VERSION 5.8 ;
BUSBITCHARS "[]" ;
DIVIDERCHAR "/" ;
UNITS
    DATABASE MICRONS 1000 ;
END UNITS

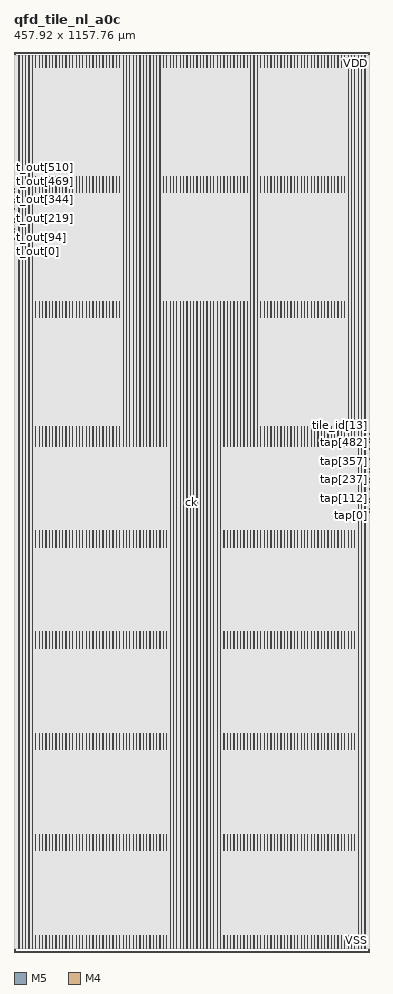
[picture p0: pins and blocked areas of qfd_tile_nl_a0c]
MACRO qfd_tile_nl_a0c
  FOREIGN qfd_tile_nl_a0c 0 0 ;
  CLASS BLOCK ;
  SIZE 457.92 BY 1157.76 ;
  PIN ck
    DIRECTION INPUT ;
    USE SIGNAL ;
    PORT
      LAYER M5 ;
        RECT  228.948 578.64 228.996 579.12 ;
    END
  END ck
  PIN rst_n
    DIRECTION INPUT ;
    USE SIGNAL ;
    PORT
      LAYER M4 ;
        RECT  457.836 669.984 457.92 670.008 ;
    END
  END rst_n
  PIN t_out[0]
    DIRECTION OUTPUT ;
    USE SIGNAL ;
    PORT
      LAYER M4 ;
        RECT  0 900.672 0.084 900.696 ;
    END
  END t_out[0]
  PIN t_out[100]
    DIRECTION OUTPUT ;
    USE SIGNAL ;
    PORT
      LAYER M4 ;
        RECT  0 920.64 0.084 920.664 ;
    END
  END t_out[100]
  PIN t_out[101]
    DIRECTION OUTPUT ;
    USE SIGNAL ;
    PORT
      LAYER M4 ;
        RECT  0 920.832 0.084 920.856 ;
    END
  END t_out[101]
  PIN t_out[102]
    DIRECTION OUTPUT ;
    USE SIGNAL ;
    PORT
      LAYER M4 ;
        RECT  0 921.024 0.084 921.048 ;
    END
  END t_out[102]
  PIN t_out[103]
    DIRECTION OUTPUT ;
    USE SIGNAL ;
    PORT
      LAYER M4 ;
        RECT  0 921.216 0.084 921.24 ;
    END
  END t_out[103]
  PIN t_out[104]
    DIRECTION OUTPUT ;
    USE SIGNAL ;
    PORT
      LAYER M4 ;
        RECT  0 921.408 0.084 921.432 ;
    END
  END t_out[104]
  PIN t_out[105]
    DIRECTION OUTPUT ;
    USE SIGNAL ;
    PORT
      LAYER M4 ;
        RECT  0 921.6 0.084 921.624 ;
    END
  END t_out[105]
  PIN t_out[106]
    DIRECTION OUTPUT ;
    USE SIGNAL ;
    PORT
      LAYER M4 ;
        RECT  0 921.792 0.084 921.816 ;
    END
  END t_out[106]
  PIN t_out[107]
    DIRECTION OUTPUT ;
    USE SIGNAL ;
    PORT
      LAYER M4 ;
        RECT  0 921.984 0.084 922.008 ;
    END
  END t_out[107]
  PIN t_out[108]
    DIRECTION OUTPUT ;
    USE SIGNAL ;
    PORT
      LAYER M4 ;
        RECT  0 922.176 0.084 922.2 ;
    END
  END t_out[108]
  PIN t_out[109]
    DIRECTION OUTPUT ;
    USE SIGNAL ;
    PORT
      LAYER M4 ;
        RECT  0 922.368 0.084 922.392 ;
    END
  END t_out[109]
  PIN t_out[10]
    DIRECTION OUTPUT ;
    USE SIGNAL ;
    PORT
      LAYER M4 ;
        RECT  0 902.592 0.084 902.616 ;
    END
  END t_out[10]
  PIN t_out[110]
    DIRECTION OUTPUT ;
    USE SIGNAL ;
    PORT
      LAYER M4 ;
        RECT  0 922.56 0.084 922.584 ;
    END
  END t_out[110]
  PIN t_out[111]
    DIRECTION OUTPUT ;
    USE SIGNAL ;
    PORT
      LAYER M4 ;
        RECT  0 922.752 0.084 922.776 ;
    END
  END t_out[111]
  PIN t_out[112]
    DIRECTION OUTPUT ;
    USE SIGNAL ;
    PORT
      LAYER M4 ;
        RECT  0 922.944 0.084 922.968 ;
    END
  END t_out[112]
  PIN t_out[113]
    DIRECTION OUTPUT ;
    USE SIGNAL ;
    PORT
      LAYER M4 ;
        RECT  0 923.136 0.084 923.16 ;
    END
  END t_out[113]
  PIN t_out[114]
    DIRECTION OUTPUT ;
    USE SIGNAL ;
    PORT
      LAYER M4 ;
        RECT  0 923.328 0.084 923.352 ;
    END
  END t_out[114]
  PIN t_out[115]
    DIRECTION OUTPUT ;
    USE SIGNAL ;
    PORT
      LAYER M4 ;
        RECT  0 923.52 0.084 923.544 ;
    END
  END t_out[115]
  PIN t_out[116]
    DIRECTION OUTPUT ;
    USE SIGNAL ;
    PORT
      LAYER M4 ;
        RECT  0 923.712 0.084 923.736 ;
    END
  END t_out[116]
  PIN t_out[117]
    DIRECTION OUTPUT ;
    USE SIGNAL ;
    PORT
      LAYER M4 ;
        RECT  0 923.904 0.084 923.928 ;
    END
  END t_out[117]
  PIN t_out[118]
    DIRECTION OUTPUT ;
    USE SIGNAL ;
    PORT
      LAYER M4 ;
        RECT  0 924.096 0.084 924.12 ;
    END
  END t_out[118]
  PIN t_out[119]
    DIRECTION OUTPUT ;
    USE SIGNAL ;
    PORT
      LAYER M4 ;
        RECT  0 924.288 0.084 924.312 ;
    END
  END t_out[119]
  PIN t_out[11]
    DIRECTION OUTPUT ;
    USE SIGNAL ;
    PORT
      LAYER M4 ;
        RECT  0 902.784 0.084 902.808 ;
    END
  END t_out[11]
  PIN t_out[120]
    DIRECTION OUTPUT ;
    USE SIGNAL ;
    PORT
      LAYER M4 ;
        RECT  0 924.48 0.084 924.504 ;
    END
  END t_out[120]
  PIN t_out[121]
    DIRECTION OUTPUT ;
    USE SIGNAL ;
    PORT
      LAYER M4 ;
        RECT  0 924.672 0.084 924.696 ;
    END
  END t_out[121]
  PIN t_out[122]
    DIRECTION OUTPUT ;
    USE SIGNAL ;
    PORT
      LAYER M4 ;
        RECT  0 924.864 0.084 924.888 ;
    END
  END t_out[122]
  PIN t_out[123]
    DIRECTION OUTPUT ;
    USE SIGNAL ;
    PORT
      LAYER M4 ;
        RECT  0 925.056 0.084 925.08 ;
    END
  END t_out[123]
  PIN t_out[124]
    DIRECTION OUTPUT ;
    USE SIGNAL ;
    PORT
      LAYER M4 ;
        RECT  0 925.248 0.084 925.272 ;
    END
  END t_out[124]
  PIN t_out[125]
    DIRECTION OUTPUT ;
    USE SIGNAL ;
    PORT
      LAYER M4 ;
        RECT  0 925.44 0.084 925.464 ;
    END
  END t_out[125]
  PIN t_out[126]
    DIRECTION OUTPUT ;
    USE SIGNAL ;
    PORT
      LAYER M4 ;
        RECT  0 925.632 0.084 925.656 ;
    END
  END t_out[126]
  PIN t_out[127]
    DIRECTION OUTPUT ;
    USE SIGNAL ;
    PORT
      LAYER M4 ;
        RECT  0 925.824 0.084 925.848 ;
    END
  END t_out[127]
  PIN t_out[128]
    DIRECTION OUTPUT ;
    USE SIGNAL ;
    PORT
      LAYER M4 ;
        RECT  0 926.016 0.084 926.04 ;
    END
  END t_out[128]
  PIN t_out[129]
    DIRECTION OUTPUT ;
    USE SIGNAL ;
    PORT
      LAYER M4 ;
        RECT  0 926.208 0.084 926.232 ;
    END
  END t_out[129]
  PIN t_out[12]
    DIRECTION OUTPUT ;
    USE SIGNAL ;
    PORT
      LAYER M4 ;
        RECT  0 902.976 0.084 903 ;
    END
  END t_out[12]
  PIN t_out[130]
    DIRECTION OUTPUT ;
    USE SIGNAL ;
    PORT
      LAYER M4 ;
        RECT  0 926.4 0.084 926.424 ;
    END
  END t_out[130]
  PIN t_out[131]
    DIRECTION OUTPUT ;
    USE SIGNAL ;
    PORT
      LAYER M4 ;
        RECT  0 926.592 0.084 926.616 ;
    END
  END t_out[131]
  PIN t_out[132]
    DIRECTION OUTPUT ;
    USE SIGNAL ;
    PORT
      LAYER M4 ;
        RECT  0 926.784 0.084 926.808 ;
    END
  END t_out[132]
  PIN t_out[133]
    DIRECTION OUTPUT ;
    USE SIGNAL ;
    PORT
      LAYER M4 ;
        RECT  0 926.976 0.084 927 ;
    END
  END t_out[133]
  PIN t_out[134]
    DIRECTION OUTPUT ;
    USE SIGNAL ;
    PORT
      LAYER M4 ;
        RECT  0 927.168 0.084 927.192 ;
    END
  END t_out[134]
  PIN t_out[135]
    DIRECTION OUTPUT ;
    USE SIGNAL ;
    PORT
      LAYER M4 ;
        RECT  0 927.36 0.084 927.384 ;
    END
  END t_out[135]
  PIN t_out[136]
    DIRECTION OUTPUT ;
    USE SIGNAL ;
    PORT
      LAYER M4 ;
        RECT  0 927.552 0.084 927.576 ;
    END
  END t_out[136]
  PIN t_out[137]
    DIRECTION OUTPUT ;
    USE SIGNAL ;
    PORT
      LAYER M4 ;
        RECT  0 927.744 0.084 927.768 ;
    END
  END t_out[137]
  PIN t_out[138]
    DIRECTION OUTPUT ;
    USE SIGNAL ;
    PORT
      LAYER M4 ;
        RECT  0 927.936 0.084 927.96 ;
    END
  END t_out[138]
  PIN t_out[139]
    DIRECTION OUTPUT ;
    USE SIGNAL ;
    PORT
      LAYER M4 ;
        RECT  0 928.128 0.084 928.152 ;
    END
  END t_out[139]
  PIN t_out[13]
    DIRECTION OUTPUT ;
    USE SIGNAL ;
    PORT
      LAYER M4 ;
        RECT  0 903.168 0.084 903.192 ;
    END
  END t_out[13]
  PIN t_out[140]
    DIRECTION OUTPUT ;
    USE SIGNAL ;
    PORT
      LAYER M4 ;
        RECT  0 928.32 0.084 928.344 ;
    END
  END t_out[140]
  PIN t_out[141]
    DIRECTION OUTPUT ;
    USE SIGNAL ;
    PORT
      LAYER M4 ;
        RECT  0 928.512 0.084 928.536 ;
    END
  END t_out[141]
  PIN t_out[142]
    DIRECTION OUTPUT ;
    USE SIGNAL ;
    PORT
      LAYER M4 ;
        RECT  0 928.704 0.084 928.728 ;
    END
  END t_out[142]
  PIN t_out[143]
    DIRECTION OUTPUT ;
    USE SIGNAL ;
    PORT
      LAYER M4 ;
        RECT  0 928.896 0.084 928.92 ;
    END
  END t_out[143]
  PIN t_out[144]
    DIRECTION OUTPUT ;
    USE SIGNAL ;
    PORT
      LAYER M4 ;
        RECT  0 929.088 0.084 929.112 ;
    END
  END t_out[144]
  PIN t_out[145]
    DIRECTION OUTPUT ;
    USE SIGNAL ;
    PORT
      LAYER M4 ;
        RECT  0 929.28 0.084 929.304 ;
    END
  END t_out[145]
  PIN t_out[146]
    DIRECTION OUTPUT ;
    USE SIGNAL ;
    PORT
      LAYER M4 ;
        RECT  0 929.472 0.084 929.496 ;
    END
  END t_out[146]
  PIN t_out[147]
    DIRECTION OUTPUT ;
    USE SIGNAL ;
    PORT
      LAYER M4 ;
        RECT  0 929.664 0.084 929.688 ;
    END
  END t_out[147]
  PIN t_out[148]
    DIRECTION OUTPUT ;
    USE SIGNAL ;
    PORT
      LAYER M4 ;
        RECT  0 929.856 0.084 929.88 ;
    END
  END t_out[148]
  PIN t_out[149]
    DIRECTION OUTPUT ;
    USE SIGNAL ;
    PORT
      LAYER M4 ;
        RECT  0 930.048 0.084 930.072 ;
    END
  END t_out[149]
  PIN t_out[14]
    DIRECTION OUTPUT ;
    USE SIGNAL ;
    PORT
      LAYER M4 ;
        RECT  0 903.36 0.084 903.384 ;
    END
  END t_out[14]
  PIN t_out[150]
    DIRECTION OUTPUT ;
    USE SIGNAL ;
    PORT
      LAYER M4 ;
        RECT  0 930.24 0.084 930.264 ;
    END
  END t_out[150]
  PIN t_out[151]
    DIRECTION OUTPUT ;
    USE SIGNAL ;
    PORT
      LAYER M4 ;
        RECT  0 930.432 0.084 930.456 ;
    END
  END t_out[151]
  PIN t_out[152]
    DIRECTION OUTPUT ;
    USE SIGNAL ;
    PORT
      LAYER M4 ;
        RECT  0 930.624 0.084 930.648 ;
    END
  END t_out[152]
  PIN t_out[153]
    DIRECTION OUTPUT ;
    USE SIGNAL ;
    PORT
      LAYER M4 ;
        RECT  0 930.816 0.084 930.84 ;
    END
  END t_out[153]
  PIN t_out[154]
    DIRECTION OUTPUT ;
    USE SIGNAL ;
    PORT
      LAYER M4 ;
        RECT  0 931.008 0.084 931.032 ;
    END
  END t_out[154]
  PIN t_out[155]
    DIRECTION OUTPUT ;
    USE SIGNAL ;
    PORT
      LAYER M4 ;
        RECT  0 931.2 0.084 931.224 ;
    END
  END t_out[155]
  PIN t_out[156]
    DIRECTION OUTPUT ;
    USE SIGNAL ;
    PORT
      LAYER M4 ;
        RECT  0 931.392 0.084 931.416 ;
    END
  END t_out[156]
  PIN t_out[157]
    DIRECTION OUTPUT ;
    USE SIGNAL ;
    PORT
      LAYER M4 ;
        RECT  0 931.584 0.084 931.608 ;
    END
  END t_out[157]
  PIN t_out[158]
    DIRECTION OUTPUT ;
    USE SIGNAL ;
    PORT
      LAYER M4 ;
        RECT  0 931.776 0.084 931.8 ;
    END
  END t_out[158]
  PIN t_out[159]
    DIRECTION OUTPUT ;
    USE SIGNAL ;
    PORT
      LAYER M4 ;
        RECT  0 931.968 0.084 931.992 ;
    END
  END t_out[159]
  PIN t_out[15]
    DIRECTION OUTPUT ;
    USE SIGNAL ;
    PORT
      LAYER M4 ;
        RECT  0 903.552 0.084 903.576 ;
    END
  END t_out[15]
  PIN t_out[160]
    DIRECTION OUTPUT ;
    USE SIGNAL ;
    PORT
      LAYER M4 ;
        RECT  0 932.16 0.084 932.184 ;
    END
  END t_out[160]
  PIN t_out[161]
    DIRECTION OUTPUT ;
    USE SIGNAL ;
    PORT
      LAYER M4 ;
        RECT  0 932.352 0.084 932.376 ;
    END
  END t_out[161]
  PIN t_out[162]
    DIRECTION OUTPUT ;
    USE SIGNAL ;
    PORT
      LAYER M4 ;
        RECT  0 932.544 0.084 932.568 ;
    END
  END t_out[162]
  PIN t_out[163]
    DIRECTION OUTPUT ;
    USE SIGNAL ;
    PORT
      LAYER M4 ;
        RECT  0 932.736 0.084 932.76 ;
    END
  END t_out[163]
  PIN t_out[164]
    DIRECTION OUTPUT ;
    USE SIGNAL ;
    PORT
      LAYER M4 ;
        RECT  0 932.928 0.084 932.952 ;
    END
  END t_out[164]
  PIN t_out[165]
    DIRECTION OUTPUT ;
    USE SIGNAL ;
    PORT
      LAYER M4 ;
        RECT  0 933.12 0.084 933.144 ;
    END
  END t_out[165]
  PIN t_out[166]
    DIRECTION OUTPUT ;
    USE SIGNAL ;
    PORT
      LAYER M4 ;
        RECT  0 933.312 0.084 933.336 ;
    END
  END t_out[166]
  PIN t_out[167]
    DIRECTION OUTPUT ;
    USE SIGNAL ;
    PORT
      LAYER M4 ;
        RECT  0 933.504 0.084 933.528 ;
    END
  END t_out[167]
  PIN t_out[168]
    DIRECTION OUTPUT ;
    USE SIGNAL ;
    PORT
      LAYER M4 ;
        RECT  0 933.696 0.084 933.72 ;
    END
  END t_out[168]
  PIN t_out[169]
    DIRECTION OUTPUT ;
    USE SIGNAL ;
    PORT
      LAYER M4 ;
        RECT  0 933.888 0.084 933.912 ;
    END
  END t_out[169]
  PIN t_out[16]
    DIRECTION OUTPUT ;
    USE SIGNAL ;
    PORT
      LAYER M4 ;
        RECT  0 903.744 0.084 903.768 ;
    END
  END t_out[16]
  PIN t_out[170]
    DIRECTION OUTPUT ;
    USE SIGNAL ;
    PORT
      LAYER M4 ;
        RECT  0 934.08 0.084 934.104 ;
    END
  END t_out[170]
  PIN t_out[171]
    DIRECTION OUTPUT ;
    USE SIGNAL ;
    PORT
      LAYER M4 ;
        RECT  0 934.272 0.084 934.296 ;
    END
  END t_out[171]
  PIN t_out[172]
    DIRECTION OUTPUT ;
    USE SIGNAL ;
    PORT
      LAYER M4 ;
        RECT  0 934.464 0.084 934.488 ;
    END
  END t_out[172]
  PIN t_out[173]
    DIRECTION OUTPUT ;
    USE SIGNAL ;
    PORT
      LAYER M4 ;
        RECT  0 934.656 0.084 934.68 ;
    END
  END t_out[173]
  PIN t_out[174]
    DIRECTION OUTPUT ;
    USE SIGNAL ;
    PORT
      LAYER M4 ;
        RECT  0 934.848 0.084 934.872 ;
    END
  END t_out[174]
  PIN t_out[175]
    DIRECTION OUTPUT ;
    USE SIGNAL ;
    PORT
      LAYER M4 ;
        RECT  0 935.04 0.084 935.064 ;
    END
  END t_out[175]
  PIN t_out[176]
    DIRECTION OUTPUT ;
    USE SIGNAL ;
    PORT
      LAYER M4 ;
        RECT  0 935.232 0.084 935.256 ;
    END
  END t_out[176]
  PIN t_out[177]
    DIRECTION OUTPUT ;
    USE SIGNAL ;
    PORT
      LAYER M4 ;
        RECT  0 935.424 0.084 935.448 ;
    END
  END t_out[177]
  PIN t_out[178]
    DIRECTION OUTPUT ;
    USE SIGNAL ;
    PORT
      LAYER M4 ;
        RECT  0 935.616 0.084 935.64 ;
    END
  END t_out[178]
  PIN t_out[179]
    DIRECTION OUTPUT ;
    USE SIGNAL ;
    PORT
      LAYER M4 ;
        RECT  0 935.808 0.084 935.832 ;
    END
  END t_out[179]
  PIN t_out[17]
    DIRECTION OUTPUT ;
    USE SIGNAL ;
    PORT
      LAYER M4 ;
        RECT  0 903.936 0.084 903.96 ;
    END
  END t_out[17]
  PIN t_out[180]
    DIRECTION OUTPUT ;
    USE SIGNAL ;
    PORT
      LAYER M4 ;
        RECT  0 936 0.084 936.024 ;
    END
  END t_out[180]
  PIN t_out[181]
    DIRECTION OUTPUT ;
    USE SIGNAL ;
    PORT
      LAYER M4 ;
        RECT  0 936.192 0.084 936.216 ;
    END
  END t_out[181]
  PIN t_out[182]
    DIRECTION OUTPUT ;
    USE SIGNAL ;
    PORT
      LAYER M4 ;
        RECT  0 936.384 0.084 936.408 ;
    END
  END t_out[182]
  PIN t_out[183]
    DIRECTION OUTPUT ;
    USE SIGNAL ;
    PORT
      LAYER M4 ;
        RECT  0 936.576 0.084 936.6 ;
    END
  END t_out[183]
  PIN t_out[184]
    DIRECTION OUTPUT ;
    USE SIGNAL ;
    PORT
      LAYER M4 ;
        RECT  0 936.768 0.084 936.792 ;
    END
  END t_out[184]
  PIN t_out[185]
    DIRECTION OUTPUT ;
    USE SIGNAL ;
    PORT
      LAYER M4 ;
        RECT  0 936.96 0.084 936.984 ;
    END
  END t_out[185]
  PIN t_out[186]
    DIRECTION OUTPUT ;
    USE SIGNAL ;
    PORT
      LAYER M4 ;
        RECT  0 937.152 0.084 937.176 ;
    END
  END t_out[186]
  PIN t_out[187]
    DIRECTION OUTPUT ;
    USE SIGNAL ;
    PORT
      LAYER M4 ;
        RECT  0 937.344 0.084 937.368 ;
    END
  END t_out[187]
  PIN t_out[188]
    DIRECTION OUTPUT ;
    USE SIGNAL ;
    PORT
      LAYER M4 ;
        RECT  0 937.536 0.084 937.56 ;
    END
  END t_out[188]
  PIN t_out[189]
    DIRECTION OUTPUT ;
    USE SIGNAL ;
    PORT
      LAYER M4 ;
        RECT  0 937.728 0.084 937.752 ;
    END
  END t_out[189]
  PIN t_out[18]
    DIRECTION OUTPUT ;
    USE SIGNAL ;
    PORT
      LAYER M4 ;
        RECT  0 904.128 0.084 904.152 ;
    END
  END t_out[18]
  PIN t_out[190]
    DIRECTION OUTPUT ;
    USE SIGNAL ;
    PORT
      LAYER M4 ;
        RECT  0 937.92 0.084 937.944 ;
    END
  END t_out[190]
  PIN t_out[191]
    DIRECTION OUTPUT ;
    USE SIGNAL ;
    PORT
      LAYER M4 ;
        RECT  0 938.112 0.084 938.136 ;
    END
  END t_out[191]
  PIN t_out[192]
    DIRECTION OUTPUT ;
    USE SIGNAL ;
    PORT
      LAYER M4 ;
        RECT  0 938.304 0.084 938.328 ;
    END
  END t_out[192]
  PIN t_out[193]
    DIRECTION OUTPUT ;
    USE SIGNAL ;
    PORT
      LAYER M4 ;
        RECT  0 938.496 0.084 938.52 ;
    END
  END t_out[193]
  PIN t_out[194]
    DIRECTION OUTPUT ;
    USE SIGNAL ;
    PORT
      LAYER M4 ;
        RECT  0 938.688 0.084 938.712 ;
    END
  END t_out[194]
  PIN t_out[195]
    DIRECTION OUTPUT ;
    USE SIGNAL ;
    PORT
      LAYER M4 ;
        RECT  0 938.88 0.084 938.904 ;
    END
  END t_out[195]
  PIN t_out[196]
    DIRECTION OUTPUT ;
    USE SIGNAL ;
    PORT
      LAYER M4 ;
        RECT  0 939.072 0.084 939.096 ;
    END
  END t_out[196]
  PIN t_out[197]
    DIRECTION OUTPUT ;
    USE SIGNAL ;
    PORT
      LAYER M4 ;
        RECT  0 939.264 0.084 939.288 ;
    END
  END t_out[197]
  PIN t_out[198]
    DIRECTION OUTPUT ;
    USE SIGNAL ;
    PORT
      LAYER M4 ;
        RECT  0 939.456 0.084 939.48 ;
    END
  END t_out[198]
  PIN t_out[199]
    DIRECTION OUTPUT ;
    USE SIGNAL ;
    PORT
      LAYER M4 ;
        RECT  0 939.648 0.084 939.672 ;
    END
  END t_out[199]
  PIN t_out[19]
    DIRECTION OUTPUT ;
    USE SIGNAL ;
    PORT
      LAYER M4 ;
        RECT  0 904.32 0.084 904.344 ;
    END
  END t_out[19]
  PIN t_out[1]
    DIRECTION OUTPUT ;
    USE SIGNAL ;
    PORT
      LAYER M4 ;
        RECT  0 900.864 0.084 900.888 ;
    END
  END t_out[1]
  PIN t_out[200]
    DIRECTION OUTPUT ;
    USE SIGNAL ;
    PORT
      LAYER M4 ;
        RECT  0 939.84 0.084 939.864 ;
    END
  END t_out[200]
  PIN t_out[201]
    DIRECTION OUTPUT ;
    USE SIGNAL ;
    PORT
      LAYER M4 ;
        RECT  0 940.032 0.084 940.056 ;
    END
  END t_out[201]
  PIN t_out[202]
    DIRECTION OUTPUT ;
    USE SIGNAL ;
    PORT
      LAYER M4 ;
        RECT  0 940.224 0.084 940.248 ;
    END
  END t_out[202]
  PIN t_out[203]
    DIRECTION OUTPUT ;
    USE SIGNAL ;
    PORT
      LAYER M4 ;
        RECT  0 940.416 0.084 940.44 ;
    END
  END t_out[203]
  PIN t_out[204]
    DIRECTION OUTPUT ;
    USE SIGNAL ;
    PORT
      LAYER M4 ;
        RECT  0 940.608 0.084 940.632 ;
    END
  END t_out[204]
  PIN t_out[205]
    DIRECTION OUTPUT ;
    USE SIGNAL ;
    PORT
      LAYER M4 ;
        RECT  0 940.8 0.084 940.824 ;
    END
  END t_out[205]
  PIN t_out[206]
    DIRECTION OUTPUT ;
    USE SIGNAL ;
    PORT
      LAYER M4 ;
        RECT  0 940.992 0.084 941.016 ;
    END
  END t_out[206]
  PIN t_out[207]
    DIRECTION OUTPUT ;
    USE SIGNAL ;
    PORT
      LAYER M4 ;
        RECT  0 941.184 0.084 941.208 ;
    END
  END t_out[207]
  PIN t_out[208]
    DIRECTION OUTPUT ;
    USE SIGNAL ;
    PORT
      LAYER M4 ;
        RECT  0 941.376 0.084 941.4 ;
    END
  END t_out[208]
  PIN t_out[209]
    DIRECTION OUTPUT ;
    USE SIGNAL ;
    PORT
      LAYER M4 ;
        RECT  0 941.568 0.084 941.592 ;
    END
  END t_out[209]
  PIN t_out[20]
    DIRECTION OUTPUT ;
    USE SIGNAL ;
    PORT
      LAYER M4 ;
        RECT  0 904.512 0.084 904.536 ;
    END
  END t_out[20]
  PIN t_out[210]
    DIRECTION OUTPUT ;
    USE SIGNAL ;
    PORT
      LAYER M4 ;
        RECT  0 941.76 0.084 941.784 ;
    END
  END t_out[210]
  PIN t_out[211]
    DIRECTION OUTPUT ;
    USE SIGNAL ;
    PORT
      LAYER M4 ;
        RECT  0 941.952 0.084 941.976 ;
    END
  END t_out[211]
  PIN t_out[212]
    DIRECTION OUTPUT ;
    USE SIGNAL ;
    PORT
      LAYER M4 ;
        RECT  0 942.144 0.084 942.168 ;
    END
  END t_out[212]
  PIN t_out[213]
    DIRECTION OUTPUT ;
    USE SIGNAL ;
    PORT
      LAYER M4 ;
        RECT  0 942.336 0.084 942.36 ;
    END
  END t_out[213]
  PIN t_out[214]
    DIRECTION OUTPUT ;
    USE SIGNAL ;
    PORT
      LAYER M4 ;
        RECT  0 942.528 0.084 942.552 ;
    END
  END t_out[214]
  PIN t_out[215]
    DIRECTION OUTPUT ;
    USE SIGNAL ;
    PORT
      LAYER M4 ;
        RECT  0 942.72 0.084 942.744 ;
    END
  END t_out[215]
  PIN t_out[216]
    DIRECTION OUTPUT ;
    USE SIGNAL ;
    PORT
      LAYER M4 ;
        RECT  0 942.912 0.084 942.936 ;
    END
  END t_out[216]
  PIN t_out[217]
    DIRECTION OUTPUT ;
    USE SIGNAL ;
    PORT
      LAYER M4 ;
        RECT  0 943.104 0.084 943.128 ;
    END
  END t_out[217]
  PIN t_out[218]
    DIRECTION OUTPUT ;
    USE SIGNAL ;
    PORT
      LAYER M4 ;
        RECT  0 943.296 0.084 943.32 ;
    END
  END t_out[218]
  PIN t_out[219]
    DIRECTION OUTPUT ;
    USE SIGNAL ;
    PORT
      LAYER M4 ;
        RECT  0 943.488 0.084 943.512 ;
    END
  END t_out[219]
  PIN t_out[21]
    DIRECTION OUTPUT ;
    USE SIGNAL ;
    PORT
      LAYER M4 ;
        RECT  0 904.704 0.084 904.728 ;
    END
  END t_out[21]
  PIN t_out[220]
    DIRECTION OUTPUT ;
    USE SIGNAL ;
    PORT
      LAYER M4 ;
        RECT  0 943.68 0.084 943.704 ;
    END
  END t_out[220]
  PIN t_out[221]
    DIRECTION OUTPUT ;
    USE SIGNAL ;
    PORT
      LAYER M4 ;
        RECT  0 943.872 0.084 943.896 ;
    END
  END t_out[221]
  PIN t_out[222]
    DIRECTION OUTPUT ;
    USE SIGNAL ;
    PORT
      LAYER M4 ;
        RECT  0 944.064 0.084 944.088 ;
    END
  END t_out[222]
  PIN t_out[223]
    DIRECTION OUTPUT ;
    USE SIGNAL ;
    PORT
      LAYER M4 ;
        RECT  0 944.256 0.084 944.28 ;
    END
  END t_out[223]
  PIN t_out[224]
    DIRECTION OUTPUT ;
    USE SIGNAL ;
    PORT
      LAYER M4 ;
        RECT  0 944.448 0.084 944.472 ;
    END
  END t_out[224]
  PIN t_out[225]
    DIRECTION OUTPUT ;
    USE SIGNAL ;
    PORT
      LAYER M4 ;
        RECT  0 944.64 0.084 944.664 ;
    END
  END t_out[225]
  PIN t_out[226]
    DIRECTION OUTPUT ;
    USE SIGNAL ;
    PORT
      LAYER M4 ;
        RECT  0 944.832 0.084 944.856 ;
    END
  END t_out[226]
  PIN t_out[227]
    DIRECTION OUTPUT ;
    USE SIGNAL ;
    PORT
      LAYER M4 ;
        RECT  0 945.024 0.084 945.048 ;
    END
  END t_out[227]
  PIN t_out[228]
    DIRECTION OUTPUT ;
    USE SIGNAL ;
    PORT
      LAYER M4 ;
        RECT  0 945.216 0.084 945.24 ;
    END
  END t_out[228]
  PIN t_out[229]
    DIRECTION OUTPUT ;
    USE SIGNAL ;
    PORT
      LAYER M4 ;
        RECT  0 945.408 0.084 945.432 ;
    END
  END t_out[229]
  PIN t_out[22]
    DIRECTION OUTPUT ;
    USE SIGNAL ;
    PORT
      LAYER M4 ;
        RECT  0 904.896 0.084 904.92 ;
    END
  END t_out[22]
  PIN t_out[230]
    DIRECTION OUTPUT ;
    USE SIGNAL ;
    PORT
      LAYER M4 ;
        RECT  0 945.6 0.084 945.624 ;
    END
  END t_out[230]
  PIN t_out[231]
    DIRECTION OUTPUT ;
    USE SIGNAL ;
    PORT
      LAYER M4 ;
        RECT  0 945.792 0.084 945.816 ;
    END
  END t_out[231]
  PIN t_out[232]
    DIRECTION OUTPUT ;
    USE SIGNAL ;
    PORT
      LAYER M4 ;
        RECT  0 945.984 0.084 946.008 ;
    END
  END t_out[232]
  PIN t_out[233]
    DIRECTION OUTPUT ;
    USE SIGNAL ;
    PORT
      LAYER M4 ;
        RECT  0 946.176 0.084 946.2 ;
    END
  END t_out[233]
  PIN t_out[234]
    DIRECTION OUTPUT ;
    USE SIGNAL ;
    PORT
      LAYER M4 ;
        RECT  0 946.368 0.084 946.392 ;
    END
  END t_out[234]
  PIN t_out[235]
    DIRECTION OUTPUT ;
    USE SIGNAL ;
    PORT
      LAYER M4 ;
        RECT  0 946.56 0.084 946.584 ;
    END
  END t_out[235]
  PIN t_out[236]
    DIRECTION OUTPUT ;
    USE SIGNAL ;
    PORT
      LAYER M4 ;
        RECT  0 946.752 0.084 946.776 ;
    END
  END t_out[236]
  PIN t_out[237]
    DIRECTION OUTPUT ;
    USE SIGNAL ;
    PORT
      LAYER M4 ;
        RECT  0 946.944 0.084 946.968 ;
    END
  END t_out[237]
  PIN t_out[238]
    DIRECTION OUTPUT ;
    USE SIGNAL ;
    PORT
      LAYER M4 ;
        RECT  0 947.136 0.084 947.16 ;
    END
  END t_out[238]
  PIN t_out[239]
    DIRECTION OUTPUT ;
    USE SIGNAL ;
    PORT
      LAYER M4 ;
        RECT  0 947.328 0.084 947.352 ;
    END
  END t_out[239]
  PIN t_out[23]
    DIRECTION OUTPUT ;
    USE SIGNAL ;
    PORT
      LAYER M4 ;
        RECT  0 905.088 0.084 905.112 ;
    END
  END t_out[23]
  PIN t_out[240]
    DIRECTION OUTPUT ;
    USE SIGNAL ;
    PORT
      LAYER M4 ;
        RECT  0 947.52 0.084 947.544 ;
    END
  END t_out[240]
  PIN t_out[241]
    DIRECTION OUTPUT ;
    USE SIGNAL ;
    PORT
      LAYER M4 ;
        RECT  0 947.712 0.084 947.736 ;
    END
  END t_out[241]
  PIN t_out[242]
    DIRECTION OUTPUT ;
    USE SIGNAL ;
    PORT
      LAYER M4 ;
        RECT  0 947.904 0.084 947.928 ;
    END
  END t_out[242]
  PIN t_out[243]
    DIRECTION OUTPUT ;
    USE SIGNAL ;
    PORT
      LAYER M4 ;
        RECT  0 948.096 0.084 948.12 ;
    END
  END t_out[243]
  PIN t_out[244]
    DIRECTION OUTPUT ;
    USE SIGNAL ;
    PORT
      LAYER M4 ;
        RECT  0 948.288 0.084 948.312 ;
    END
  END t_out[244]
  PIN t_out[245]
    DIRECTION OUTPUT ;
    USE SIGNAL ;
    PORT
      LAYER M4 ;
        RECT  0 948.48 0.084 948.504 ;
    END
  END t_out[245]
  PIN t_out[246]
    DIRECTION OUTPUT ;
    USE SIGNAL ;
    PORT
      LAYER M4 ;
        RECT  0 948.672 0.084 948.696 ;
    END
  END t_out[246]
  PIN t_out[247]
    DIRECTION OUTPUT ;
    USE SIGNAL ;
    PORT
      LAYER M4 ;
        RECT  0 948.864 0.084 948.888 ;
    END
  END t_out[247]
  PIN t_out[248]
    DIRECTION OUTPUT ;
    USE SIGNAL ;
    PORT
      LAYER M4 ;
        RECT  0 949.056 0.084 949.08 ;
    END
  END t_out[248]
  PIN t_out[249]
    DIRECTION OUTPUT ;
    USE SIGNAL ;
    PORT
      LAYER M4 ;
        RECT  0 949.248 0.084 949.272 ;
    END
  END t_out[249]
  PIN t_out[24]
    DIRECTION OUTPUT ;
    USE SIGNAL ;
    PORT
      LAYER M4 ;
        RECT  0 905.28 0.084 905.304 ;
    END
  END t_out[24]
  PIN t_out[250]
    DIRECTION OUTPUT ;
    USE SIGNAL ;
    PORT
      LAYER M4 ;
        RECT  0 949.44 0.084 949.464 ;
    END
  END t_out[250]
  PIN t_out[251]
    DIRECTION OUTPUT ;
    USE SIGNAL ;
    PORT
      LAYER M4 ;
        RECT  0 949.632 0.084 949.656 ;
    END
  END t_out[251]
  PIN t_out[252]
    DIRECTION OUTPUT ;
    USE SIGNAL ;
    PORT
      LAYER M4 ;
        RECT  0 949.824 0.084 949.848 ;
    END
  END t_out[252]
  PIN t_out[253]
    DIRECTION OUTPUT ;
    USE SIGNAL ;
    PORT
      LAYER M4 ;
        RECT  0 950.016 0.084 950.04 ;
    END
  END t_out[253]
  PIN t_out[254]
    DIRECTION OUTPUT ;
    USE SIGNAL ;
    PORT
      LAYER M4 ;
        RECT  0 950.208 0.084 950.232 ;
    END
  END t_out[254]
  PIN t_out[255]
    DIRECTION OUTPUT ;
    USE SIGNAL ;
    PORT
      LAYER M4 ;
        RECT  0 950.4 0.084 950.424 ;
    END
  END t_out[255]
  PIN t_out[256]
    DIRECTION OUTPUT ;
    USE SIGNAL ;
    PORT
      LAYER M4 ;
        RECT  0 950.592 0.084 950.616 ;
    END
  END t_out[256]
  PIN t_out[257]
    DIRECTION OUTPUT ;
    USE SIGNAL ;
    PORT
      LAYER M4 ;
        RECT  0 950.784 0.084 950.808 ;
    END
  END t_out[257]
  PIN t_out[258]
    DIRECTION OUTPUT ;
    USE SIGNAL ;
    PORT
      LAYER M4 ;
        RECT  0 950.976 0.084 951 ;
    END
  END t_out[258]
  PIN t_out[259]
    DIRECTION OUTPUT ;
    USE SIGNAL ;
    PORT
      LAYER M4 ;
        RECT  0 951.168 0.084 951.192 ;
    END
  END t_out[259]
  PIN t_out[25]
    DIRECTION OUTPUT ;
    USE SIGNAL ;
    PORT
      LAYER M4 ;
        RECT  0 905.472 0.084 905.496 ;
    END
  END t_out[25]
  PIN t_out[260]
    DIRECTION OUTPUT ;
    USE SIGNAL ;
    PORT
      LAYER M4 ;
        RECT  0 951.36 0.084 951.384 ;
    END
  END t_out[260]
  PIN t_out[261]
    DIRECTION OUTPUT ;
    USE SIGNAL ;
    PORT
      LAYER M4 ;
        RECT  0 951.552 0.084 951.576 ;
    END
  END t_out[261]
  PIN t_out[262]
    DIRECTION OUTPUT ;
    USE SIGNAL ;
    PORT
      LAYER M4 ;
        RECT  0 951.744 0.084 951.768 ;
    END
  END t_out[262]
  PIN t_out[263]
    DIRECTION OUTPUT ;
    USE SIGNAL ;
    PORT
      LAYER M4 ;
        RECT  0 951.936 0.084 951.96 ;
    END
  END t_out[263]
  PIN t_out[264]
    DIRECTION OUTPUT ;
    USE SIGNAL ;
    PORT
      LAYER M4 ;
        RECT  0 952.128 0.084 952.152 ;
    END
  END t_out[264]
  PIN t_out[265]
    DIRECTION OUTPUT ;
    USE SIGNAL ;
    PORT
      LAYER M4 ;
        RECT  0 952.32 0.084 952.344 ;
    END
  END t_out[265]
  PIN t_out[266]
    DIRECTION OUTPUT ;
    USE SIGNAL ;
    PORT
      LAYER M4 ;
        RECT  0 952.512 0.084 952.536 ;
    END
  END t_out[266]
  PIN t_out[267]
    DIRECTION OUTPUT ;
    USE SIGNAL ;
    PORT
      LAYER M4 ;
        RECT  0 952.704 0.084 952.728 ;
    END
  END t_out[267]
  PIN t_out[268]
    DIRECTION OUTPUT ;
    USE SIGNAL ;
    PORT
      LAYER M4 ;
        RECT  0 952.896 0.084 952.92 ;
    END
  END t_out[268]
  PIN t_out[269]
    DIRECTION OUTPUT ;
    USE SIGNAL ;
    PORT
      LAYER M4 ;
        RECT  0 953.088 0.084 953.112 ;
    END
  END t_out[269]
  PIN t_out[26]
    DIRECTION OUTPUT ;
    USE SIGNAL ;
    PORT
      LAYER M4 ;
        RECT  0 905.664 0.084 905.688 ;
    END
  END t_out[26]
  PIN t_out[270]
    DIRECTION OUTPUT ;
    USE SIGNAL ;
    PORT
      LAYER M4 ;
        RECT  0 953.28 0.084 953.304 ;
    END
  END t_out[270]
  PIN t_out[271]
    DIRECTION OUTPUT ;
    USE SIGNAL ;
    PORT
      LAYER M4 ;
        RECT  0 953.472 0.084 953.496 ;
    END
  END t_out[271]
  PIN t_out[272]
    DIRECTION OUTPUT ;
    USE SIGNAL ;
    PORT
      LAYER M4 ;
        RECT  0 953.664 0.084 953.688 ;
    END
  END t_out[272]
  PIN t_out[273]
    DIRECTION OUTPUT ;
    USE SIGNAL ;
    PORT
      LAYER M4 ;
        RECT  0 953.856 0.084 953.88 ;
    END
  END t_out[273]
  PIN t_out[274]
    DIRECTION OUTPUT ;
    USE SIGNAL ;
    PORT
      LAYER M4 ;
        RECT  0 954.048 0.084 954.072 ;
    END
  END t_out[274]
  PIN t_out[275]
    DIRECTION OUTPUT ;
    USE SIGNAL ;
    PORT
      LAYER M4 ;
        RECT  0 954.24 0.084 954.264 ;
    END
  END t_out[275]
  PIN t_out[276]
    DIRECTION OUTPUT ;
    USE SIGNAL ;
    PORT
      LAYER M4 ;
        RECT  0 954.432 0.084 954.456 ;
    END
  END t_out[276]
  PIN t_out[277]
    DIRECTION OUTPUT ;
    USE SIGNAL ;
    PORT
      LAYER M4 ;
        RECT  0 954.624 0.084 954.648 ;
    END
  END t_out[277]
  PIN t_out[278]
    DIRECTION OUTPUT ;
    USE SIGNAL ;
    PORT
      LAYER M4 ;
        RECT  0 954.816 0.084 954.84 ;
    END
  END t_out[278]
  PIN t_out[279]
    DIRECTION OUTPUT ;
    USE SIGNAL ;
    PORT
      LAYER M4 ;
        RECT  0 955.008 0.084 955.032 ;
    END
  END t_out[279]
  PIN t_out[27]
    DIRECTION OUTPUT ;
    USE SIGNAL ;
    PORT
      LAYER M4 ;
        RECT  0 905.856 0.084 905.88 ;
    END
  END t_out[27]
  PIN t_out[280]
    DIRECTION OUTPUT ;
    USE SIGNAL ;
    PORT
      LAYER M4 ;
        RECT  0 955.2 0.084 955.224 ;
    END
  END t_out[280]
  PIN t_out[281]
    DIRECTION OUTPUT ;
    USE SIGNAL ;
    PORT
      LAYER M4 ;
        RECT  0 955.392 0.084 955.416 ;
    END
  END t_out[281]
  PIN t_out[282]
    DIRECTION OUTPUT ;
    USE SIGNAL ;
    PORT
      LAYER M4 ;
        RECT  0 955.584 0.084 955.608 ;
    END
  END t_out[282]
  PIN t_out[283]
    DIRECTION OUTPUT ;
    USE SIGNAL ;
    PORT
      LAYER M4 ;
        RECT  0 955.776 0.084 955.8 ;
    END
  END t_out[283]
  PIN t_out[284]
    DIRECTION OUTPUT ;
    USE SIGNAL ;
    PORT
      LAYER M4 ;
        RECT  0 955.968 0.084 955.992 ;
    END
  END t_out[284]
  PIN t_out[285]
    DIRECTION OUTPUT ;
    USE SIGNAL ;
    PORT
      LAYER M4 ;
        RECT  0 956.16 0.084 956.184 ;
    END
  END t_out[285]
  PIN t_out[286]
    DIRECTION OUTPUT ;
    USE SIGNAL ;
    PORT
      LAYER M4 ;
        RECT  0 956.352 0.084 956.376 ;
    END
  END t_out[286]
  PIN t_out[287]
    DIRECTION OUTPUT ;
    USE SIGNAL ;
    PORT
      LAYER M4 ;
        RECT  0 956.544 0.084 956.568 ;
    END
  END t_out[287]
  PIN t_out[288]
    DIRECTION OUTPUT ;
    USE SIGNAL ;
    PORT
      LAYER M4 ;
        RECT  0 956.736 0.084 956.76 ;
    END
  END t_out[288]
  PIN t_out[289]
    DIRECTION OUTPUT ;
    USE SIGNAL ;
    PORT
      LAYER M4 ;
        RECT  0 956.928 0.084 956.952 ;
    END
  END t_out[289]
  PIN t_out[28]
    DIRECTION OUTPUT ;
    USE SIGNAL ;
    PORT
      LAYER M4 ;
        RECT  0 906.048 0.084 906.072 ;
    END
  END t_out[28]
  PIN t_out[290]
    DIRECTION OUTPUT ;
    USE SIGNAL ;
    PORT
      LAYER M4 ;
        RECT  0 957.12 0.084 957.144 ;
    END
  END t_out[290]
  PIN t_out[291]
    DIRECTION OUTPUT ;
    USE SIGNAL ;
    PORT
      LAYER M4 ;
        RECT  0 957.312 0.084 957.336 ;
    END
  END t_out[291]
  PIN t_out[292]
    DIRECTION OUTPUT ;
    USE SIGNAL ;
    PORT
      LAYER M4 ;
        RECT  0 957.504 0.084 957.528 ;
    END
  END t_out[292]
  PIN t_out[293]
    DIRECTION OUTPUT ;
    USE SIGNAL ;
    PORT
      LAYER M4 ;
        RECT  0 957.696 0.084 957.72 ;
    END
  END t_out[293]
  PIN t_out[294]
    DIRECTION OUTPUT ;
    USE SIGNAL ;
    PORT
      LAYER M4 ;
        RECT  0 957.888 0.084 957.912 ;
    END
  END t_out[294]
  PIN t_out[295]
    DIRECTION OUTPUT ;
    USE SIGNAL ;
    PORT
      LAYER M4 ;
        RECT  0 958.08 0.084 958.104 ;
    END
  END t_out[295]
  PIN t_out[296]
    DIRECTION OUTPUT ;
    USE SIGNAL ;
    PORT
      LAYER M4 ;
        RECT  0 958.272 0.084 958.296 ;
    END
  END t_out[296]
  PIN t_out[297]
    DIRECTION OUTPUT ;
    USE SIGNAL ;
    PORT
      LAYER M4 ;
        RECT  0 958.464 0.084 958.488 ;
    END
  END t_out[297]
  PIN t_out[298]
    DIRECTION OUTPUT ;
    USE SIGNAL ;
    PORT
      LAYER M4 ;
        RECT  0 958.656 0.084 958.68 ;
    END
  END t_out[298]
  PIN t_out[299]
    DIRECTION OUTPUT ;
    USE SIGNAL ;
    PORT
      LAYER M4 ;
        RECT  0 958.848 0.084 958.872 ;
    END
  END t_out[299]
  PIN t_out[29]
    DIRECTION OUTPUT ;
    USE SIGNAL ;
    PORT
      LAYER M4 ;
        RECT  0 906.24 0.084 906.264 ;
    END
  END t_out[29]
  PIN t_out[2]
    DIRECTION OUTPUT ;
    USE SIGNAL ;
    PORT
      LAYER M4 ;
        RECT  0 901.056 0.084 901.08 ;
    END
  END t_out[2]
  PIN t_out[300]
    DIRECTION OUTPUT ;
    USE SIGNAL ;
    PORT
      LAYER M4 ;
        RECT  0 959.04 0.084 959.064 ;
    END
  END t_out[300]
  PIN t_out[301]
    DIRECTION OUTPUT ;
    USE SIGNAL ;
    PORT
      LAYER M4 ;
        RECT  0 959.232 0.084 959.256 ;
    END
  END t_out[301]
  PIN t_out[302]
    DIRECTION OUTPUT ;
    USE SIGNAL ;
    PORT
      LAYER M4 ;
        RECT  0 959.424 0.084 959.448 ;
    END
  END t_out[302]
  PIN t_out[303]
    DIRECTION OUTPUT ;
    USE SIGNAL ;
    PORT
      LAYER M4 ;
        RECT  0 959.616 0.084 959.64 ;
    END
  END t_out[303]
  PIN t_out[304]
    DIRECTION OUTPUT ;
    USE SIGNAL ;
    PORT
      LAYER M4 ;
        RECT  0 959.808 0.084 959.832 ;
    END
  END t_out[304]
  PIN t_out[305]
    DIRECTION OUTPUT ;
    USE SIGNAL ;
    PORT
      LAYER M4 ;
        RECT  0 960 0.084 960.024 ;
    END
  END t_out[305]
  PIN t_out[306]
    DIRECTION OUTPUT ;
    USE SIGNAL ;
    PORT
      LAYER M4 ;
        RECT  0 960.192 0.084 960.216 ;
    END
  END t_out[306]
  PIN t_out[307]
    DIRECTION OUTPUT ;
    USE SIGNAL ;
    PORT
      LAYER M4 ;
        RECT  0 960.384 0.084 960.408 ;
    END
  END t_out[307]
  PIN t_out[308]
    DIRECTION OUTPUT ;
    USE SIGNAL ;
    PORT
      LAYER M4 ;
        RECT  0 960.576 0.084 960.6 ;
    END
  END t_out[308]
  PIN t_out[309]
    DIRECTION OUTPUT ;
    USE SIGNAL ;
    PORT
      LAYER M4 ;
        RECT  0 960.768 0.084 960.792 ;
    END
  END t_out[309]
  PIN t_out[30]
    DIRECTION OUTPUT ;
    USE SIGNAL ;
    PORT
      LAYER M4 ;
        RECT  0 906.432 0.084 906.456 ;
    END
  END t_out[30]
  PIN t_out[310]
    DIRECTION OUTPUT ;
    USE SIGNAL ;
    PORT
      LAYER M4 ;
        RECT  0 960.96 0.084 960.984 ;
    END
  END t_out[310]
  PIN t_out[311]
    DIRECTION OUTPUT ;
    USE SIGNAL ;
    PORT
      LAYER M4 ;
        RECT  0 961.152 0.084 961.176 ;
    END
  END t_out[311]
  PIN t_out[312]
    DIRECTION OUTPUT ;
    USE SIGNAL ;
    PORT
      LAYER M4 ;
        RECT  0 961.344 0.084 961.368 ;
    END
  END t_out[312]
  PIN t_out[313]
    DIRECTION OUTPUT ;
    USE SIGNAL ;
    PORT
      LAYER M4 ;
        RECT  0 961.536 0.084 961.56 ;
    END
  END t_out[313]
  PIN t_out[314]
    DIRECTION OUTPUT ;
    USE SIGNAL ;
    PORT
      LAYER M4 ;
        RECT  0 961.728 0.084 961.752 ;
    END
  END t_out[314]
  PIN t_out[315]
    DIRECTION OUTPUT ;
    USE SIGNAL ;
    PORT
      LAYER M4 ;
        RECT  0 961.92 0.084 961.944 ;
    END
  END t_out[315]
  PIN t_out[316]
    DIRECTION OUTPUT ;
    USE SIGNAL ;
    PORT
      LAYER M4 ;
        RECT  0 962.112 0.084 962.136 ;
    END
  END t_out[316]
  PIN t_out[317]
    DIRECTION OUTPUT ;
    USE SIGNAL ;
    PORT
      LAYER M4 ;
        RECT  0 962.304 0.084 962.328 ;
    END
  END t_out[317]
  PIN t_out[318]
    DIRECTION OUTPUT ;
    USE SIGNAL ;
    PORT
      LAYER M4 ;
        RECT  0 962.496 0.084 962.52 ;
    END
  END t_out[318]
  PIN t_out[319]
    DIRECTION OUTPUT ;
    USE SIGNAL ;
    PORT
      LAYER M4 ;
        RECT  0 962.688 0.084 962.712 ;
    END
  END t_out[319]
  PIN t_out[31]
    DIRECTION OUTPUT ;
    USE SIGNAL ;
    PORT
      LAYER M4 ;
        RECT  0 906.624 0.084 906.648 ;
    END
  END t_out[31]
  PIN t_out[320]
    DIRECTION OUTPUT ;
    USE SIGNAL ;
    PORT
      LAYER M4 ;
        RECT  0 962.88 0.084 962.904 ;
    END
  END t_out[320]
  PIN t_out[321]
    DIRECTION OUTPUT ;
    USE SIGNAL ;
    PORT
      LAYER M4 ;
        RECT  0 963.072 0.084 963.096 ;
    END
  END t_out[321]
  PIN t_out[322]
    DIRECTION OUTPUT ;
    USE SIGNAL ;
    PORT
      LAYER M4 ;
        RECT  0 963.264 0.084 963.288 ;
    END
  END t_out[322]
  PIN t_out[323]
    DIRECTION OUTPUT ;
    USE SIGNAL ;
    PORT
      LAYER M4 ;
        RECT  0 963.456 0.084 963.48 ;
    END
  END t_out[323]
  PIN t_out[324]
    DIRECTION OUTPUT ;
    USE SIGNAL ;
    PORT
      LAYER M4 ;
        RECT  0 963.648 0.084 963.672 ;
    END
  END t_out[324]
  PIN t_out[325]
    DIRECTION OUTPUT ;
    USE SIGNAL ;
    PORT
      LAYER M4 ;
        RECT  0 963.84 0.084 963.864 ;
    END
  END t_out[325]
  PIN t_out[326]
    DIRECTION OUTPUT ;
    USE SIGNAL ;
    PORT
      LAYER M4 ;
        RECT  0 964.032 0.084 964.056 ;
    END
  END t_out[326]
  PIN t_out[327]
    DIRECTION OUTPUT ;
    USE SIGNAL ;
    PORT
      LAYER M4 ;
        RECT  0 964.224 0.084 964.248 ;
    END
  END t_out[327]
  PIN t_out[328]
    DIRECTION OUTPUT ;
    USE SIGNAL ;
    PORT
      LAYER M4 ;
        RECT  0 964.416 0.084 964.44 ;
    END
  END t_out[328]
  PIN t_out[329]
    DIRECTION OUTPUT ;
    USE SIGNAL ;
    PORT
      LAYER M4 ;
        RECT  0 964.608 0.084 964.632 ;
    END
  END t_out[329]
  PIN t_out[32]
    DIRECTION OUTPUT ;
    USE SIGNAL ;
    PORT
      LAYER M4 ;
        RECT  0 906.816 0.084 906.84 ;
    END
  END t_out[32]
  PIN t_out[330]
    DIRECTION OUTPUT ;
    USE SIGNAL ;
    PORT
      LAYER M4 ;
        RECT  0 964.8 0.084 964.824 ;
    END
  END t_out[330]
  PIN t_out[331]
    DIRECTION OUTPUT ;
    USE SIGNAL ;
    PORT
      LAYER M4 ;
        RECT  0 964.992 0.084 965.016 ;
    END
  END t_out[331]
  PIN t_out[332]
    DIRECTION OUTPUT ;
    USE SIGNAL ;
    PORT
      LAYER M4 ;
        RECT  0 965.184 0.084 965.208 ;
    END
  END t_out[332]
  PIN t_out[333]
    DIRECTION OUTPUT ;
    USE SIGNAL ;
    PORT
      LAYER M4 ;
        RECT  0 965.376 0.084 965.4 ;
    END
  END t_out[333]
  PIN t_out[334]
    DIRECTION OUTPUT ;
    USE SIGNAL ;
    PORT
      LAYER M4 ;
        RECT  0 965.568 0.084 965.592 ;
    END
  END t_out[334]
  PIN t_out[335]
    DIRECTION OUTPUT ;
    USE SIGNAL ;
    PORT
      LAYER M4 ;
        RECT  0 965.76 0.084 965.784 ;
    END
  END t_out[335]
  PIN t_out[336]
    DIRECTION OUTPUT ;
    USE SIGNAL ;
    PORT
      LAYER M4 ;
        RECT  0 965.952 0.084 965.976 ;
    END
  END t_out[336]
  PIN t_out[337]
    DIRECTION OUTPUT ;
    USE SIGNAL ;
    PORT
      LAYER M4 ;
        RECT  0 966.144 0.084 966.168 ;
    END
  END t_out[337]
  PIN t_out[338]
    DIRECTION OUTPUT ;
    USE SIGNAL ;
    PORT
      LAYER M4 ;
        RECT  0 966.336 0.084 966.36 ;
    END
  END t_out[338]
  PIN t_out[339]
    DIRECTION OUTPUT ;
    USE SIGNAL ;
    PORT
      LAYER M4 ;
        RECT  0 966.528 0.084 966.552 ;
    END
  END t_out[339]
  PIN t_out[33]
    DIRECTION OUTPUT ;
    USE SIGNAL ;
    PORT
      LAYER M4 ;
        RECT  0 907.008 0.084 907.032 ;
    END
  END t_out[33]
  PIN t_out[340]
    DIRECTION OUTPUT ;
    USE SIGNAL ;
    PORT
      LAYER M4 ;
        RECT  0 966.72 0.084 966.744 ;
    END
  END t_out[340]
  PIN t_out[341]
    DIRECTION OUTPUT ;
    USE SIGNAL ;
    PORT
      LAYER M4 ;
        RECT  0 966.912 0.084 966.936 ;
    END
  END t_out[341]
  PIN t_out[342]
    DIRECTION OUTPUT ;
    USE SIGNAL ;
    PORT
      LAYER M4 ;
        RECT  0 967.104 0.084 967.128 ;
    END
  END t_out[342]
  PIN t_out[343]
    DIRECTION OUTPUT ;
    USE SIGNAL ;
    PORT
      LAYER M4 ;
        RECT  0 967.296 0.084 967.32 ;
    END
  END t_out[343]
  PIN t_out[344]
    DIRECTION OUTPUT ;
    USE SIGNAL ;
    PORT
      LAYER M4 ;
        RECT  0 967.488 0.084 967.512 ;
    END
  END t_out[344]
  PIN t_out[345]
    DIRECTION OUTPUT ;
    USE SIGNAL ;
    PORT
      LAYER M4 ;
        RECT  0 967.68 0.084 967.704 ;
    END
  END t_out[345]
  PIN t_out[346]
    DIRECTION OUTPUT ;
    USE SIGNAL ;
    PORT
      LAYER M4 ;
        RECT  0 967.872 0.084 967.896 ;
    END
  END t_out[346]
  PIN t_out[347]
    DIRECTION OUTPUT ;
    USE SIGNAL ;
    PORT
      LAYER M4 ;
        RECT  0 968.064 0.084 968.088 ;
    END
  END t_out[347]
  PIN t_out[348]
    DIRECTION OUTPUT ;
    USE SIGNAL ;
    PORT
      LAYER M4 ;
        RECT  0 968.256 0.084 968.28 ;
    END
  END t_out[348]
  PIN t_out[349]
    DIRECTION OUTPUT ;
    USE SIGNAL ;
    PORT
      LAYER M4 ;
        RECT  0 968.448 0.084 968.472 ;
    END
  END t_out[349]
  PIN t_out[34]
    DIRECTION OUTPUT ;
    USE SIGNAL ;
    PORT
      LAYER M4 ;
        RECT  0 907.2 0.084 907.224 ;
    END
  END t_out[34]
  PIN t_out[350]
    DIRECTION OUTPUT ;
    USE SIGNAL ;
    PORT
      LAYER M4 ;
        RECT  0 968.64 0.084 968.664 ;
    END
  END t_out[350]
  PIN t_out[351]
    DIRECTION OUTPUT ;
    USE SIGNAL ;
    PORT
      LAYER M4 ;
        RECT  0 968.832 0.084 968.856 ;
    END
  END t_out[351]
  PIN t_out[352]
    DIRECTION OUTPUT ;
    USE SIGNAL ;
    PORT
      LAYER M4 ;
        RECT  0 969.024 0.084 969.048 ;
    END
  END t_out[352]
  PIN t_out[353]
    DIRECTION OUTPUT ;
    USE SIGNAL ;
    PORT
      LAYER M4 ;
        RECT  0 969.216 0.084 969.24 ;
    END
  END t_out[353]
  PIN t_out[354]
    DIRECTION OUTPUT ;
    USE SIGNAL ;
    PORT
      LAYER M4 ;
        RECT  0 969.408 0.084 969.432 ;
    END
  END t_out[354]
  PIN t_out[355]
    DIRECTION OUTPUT ;
    USE SIGNAL ;
    PORT
      LAYER M4 ;
        RECT  0 969.6 0.084 969.624 ;
    END
  END t_out[355]
  PIN t_out[356]
    DIRECTION OUTPUT ;
    USE SIGNAL ;
    PORT
      LAYER M4 ;
        RECT  0 969.792 0.084 969.816 ;
    END
  END t_out[356]
  PIN t_out[357]
    DIRECTION OUTPUT ;
    USE SIGNAL ;
    PORT
      LAYER M4 ;
        RECT  0 969.984 0.084 970.008 ;
    END
  END t_out[357]
  PIN t_out[358]
    DIRECTION OUTPUT ;
    USE SIGNAL ;
    PORT
      LAYER M4 ;
        RECT  0 970.176 0.084 970.2 ;
    END
  END t_out[358]
  PIN t_out[359]
    DIRECTION OUTPUT ;
    USE SIGNAL ;
    PORT
      LAYER M4 ;
        RECT  0 970.368 0.084 970.392 ;
    END
  END t_out[359]
  PIN t_out[35]
    DIRECTION OUTPUT ;
    USE SIGNAL ;
    PORT
      LAYER M4 ;
        RECT  0 907.392 0.084 907.416 ;
    END
  END t_out[35]
  PIN t_out[360]
    DIRECTION OUTPUT ;
    USE SIGNAL ;
    PORT
      LAYER M4 ;
        RECT  0 970.56 0.084 970.584 ;
    END
  END t_out[360]
  PIN t_out[361]
    DIRECTION OUTPUT ;
    USE SIGNAL ;
    PORT
      LAYER M4 ;
        RECT  0 970.752 0.084 970.776 ;
    END
  END t_out[361]
  PIN t_out[362]
    DIRECTION OUTPUT ;
    USE SIGNAL ;
    PORT
      LAYER M4 ;
        RECT  0 970.944 0.084 970.968 ;
    END
  END t_out[362]
  PIN t_out[363]
    DIRECTION OUTPUT ;
    USE SIGNAL ;
    PORT
      LAYER M4 ;
        RECT  0 971.136 0.084 971.16 ;
    END
  END t_out[363]
  PIN t_out[364]
    DIRECTION OUTPUT ;
    USE SIGNAL ;
    PORT
      LAYER M4 ;
        RECT  0 971.328 0.084 971.352 ;
    END
  END t_out[364]
  PIN t_out[365]
    DIRECTION OUTPUT ;
    USE SIGNAL ;
    PORT
      LAYER M4 ;
        RECT  0 971.52 0.084 971.544 ;
    END
  END t_out[365]
  PIN t_out[366]
    DIRECTION OUTPUT ;
    USE SIGNAL ;
    PORT
      LAYER M4 ;
        RECT  0 971.712 0.084 971.736 ;
    END
  END t_out[366]
  PIN t_out[367]
    DIRECTION OUTPUT ;
    USE SIGNAL ;
    PORT
      LAYER M4 ;
        RECT  0 971.904 0.084 971.928 ;
    END
  END t_out[367]
  PIN t_out[368]
    DIRECTION OUTPUT ;
    USE SIGNAL ;
    PORT
      LAYER M4 ;
        RECT  0 972.096 0.084 972.12 ;
    END
  END t_out[368]
  PIN t_out[369]
    DIRECTION OUTPUT ;
    USE SIGNAL ;
    PORT
      LAYER M4 ;
        RECT  0 972.288 0.084 972.312 ;
    END
  END t_out[369]
  PIN t_out[36]
    DIRECTION OUTPUT ;
    USE SIGNAL ;
    PORT
      LAYER M4 ;
        RECT  0 907.584 0.084 907.608 ;
    END
  END t_out[36]
  PIN t_out[370]
    DIRECTION OUTPUT ;
    USE SIGNAL ;
    PORT
      LAYER M4 ;
        RECT  0 972.48 0.084 972.504 ;
    END
  END t_out[370]
  PIN t_out[371]
    DIRECTION OUTPUT ;
    USE SIGNAL ;
    PORT
      LAYER M4 ;
        RECT  0 972.672 0.084 972.696 ;
    END
  END t_out[371]
  PIN t_out[372]
    DIRECTION OUTPUT ;
    USE SIGNAL ;
    PORT
      LAYER M4 ;
        RECT  0 972.864 0.084 972.888 ;
    END
  END t_out[372]
  PIN t_out[373]
    DIRECTION OUTPUT ;
    USE SIGNAL ;
    PORT
      LAYER M4 ;
        RECT  0 973.056 0.084 973.08 ;
    END
  END t_out[373]
  PIN t_out[374]
    DIRECTION OUTPUT ;
    USE SIGNAL ;
    PORT
      LAYER M4 ;
        RECT  0 973.248 0.084 973.272 ;
    END
  END t_out[374]
  PIN t_out[375]
    DIRECTION OUTPUT ;
    USE SIGNAL ;
    PORT
      LAYER M4 ;
        RECT  0 973.44 0.084 973.464 ;
    END
  END t_out[375]
  PIN t_out[376]
    DIRECTION OUTPUT ;
    USE SIGNAL ;
    PORT
      LAYER M4 ;
        RECT  0 973.632 0.084 973.656 ;
    END
  END t_out[376]
  PIN t_out[377]
    DIRECTION OUTPUT ;
    USE SIGNAL ;
    PORT
      LAYER M4 ;
        RECT  0 973.824 0.084 973.848 ;
    END
  END t_out[377]
  PIN t_out[378]
    DIRECTION OUTPUT ;
    USE SIGNAL ;
    PORT
      LAYER M4 ;
        RECT  0 974.016 0.084 974.04 ;
    END
  END t_out[378]
  PIN t_out[379]
    DIRECTION OUTPUT ;
    USE SIGNAL ;
    PORT
      LAYER M4 ;
        RECT  0 974.208 0.084 974.232 ;
    END
  END t_out[379]
  PIN t_out[37]
    DIRECTION OUTPUT ;
    USE SIGNAL ;
    PORT
      LAYER M4 ;
        RECT  0 907.776 0.084 907.8 ;
    END
  END t_out[37]
  PIN t_out[380]
    DIRECTION OUTPUT ;
    USE SIGNAL ;
    PORT
      LAYER M4 ;
        RECT  0 974.4 0.084 974.424 ;
    END
  END t_out[380]
  PIN t_out[381]
    DIRECTION OUTPUT ;
    USE SIGNAL ;
    PORT
      LAYER M4 ;
        RECT  0 974.592 0.084 974.616 ;
    END
  END t_out[381]
  PIN t_out[382]
    DIRECTION OUTPUT ;
    USE SIGNAL ;
    PORT
      LAYER M4 ;
        RECT  0 974.784 0.084 974.808 ;
    END
  END t_out[382]
  PIN t_out[383]
    DIRECTION OUTPUT ;
    USE SIGNAL ;
    PORT
      LAYER M4 ;
        RECT  0 974.976 0.084 975 ;
    END
  END t_out[383]
  PIN t_out[384]
    DIRECTION OUTPUT ;
    USE SIGNAL ;
    PORT
      LAYER M4 ;
        RECT  0 975.168 0.084 975.192 ;
    END
  END t_out[384]
  PIN t_out[385]
    DIRECTION OUTPUT ;
    USE SIGNAL ;
    PORT
      LAYER M4 ;
        RECT  0 975.36 0.084 975.384 ;
    END
  END t_out[385]
  PIN t_out[386]
    DIRECTION OUTPUT ;
    USE SIGNAL ;
    PORT
      LAYER M4 ;
        RECT  0 975.552 0.084 975.576 ;
    END
  END t_out[386]
  PIN t_out[387]
    DIRECTION OUTPUT ;
    USE SIGNAL ;
    PORT
      LAYER M4 ;
        RECT  0 975.744 0.084 975.768 ;
    END
  END t_out[387]
  PIN t_out[388]
    DIRECTION OUTPUT ;
    USE SIGNAL ;
    PORT
      LAYER M4 ;
        RECT  0 975.936 0.084 975.96 ;
    END
  END t_out[388]
  PIN t_out[389]
    DIRECTION OUTPUT ;
    USE SIGNAL ;
    PORT
      LAYER M4 ;
        RECT  0 976.128 0.084 976.152 ;
    END
  END t_out[389]
  PIN t_out[38]
    DIRECTION OUTPUT ;
    USE SIGNAL ;
    PORT
      LAYER M4 ;
        RECT  0 907.968 0.084 907.992 ;
    END
  END t_out[38]
  PIN t_out[390]
    DIRECTION OUTPUT ;
    USE SIGNAL ;
    PORT
      LAYER M4 ;
        RECT  0 976.32 0.084 976.344 ;
    END
  END t_out[390]
  PIN t_out[391]
    DIRECTION OUTPUT ;
    USE SIGNAL ;
    PORT
      LAYER M4 ;
        RECT  0 976.512 0.084 976.536 ;
    END
  END t_out[391]
  PIN t_out[392]
    DIRECTION OUTPUT ;
    USE SIGNAL ;
    PORT
      LAYER M4 ;
        RECT  0 976.704 0.084 976.728 ;
    END
  END t_out[392]
  PIN t_out[393]
    DIRECTION OUTPUT ;
    USE SIGNAL ;
    PORT
      LAYER M4 ;
        RECT  0 976.896 0.084 976.92 ;
    END
  END t_out[393]
  PIN t_out[394]
    DIRECTION OUTPUT ;
    USE SIGNAL ;
    PORT
      LAYER M4 ;
        RECT  0 977.088 0.084 977.112 ;
    END
  END t_out[394]
  PIN t_out[395]
    DIRECTION OUTPUT ;
    USE SIGNAL ;
    PORT
      LAYER M4 ;
        RECT  0 977.28 0.084 977.304 ;
    END
  END t_out[395]
  PIN t_out[396]
    DIRECTION OUTPUT ;
    USE SIGNAL ;
    PORT
      LAYER M4 ;
        RECT  0 977.472 0.084 977.496 ;
    END
  END t_out[396]
  PIN t_out[397]
    DIRECTION OUTPUT ;
    USE SIGNAL ;
    PORT
      LAYER M4 ;
        RECT  0 977.664 0.084 977.688 ;
    END
  END t_out[397]
  PIN t_out[398]
    DIRECTION OUTPUT ;
    USE SIGNAL ;
    PORT
      LAYER M4 ;
        RECT  0 977.856 0.084 977.88 ;
    END
  END t_out[398]
  PIN t_out[399]
    DIRECTION OUTPUT ;
    USE SIGNAL ;
    PORT
      LAYER M4 ;
        RECT  0 978.048 0.084 978.072 ;
    END
  END t_out[399]
  PIN t_out[39]
    DIRECTION OUTPUT ;
    USE SIGNAL ;
    PORT
      LAYER M4 ;
        RECT  0 908.16 0.084 908.184 ;
    END
  END t_out[39]
  PIN t_out[3]
    DIRECTION OUTPUT ;
    USE SIGNAL ;
    PORT
      LAYER M4 ;
        RECT  0 901.248 0.084 901.272 ;
    END
  END t_out[3]
  PIN t_out[400]
    DIRECTION OUTPUT ;
    USE SIGNAL ;
    PORT
      LAYER M4 ;
        RECT  0 978.24 0.084 978.264 ;
    END
  END t_out[400]
  PIN t_out[401]
    DIRECTION OUTPUT ;
    USE SIGNAL ;
    PORT
      LAYER M4 ;
        RECT  0 978.432 0.084 978.456 ;
    END
  END t_out[401]
  PIN t_out[402]
    DIRECTION OUTPUT ;
    USE SIGNAL ;
    PORT
      LAYER M4 ;
        RECT  0 978.624 0.084 978.648 ;
    END
  END t_out[402]
  PIN t_out[403]
    DIRECTION OUTPUT ;
    USE SIGNAL ;
    PORT
      LAYER M4 ;
        RECT  0 978.816 0.084 978.84 ;
    END
  END t_out[403]
  PIN t_out[404]
    DIRECTION OUTPUT ;
    USE SIGNAL ;
    PORT
      LAYER M4 ;
        RECT  0 979.008 0.084 979.032 ;
    END
  END t_out[404]
  PIN t_out[405]
    DIRECTION OUTPUT ;
    USE SIGNAL ;
    PORT
      LAYER M4 ;
        RECT  0 979.2 0.084 979.224 ;
    END
  END t_out[405]
  PIN t_out[406]
    DIRECTION OUTPUT ;
    USE SIGNAL ;
    PORT
      LAYER M4 ;
        RECT  0 979.392 0.084 979.416 ;
    END
  END t_out[406]
  PIN t_out[407]
    DIRECTION OUTPUT ;
    USE SIGNAL ;
    PORT
      LAYER M4 ;
        RECT  0 979.584 0.084 979.608 ;
    END
  END t_out[407]
  PIN t_out[408]
    DIRECTION OUTPUT ;
    USE SIGNAL ;
    PORT
      LAYER M4 ;
        RECT  0 979.776 0.084 979.8 ;
    END
  END t_out[408]
  PIN t_out[409]
    DIRECTION OUTPUT ;
    USE SIGNAL ;
    PORT
      LAYER M4 ;
        RECT  0 979.968 0.084 979.992 ;
    END
  END t_out[409]
  PIN t_out[40]
    DIRECTION OUTPUT ;
    USE SIGNAL ;
    PORT
      LAYER M4 ;
        RECT  0 908.352 0.084 908.376 ;
    END
  END t_out[40]
  PIN t_out[410]
    DIRECTION OUTPUT ;
    USE SIGNAL ;
    PORT
      LAYER M4 ;
        RECT  0 980.16 0.084 980.184 ;
    END
  END t_out[410]
  PIN t_out[411]
    DIRECTION OUTPUT ;
    USE SIGNAL ;
    PORT
      LAYER M4 ;
        RECT  0 980.352 0.084 980.376 ;
    END
  END t_out[411]
  PIN t_out[412]
    DIRECTION OUTPUT ;
    USE SIGNAL ;
    PORT
      LAYER M4 ;
        RECT  0 980.544 0.084 980.568 ;
    END
  END t_out[412]
  PIN t_out[413]
    DIRECTION OUTPUT ;
    USE SIGNAL ;
    PORT
      LAYER M4 ;
        RECT  0 980.736 0.084 980.76 ;
    END
  END t_out[413]
  PIN t_out[414]
    DIRECTION OUTPUT ;
    USE SIGNAL ;
    PORT
      LAYER M4 ;
        RECT  0 980.928 0.084 980.952 ;
    END
  END t_out[414]
  PIN t_out[415]
    DIRECTION OUTPUT ;
    USE SIGNAL ;
    PORT
      LAYER M4 ;
        RECT  0 981.12 0.084 981.144 ;
    END
  END t_out[415]
  PIN t_out[416]
    DIRECTION OUTPUT ;
    USE SIGNAL ;
    PORT
      LAYER M4 ;
        RECT  0 981.312 0.084 981.336 ;
    END
  END t_out[416]
  PIN t_out[417]
    DIRECTION OUTPUT ;
    USE SIGNAL ;
    PORT
      LAYER M4 ;
        RECT  0 981.504 0.084 981.528 ;
    END
  END t_out[417]
  PIN t_out[418]
    DIRECTION OUTPUT ;
    USE SIGNAL ;
    PORT
      LAYER M4 ;
        RECT  0 981.696 0.084 981.72 ;
    END
  END t_out[418]
  PIN t_out[419]
    DIRECTION OUTPUT ;
    USE SIGNAL ;
    PORT
      LAYER M4 ;
        RECT  0 981.888 0.084 981.912 ;
    END
  END t_out[419]
  PIN t_out[41]
    DIRECTION OUTPUT ;
    USE SIGNAL ;
    PORT
      LAYER M4 ;
        RECT  0 908.544 0.084 908.568 ;
    END
  END t_out[41]
  PIN t_out[420]
    DIRECTION OUTPUT ;
    USE SIGNAL ;
    PORT
      LAYER M4 ;
        RECT  0 982.08 0.084 982.104 ;
    END
  END t_out[420]
  PIN t_out[421]
    DIRECTION OUTPUT ;
    USE SIGNAL ;
    PORT
      LAYER M4 ;
        RECT  0 982.272 0.084 982.296 ;
    END
  END t_out[421]
  PIN t_out[422]
    DIRECTION OUTPUT ;
    USE SIGNAL ;
    PORT
      LAYER M4 ;
        RECT  0 982.464 0.084 982.488 ;
    END
  END t_out[422]
  PIN t_out[423]
    DIRECTION OUTPUT ;
    USE SIGNAL ;
    PORT
      LAYER M4 ;
        RECT  0 982.656 0.084 982.68 ;
    END
  END t_out[423]
  PIN t_out[424]
    DIRECTION OUTPUT ;
    USE SIGNAL ;
    PORT
      LAYER M4 ;
        RECT  0 982.848 0.084 982.872 ;
    END
  END t_out[424]
  PIN t_out[425]
    DIRECTION OUTPUT ;
    USE SIGNAL ;
    PORT
      LAYER M4 ;
        RECT  0 983.04 0.084 983.064 ;
    END
  END t_out[425]
  PIN t_out[426]
    DIRECTION OUTPUT ;
    USE SIGNAL ;
    PORT
      LAYER M4 ;
        RECT  0 983.232 0.084 983.256 ;
    END
  END t_out[426]
  PIN t_out[427]
    DIRECTION OUTPUT ;
    USE SIGNAL ;
    PORT
      LAYER M4 ;
        RECT  0 983.424 0.084 983.448 ;
    END
  END t_out[427]
  PIN t_out[428]
    DIRECTION OUTPUT ;
    USE SIGNAL ;
    PORT
      LAYER M4 ;
        RECT  0 983.616 0.084 983.64 ;
    END
  END t_out[428]
  PIN t_out[429]
    DIRECTION OUTPUT ;
    USE SIGNAL ;
    PORT
      LAYER M4 ;
        RECT  0 983.808 0.084 983.832 ;
    END
  END t_out[429]
  PIN t_out[42]
    DIRECTION OUTPUT ;
    USE SIGNAL ;
    PORT
      LAYER M4 ;
        RECT  0 908.736 0.084 908.76 ;
    END
  END t_out[42]
  PIN t_out[430]
    DIRECTION OUTPUT ;
    USE SIGNAL ;
    PORT
      LAYER M4 ;
        RECT  0 984 0.084 984.024 ;
    END
  END t_out[430]
  PIN t_out[431]
    DIRECTION OUTPUT ;
    USE SIGNAL ;
    PORT
      LAYER M4 ;
        RECT  0 984.192 0.084 984.216 ;
    END
  END t_out[431]
  PIN t_out[432]
    DIRECTION OUTPUT ;
    USE SIGNAL ;
    PORT
      LAYER M4 ;
        RECT  0 984.384 0.084 984.408 ;
    END
  END t_out[432]
  PIN t_out[433]
    DIRECTION OUTPUT ;
    USE SIGNAL ;
    PORT
      LAYER M4 ;
        RECT  0 984.576 0.084 984.6 ;
    END
  END t_out[433]
  PIN t_out[434]
    DIRECTION OUTPUT ;
    USE SIGNAL ;
    PORT
      LAYER M4 ;
        RECT  0 984.768 0.084 984.792 ;
    END
  END t_out[434]
  PIN t_out[435]
    DIRECTION OUTPUT ;
    USE SIGNAL ;
    PORT
      LAYER M4 ;
        RECT  0 984.96 0.084 984.984 ;
    END
  END t_out[435]
  PIN t_out[436]
    DIRECTION OUTPUT ;
    USE SIGNAL ;
    PORT
      LAYER M4 ;
        RECT  0 985.152 0.084 985.176 ;
    END
  END t_out[436]
  PIN t_out[437]
    DIRECTION OUTPUT ;
    USE SIGNAL ;
    PORT
      LAYER M4 ;
        RECT  0 985.344 0.084 985.368 ;
    END
  END t_out[437]
  PIN t_out[438]
    DIRECTION OUTPUT ;
    USE SIGNAL ;
    PORT
      LAYER M4 ;
        RECT  0 985.536 0.084 985.56 ;
    END
  END t_out[438]
  PIN t_out[439]
    DIRECTION OUTPUT ;
    USE SIGNAL ;
    PORT
      LAYER M4 ;
        RECT  0 985.728 0.084 985.752 ;
    END
  END t_out[439]
  PIN t_out[43]
    DIRECTION OUTPUT ;
    USE SIGNAL ;
    PORT
      LAYER M4 ;
        RECT  0 908.928 0.084 908.952 ;
    END
  END t_out[43]
  PIN t_out[440]
    DIRECTION OUTPUT ;
    USE SIGNAL ;
    PORT
      LAYER M4 ;
        RECT  0 985.92 0.084 985.944 ;
    END
  END t_out[440]
  PIN t_out[441]
    DIRECTION OUTPUT ;
    USE SIGNAL ;
    PORT
      LAYER M4 ;
        RECT  0 986.112 0.084 986.136 ;
    END
  END t_out[441]
  PIN t_out[442]
    DIRECTION OUTPUT ;
    USE SIGNAL ;
    PORT
      LAYER M4 ;
        RECT  0 986.304 0.084 986.328 ;
    END
  END t_out[442]
  PIN t_out[443]
    DIRECTION OUTPUT ;
    USE SIGNAL ;
    PORT
      LAYER M4 ;
        RECT  0 986.496 0.084 986.52 ;
    END
  END t_out[443]
  PIN t_out[444]
    DIRECTION OUTPUT ;
    USE SIGNAL ;
    PORT
      LAYER M4 ;
        RECT  0 986.688 0.084 986.712 ;
    END
  END t_out[444]
  PIN t_out[445]
    DIRECTION OUTPUT ;
    USE SIGNAL ;
    PORT
      LAYER M4 ;
        RECT  0 986.88 0.084 986.904 ;
    END
  END t_out[445]
  PIN t_out[446]
    DIRECTION OUTPUT ;
    USE SIGNAL ;
    PORT
      LAYER M4 ;
        RECT  0 987.072 0.084 987.096 ;
    END
  END t_out[446]
  PIN t_out[447]
    DIRECTION OUTPUT ;
    USE SIGNAL ;
    PORT
      LAYER M4 ;
        RECT  0 987.264 0.084 987.288 ;
    END
  END t_out[447]
  PIN t_out[448]
    DIRECTION OUTPUT ;
    USE SIGNAL ;
    PORT
      LAYER M4 ;
        RECT  0 987.456 0.084 987.48 ;
    END
  END t_out[448]
  PIN t_out[449]
    DIRECTION OUTPUT ;
    USE SIGNAL ;
    PORT
      LAYER M4 ;
        RECT  0 987.648 0.084 987.672 ;
    END
  END t_out[449]
  PIN t_out[44]
    DIRECTION OUTPUT ;
    USE SIGNAL ;
    PORT
      LAYER M4 ;
        RECT  0 909.888 0.084 909.912 ;
    END
  END t_out[44]
  PIN t_out[450]
    DIRECTION OUTPUT ;
    USE SIGNAL ;
    PORT
      LAYER M4 ;
        RECT  0 987.84 0.084 987.864 ;
    END
  END t_out[450]
  PIN t_out[451]
    DIRECTION OUTPUT ;
    USE SIGNAL ;
    PORT
      LAYER M4 ;
        RECT  0 988.032 0.084 988.056 ;
    END
  END t_out[451]
  PIN t_out[452]
    DIRECTION OUTPUT ;
    USE SIGNAL ;
    PORT
      LAYER M4 ;
        RECT  0 988.224 0.084 988.248 ;
    END
  END t_out[452]
  PIN t_out[453]
    DIRECTION OUTPUT ;
    USE SIGNAL ;
    PORT
      LAYER M4 ;
        RECT  0 988.416 0.084 988.44 ;
    END
  END t_out[453]
  PIN t_out[454]
    DIRECTION OUTPUT ;
    USE SIGNAL ;
    PORT
      LAYER M4 ;
        RECT  0 988.608 0.084 988.632 ;
    END
  END t_out[454]
  PIN t_out[455]
    DIRECTION OUTPUT ;
    USE SIGNAL ;
    PORT
      LAYER M4 ;
        RECT  0 988.8 0.084 988.824 ;
    END
  END t_out[455]
  PIN t_out[456]
    DIRECTION OUTPUT ;
    USE SIGNAL ;
    PORT
      LAYER M4 ;
        RECT  0 988.992 0.084 989.016 ;
    END
  END t_out[456]
  PIN t_out[457]
    DIRECTION OUTPUT ;
    USE SIGNAL ;
    PORT
      LAYER M4 ;
        RECT  0 989.184 0.084 989.208 ;
    END
  END t_out[457]
  PIN t_out[458]
    DIRECTION OUTPUT ;
    USE SIGNAL ;
    PORT
      LAYER M4 ;
        RECT  0 989.376 0.084 989.4 ;
    END
  END t_out[458]
  PIN t_out[459]
    DIRECTION OUTPUT ;
    USE SIGNAL ;
    PORT
      LAYER M4 ;
        RECT  0 989.568 0.084 989.592 ;
    END
  END t_out[459]
  PIN t_out[45]
    DIRECTION OUTPUT ;
    USE SIGNAL ;
    PORT
      LAYER M4 ;
        RECT  0 910.08 0.084 910.104 ;
    END
  END t_out[45]
  PIN t_out[460]
    DIRECTION OUTPUT ;
    USE SIGNAL ;
    PORT
      LAYER M4 ;
        RECT  0 989.76 0.084 989.784 ;
    END
  END t_out[460]
  PIN t_out[461]
    DIRECTION OUTPUT ;
    USE SIGNAL ;
    PORT
      LAYER M4 ;
        RECT  0 989.952 0.084 989.976 ;
    END
  END t_out[461]
  PIN t_out[462]
    DIRECTION OUTPUT ;
    USE SIGNAL ;
    PORT
      LAYER M4 ;
        RECT  0 990.144 0.084 990.168 ;
    END
  END t_out[462]
  PIN t_out[463]
    DIRECTION OUTPUT ;
    USE SIGNAL ;
    PORT
      LAYER M4 ;
        RECT  0 990.336 0.084 990.36 ;
    END
  END t_out[463]
  PIN t_out[464]
    DIRECTION OUTPUT ;
    USE SIGNAL ;
    PORT
      LAYER M4 ;
        RECT  0 990.528 0.084 990.552 ;
    END
  END t_out[464]
  PIN t_out[465]
    DIRECTION OUTPUT ;
    USE SIGNAL ;
    PORT
      LAYER M4 ;
        RECT  0 990.72 0.084 990.744 ;
    END
  END t_out[465]
  PIN t_out[466]
    DIRECTION OUTPUT ;
    USE SIGNAL ;
    PORT
      LAYER M4 ;
        RECT  0 990.912 0.084 990.936 ;
    END
  END t_out[466]
  PIN t_out[467]
    DIRECTION OUTPUT ;
    USE SIGNAL ;
    PORT
      LAYER M4 ;
        RECT  0 991.104 0.084 991.128 ;
    END
  END t_out[467]
  PIN t_out[468]
    DIRECTION OUTPUT ;
    USE SIGNAL ;
    PORT
      LAYER M4 ;
        RECT  0 991.296 0.084 991.32 ;
    END
  END t_out[468]
  PIN t_out[469]
    DIRECTION OUTPUT ;
    USE SIGNAL ;
    PORT
      LAYER M4 ;
        RECT  0 991.488 0.084 991.512 ;
    END
  END t_out[469]
  PIN t_out[46]
    DIRECTION OUTPUT ;
    USE SIGNAL ;
    PORT
      LAYER M4 ;
        RECT  0 910.272 0.084 910.296 ;
    END
  END t_out[46]
  PIN t_out[470]
    DIRECTION OUTPUT ;
    USE SIGNAL ;
    PORT
      LAYER M4 ;
        RECT  0 991.68 0.084 991.704 ;
    END
  END t_out[470]
  PIN t_out[471]
    DIRECTION OUTPUT ;
    USE SIGNAL ;
    PORT
      LAYER M4 ;
        RECT  0 991.872 0.084 991.896 ;
    END
  END t_out[471]
  PIN t_out[472]
    DIRECTION OUTPUT ;
    USE SIGNAL ;
    PORT
      LAYER M4 ;
        RECT  0 992.064 0.084 992.088 ;
    END
  END t_out[472]
  PIN t_out[473]
    DIRECTION OUTPUT ;
    USE SIGNAL ;
    PORT
      LAYER M4 ;
        RECT  0 992.256 0.084 992.28 ;
    END
  END t_out[473]
  PIN t_out[474]
    DIRECTION OUTPUT ;
    USE SIGNAL ;
    PORT
      LAYER M4 ;
        RECT  0 992.448 0.084 992.472 ;
    END
  END t_out[474]
  PIN t_out[475]
    DIRECTION OUTPUT ;
    USE SIGNAL ;
    PORT
      LAYER M4 ;
        RECT  0 992.64 0.084 992.664 ;
    END
  END t_out[475]
  PIN t_out[476]
    DIRECTION OUTPUT ;
    USE SIGNAL ;
    PORT
      LAYER M4 ;
        RECT  0 992.832 0.084 992.856 ;
    END
  END t_out[476]
  PIN t_out[477]
    DIRECTION OUTPUT ;
    USE SIGNAL ;
    PORT
      LAYER M4 ;
        RECT  0 993.024 0.084 993.048 ;
    END
  END t_out[477]
  PIN t_out[478]
    DIRECTION OUTPUT ;
    USE SIGNAL ;
    PORT
      LAYER M4 ;
        RECT  0 993.216 0.084 993.24 ;
    END
  END t_out[478]
  PIN t_out[479]
    DIRECTION OUTPUT ;
    USE SIGNAL ;
    PORT
      LAYER M4 ;
        RECT  0 993.408 0.084 993.432 ;
    END
  END t_out[479]
  PIN t_out[47]
    DIRECTION OUTPUT ;
    USE SIGNAL ;
    PORT
      LAYER M4 ;
        RECT  0 910.464 0.084 910.488 ;
    END
  END t_out[47]
  PIN t_out[480]
    DIRECTION OUTPUT ;
    USE SIGNAL ;
    PORT
      LAYER M4 ;
        RECT  0 993.6 0.084 993.624 ;
    END
  END t_out[480]
  PIN t_out[481]
    DIRECTION OUTPUT ;
    USE SIGNAL ;
    PORT
      LAYER M4 ;
        RECT  0 993.792 0.084 993.816 ;
    END
  END t_out[481]
  PIN t_out[482]
    DIRECTION OUTPUT ;
    USE SIGNAL ;
    PORT
      LAYER M4 ;
        RECT  0 993.984 0.084 994.008 ;
    END
  END t_out[482]
  PIN t_out[483]
    DIRECTION OUTPUT ;
    USE SIGNAL ;
    PORT
      LAYER M4 ;
        RECT  0 994.176 0.084 994.2 ;
    END
  END t_out[483]
  PIN t_out[484]
    DIRECTION OUTPUT ;
    USE SIGNAL ;
    PORT
      LAYER M4 ;
        RECT  0 994.368 0.084 994.392 ;
    END
  END t_out[484]
  PIN t_out[485]
    DIRECTION OUTPUT ;
    USE SIGNAL ;
    PORT
      LAYER M4 ;
        RECT  0 994.56 0.084 994.584 ;
    END
  END t_out[485]
  PIN t_out[486]
    DIRECTION OUTPUT ;
    USE SIGNAL ;
    PORT
      LAYER M4 ;
        RECT  0 994.752 0.084 994.776 ;
    END
  END t_out[486]
  PIN t_out[487]
    DIRECTION OUTPUT ;
    USE SIGNAL ;
    PORT
      LAYER M4 ;
        RECT  0 994.944 0.084 994.968 ;
    END
  END t_out[487]
  PIN t_out[488]
    DIRECTION OUTPUT ;
    USE SIGNAL ;
    PORT
      LAYER M4 ;
        RECT  0 995.136 0.084 995.16 ;
    END
  END t_out[488]
  PIN t_out[489]
    DIRECTION OUTPUT ;
    USE SIGNAL ;
    PORT
      LAYER M4 ;
        RECT  0 995.328 0.084 995.352 ;
    END
  END t_out[489]
  PIN t_out[48]
    DIRECTION OUTPUT ;
    USE SIGNAL ;
    PORT
      LAYER M4 ;
        RECT  0 910.656 0.084 910.68 ;
    END
  END t_out[48]
  PIN t_out[490]
    DIRECTION OUTPUT ;
    USE SIGNAL ;
    PORT
      LAYER M4 ;
        RECT  0 995.52 0.084 995.544 ;
    END
  END t_out[490]
  PIN t_out[491]
    DIRECTION OUTPUT ;
    USE SIGNAL ;
    PORT
      LAYER M4 ;
        RECT  0 995.712 0.084 995.736 ;
    END
  END t_out[491]
  PIN t_out[492]
    DIRECTION OUTPUT ;
    USE SIGNAL ;
    PORT
      LAYER M4 ;
        RECT  0 995.904 0.084 995.928 ;
    END
  END t_out[492]
  PIN t_out[493]
    DIRECTION OUTPUT ;
    USE SIGNAL ;
    PORT
      LAYER M4 ;
        RECT  0 996.096 0.084 996.12 ;
    END
  END t_out[493]
  PIN t_out[494]
    DIRECTION OUTPUT ;
    USE SIGNAL ;
    PORT
      LAYER M4 ;
        RECT  0 996.288 0.084 996.312 ;
    END
  END t_out[494]
  PIN t_out[495]
    DIRECTION OUTPUT ;
    USE SIGNAL ;
    PORT
      LAYER M4 ;
        RECT  0 996.48 0.084 996.504 ;
    END
  END t_out[495]
  PIN t_out[496]
    DIRECTION OUTPUT ;
    USE SIGNAL ;
    PORT
      LAYER M4 ;
        RECT  0 996.672 0.084 996.696 ;
    END
  END t_out[496]
  PIN t_out[497]
    DIRECTION OUTPUT ;
    USE SIGNAL ;
    PORT
      LAYER M4 ;
        RECT  0 996.864 0.084 996.888 ;
    END
  END t_out[497]
  PIN t_out[498]
    DIRECTION OUTPUT ;
    USE SIGNAL ;
    PORT
      LAYER M4 ;
        RECT  0 997.056 0.084 997.08 ;
    END
  END t_out[498]
  PIN t_out[499]
    DIRECTION OUTPUT ;
    USE SIGNAL ;
    PORT
      LAYER M4 ;
        RECT  0 997.248 0.084 997.272 ;
    END
  END t_out[499]
  PIN t_out[49]
    DIRECTION OUTPUT ;
    USE SIGNAL ;
    PORT
      LAYER M4 ;
        RECT  0 910.848 0.084 910.872 ;
    END
  END t_out[49]
  PIN t_out[4]
    DIRECTION OUTPUT ;
    USE SIGNAL ;
    PORT
      LAYER M4 ;
        RECT  0 901.44 0.084 901.464 ;
    END
  END t_out[4]
  PIN t_out[500]
    DIRECTION OUTPUT ;
    USE SIGNAL ;
    PORT
      LAYER M4 ;
        RECT  0 997.44 0.084 997.464 ;
    END
  END t_out[500]
  PIN t_out[501]
    DIRECTION OUTPUT ;
    USE SIGNAL ;
    PORT
      LAYER M4 ;
        RECT  0 997.632 0.084 997.656 ;
    END
  END t_out[501]
  PIN t_out[502]
    DIRECTION OUTPUT ;
    USE SIGNAL ;
    PORT
      LAYER M4 ;
        RECT  0 997.824 0.084 997.848 ;
    END
  END t_out[502]
  PIN t_out[503]
    DIRECTION OUTPUT ;
    USE SIGNAL ;
    PORT
      LAYER M4 ;
        RECT  0 998.016 0.084 998.04 ;
    END
  END t_out[503]
  PIN t_out[504]
    DIRECTION OUTPUT ;
    USE SIGNAL ;
    PORT
      LAYER M4 ;
        RECT  0 998.208 0.084 998.232 ;
    END
  END t_out[504]
  PIN t_out[505]
    DIRECTION OUTPUT ;
    USE SIGNAL ;
    PORT
      LAYER M4 ;
        RECT  0 998.4 0.084 998.424 ;
    END
  END t_out[505]
  PIN t_out[506]
    DIRECTION OUTPUT ;
    USE SIGNAL ;
    PORT
      LAYER M4 ;
        RECT  0 998.592 0.084 998.616 ;
    END
  END t_out[506]
  PIN t_out[507]
    DIRECTION OUTPUT ;
    USE SIGNAL ;
    PORT
      LAYER M4 ;
        RECT  0 998.784 0.084 998.808 ;
    END
  END t_out[507]
  PIN t_out[508]
    DIRECTION OUTPUT ;
    USE SIGNAL ;
    PORT
      LAYER M4 ;
        RECT  0 998.976 0.084 999 ;
    END
  END t_out[508]
  PIN t_out[509]
    DIRECTION OUTPUT ;
    USE SIGNAL ;
    PORT
      LAYER M4 ;
        RECT  0 999.168 0.084 999.192 ;
    END
  END t_out[509]
  PIN t_out[50]
    DIRECTION OUTPUT ;
    USE SIGNAL ;
    PORT
      LAYER M4 ;
        RECT  0 911.04 0.084 911.064 ;
    END
  END t_out[50]
  PIN t_out[510]
    DIRECTION OUTPUT ;
    USE SIGNAL ;
    PORT
      LAYER M4 ;
        RECT  0 999.36 0.084 999.384 ;
    END
  END t_out[510]
  PIN t_out[511]
    DIRECTION OUTPUT ;
    USE SIGNAL ;
    PORT
      LAYER M4 ;
        RECT  0 999.552 0.084 999.576 ;
    END
  END t_out[511]
  PIN t_out[512]
    DIRECTION OUTPUT ;
    USE SIGNAL ;
    PORT
      LAYER M4 ;
        RECT  0 999.744 0.084 999.768 ;
    END
  END t_out[512]
  PIN t_out[513]
    DIRECTION OUTPUT ;
    USE SIGNAL ;
    PORT
      LAYER M4 ;
        RECT  0 999.936 0.084 999.96 ;
    END
  END t_out[513]
  PIN t_out[51]
    DIRECTION OUTPUT ;
    USE SIGNAL ;
    PORT
      LAYER M4 ;
        RECT  0 911.232 0.084 911.256 ;
    END
  END t_out[51]
  PIN t_out[52]
    DIRECTION OUTPUT ;
    USE SIGNAL ;
    PORT
      LAYER M4 ;
        RECT  0 911.424 0.084 911.448 ;
    END
  END t_out[52]
  PIN t_out[53]
    DIRECTION OUTPUT ;
    USE SIGNAL ;
    PORT
      LAYER M4 ;
        RECT  0 911.616 0.084 911.64 ;
    END
  END t_out[53]
  PIN t_out[54]
    DIRECTION OUTPUT ;
    USE SIGNAL ;
    PORT
      LAYER M4 ;
        RECT  0 911.808 0.084 911.832 ;
    END
  END t_out[54]
  PIN t_out[55]
    DIRECTION OUTPUT ;
    USE SIGNAL ;
    PORT
      LAYER M4 ;
        RECT  0 912 0.084 912.024 ;
    END
  END t_out[55]
  PIN t_out[56]
    DIRECTION OUTPUT ;
    USE SIGNAL ;
    PORT
      LAYER M4 ;
        RECT  0 912.192 0.084 912.216 ;
    END
  END t_out[56]
  PIN t_out[57]
    DIRECTION OUTPUT ;
    USE SIGNAL ;
    PORT
      LAYER M4 ;
        RECT  0 912.384 0.084 912.408 ;
    END
  END t_out[57]
  PIN t_out[58]
    DIRECTION OUTPUT ;
    USE SIGNAL ;
    PORT
      LAYER M4 ;
        RECT  0 912.576 0.084 912.6 ;
    END
  END t_out[58]
  PIN t_out[59]
    DIRECTION OUTPUT ;
    USE SIGNAL ;
    PORT
      LAYER M4 ;
        RECT  0 912.768 0.084 912.792 ;
    END
  END t_out[59]
  PIN t_out[5]
    DIRECTION OUTPUT ;
    USE SIGNAL ;
    PORT
      LAYER M4 ;
        RECT  0 901.632 0.084 901.656 ;
    END
  END t_out[5]
  PIN t_out[60]
    DIRECTION OUTPUT ;
    USE SIGNAL ;
    PORT
      LAYER M4 ;
        RECT  0 912.96 0.084 912.984 ;
    END
  END t_out[60]
  PIN t_out[61]
    DIRECTION OUTPUT ;
    USE SIGNAL ;
    PORT
      LAYER M4 ;
        RECT  0 913.152 0.084 913.176 ;
    END
  END t_out[61]
  PIN t_out[62]
    DIRECTION OUTPUT ;
    USE SIGNAL ;
    PORT
      LAYER M4 ;
        RECT  0 913.344 0.084 913.368 ;
    END
  END t_out[62]
  PIN t_out[63]
    DIRECTION OUTPUT ;
    USE SIGNAL ;
    PORT
      LAYER M4 ;
        RECT  0 913.536 0.084 913.56 ;
    END
  END t_out[63]
  PIN t_out[64]
    DIRECTION OUTPUT ;
    USE SIGNAL ;
    PORT
      LAYER M4 ;
        RECT  0 913.728 0.084 913.752 ;
    END
  END t_out[64]
  PIN t_out[65]
    DIRECTION OUTPUT ;
    USE SIGNAL ;
    PORT
      LAYER M4 ;
        RECT  0 913.92 0.084 913.944 ;
    END
  END t_out[65]
  PIN t_out[66]
    DIRECTION OUTPUT ;
    USE SIGNAL ;
    PORT
      LAYER M4 ;
        RECT  0 914.112 0.084 914.136 ;
    END
  END t_out[66]
  PIN t_out[67]
    DIRECTION OUTPUT ;
    USE SIGNAL ;
    PORT
      LAYER M4 ;
        RECT  0 914.304 0.084 914.328 ;
    END
  END t_out[67]
  PIN t_out[68]
    DIRECTION OUTPUT ;
    USE SIGNAL ;
    PORT
      LAYER M4 ;
        RECT  0 914.496 0.084 914.52 ;
    END
  END t_out[68]
  PIN t_out[69]
    DIRECTION OUTPUT ;
    USE SIGNAL ;
    PORT
      LAYER M4 ;
        RECT  0 914.688 0.084 914.712 ;
    END
  END t_out[69]
  PIN t_out[6]
    DIRECTION OUTPUT ;
    USE SIGNAL ;
    PORT
      LAYER M4 ;
        RECT  0 901.824 0.084 901.848 ;
    END
  END t_out[6]
  PIN t_out[70]
    DIRECTION OUTPUT ;
    USE SIGNAL ;
    PORT
      LAYER M4 ;
        RECT  0 914.88 0.084 914.904 ;
    END
  END t_out[70]
  PIN t_out[71]
    DIRECTION OUTPUT ;
    USE SIGNAL ;
    PORT
      LAYER M4 ;
        RECT  0 915.072 0.084 915.096 ;
    END
  END t_out[71]
  PIN t_out[72]
    DIRECTION OUTPUT ;
    USE SIGNAL ;
    PORT
      LAYER M4 ;
        RECT  0 915.264 0.084 915.288 ;
    END
  END t_out[72]
  PIN t_out[73]
    DIRECTION OUTPUT ;
    USE SIGNAL ;
    PORT
      LAYER M4 ;
        RECT  0 915.456 0.084 915.48 ;
    END
  END t_out[73]
  PIN t_out[74]
    DIRECTION OUTPUT ;
    USE SIGNAL ;
    PORT
      LAYER M4 ;
        RECT  0 915.648 0.084 915.672 ;
    END
  END t_out[74]
  PIN t_out[75]
    DIRECTION OUTPUT ;
    USE SIGNAL ;
    PORT
      LAYER M4 ;
        RECT  0 915.84 0.084 915.864 ;
    END
  END t_out[75]
  PIN t_out[76]
    DIRECTION OUTPUT ;
    USE SIGNAL ;
    PORT
      LAYER M4 ;
        RECT  0 916.032 0.084 916.056 ;
    END
  END t_out[76]
  PIN t_out[77]
    DIRECTION OUTPUT ;
    USE SIGNAL ;
    PORT
      LAYER M4 ;
        RECT  0 916.224 0.084 916.248 ;
    END
  END t_out[77]
  PIN t_out[78]
    DIRECTION OUTPUT ;
    USE SIGNAL ;
    PORT
      LAYER M4 ;
        RECT  0 916.416 0.084 916.44 ;
    END
  END t_out[78]
  PIN t_out[79]
    DIRECTION OUTPUT ;
    USE SIGNAL ;
    PORT
      LAYER M4 ;
        RECT  0 916.608 0.084 916.632 ;
    END
  END t_out[79]
  PIN t_out[7]
    DIRECTION OUTPUT ;
    USE SIGNAL ;
    PORT
      LAYER M4 ;
        RECT  0 902.016 0.084 902.04 ;
    END
  END t_out[7]
  PIN t_out[80]
    DIRECTION OUTPUT ;
    USE SIGNAL ;
    PORT
      LAYER M4 ;
        RECT  0 916.8 0.084 916.824 ;
    END
  END t_out[80]
  PIN t_out[81]
    DIRECTION OUTPUT ;
    USE SIGNAL ;
    PORT
      LAYER M4 ;
        RECT  0 916.992 0.084 917.016 ;
    END
  END t_out[81]
  PIN t_out[82]
    DIRECTION OUTPUT ;
    USE SIGNAL ;
    PORT
      LAYER M4 ;
        RECT  0 917.184 0.084 917.208 ;
    END
  END t_out[82]
  PIN t_out[83]
    DIRECTION OUTPUT ;
    USE SIGNAL ;
    PORT
      LAYER M4 ;
        RECT  0 917.376 0.084 917.4 ;
    END
  END t_out[83]
  PIN t_out[84]
    DIRECTION OUTPUT ;
    USE SIGNAL ;
    PORT
      LAYER M4 ;
        RECT  0 917.568 0.084 917.592 ;
    END
  END t_out[84]
  PIN t_out[85]
    DIRECTION OUTPUT ;
    USE SIGNAL ;
    PORT
      LAYER M4 ;
        RECT  0 917.76 0.084 917.784 ;
    END
  END t_out[85]
  PIN t_out[86]
    DIRECTION OUTPUT ;
    USE SIGNAL ;
    PORT
      LAYER M4 ;
        RECT  0 917.952 0.084 917.976 ;
    END
  END t_out[86]
  PIN t_out[87]
    DIRECTION OUTPUT ;
    USE SIGNAL ;
    PORT
      LAYER M4 ;
        RECT  0 918.144 0.084 918.168 ;
    END
  END t_out[87]
  PIN t_out[88]
    DIRECTION OUTPUT ;
    USE SIGNAL ;
    PORT
      LAYER M4 ;
        RECT  0 918.336 0.084 918.36 ;
    END
  END t_out[88]
  PIN t_out[89]
    DIRECTION OUTPUT ;
    USE SIGNAL ;
    PORT
      LAYER M4 ;
        RECT  0 918.528 0.084 918.552 ;
    END
  END t_out[89]
  PIN t_out[8]
    DIRECTION OUTPUT ;
    USE SIGNAL ;
    PORT
      LAYER M4 ;
        RECT  0 902.208 0.084 902.232 ;
    END
  END t_out[8]
  PIN t_out[90]
    DIRECTION OUTPUT ;
    USE SIGNAL ;
    PORT
      LAYER M4 ;
        RECT  0 918.72 0.084 918.744 ;
    END
  END t_out[90]
  PIN t_out[91]
    DIRECTION OUTPUT ;
    USE SIGNAL ;
    PORT
      LAYER M4 ;
        RECT  0 918.912 0.084 918.936 ;
    END
  END t_out[91]
  PIN t_out[92]
    DIRECTION OUTPUT ;
    USE SIGNAL ;
    PORT
      LAYER M4 ;
        RECT  0 919.104 0.084 919.128 ;
    END
  END t_out[92]
  PIN t_out[93]
    DIRECTION OUTPUT ;
    USE SIGNAL ;
    PORT
      LAYER M4 ;
        RECT  0 919.296 0.084 919.32 ;
    END
  END t_out[93]
  PIN t_out[94]
    DIRECTION OUTPUT ;
    USE SIGNAL ;
    PORT
      LAYER M4 ;
        RECT  0 919.488 0.084 919.512 ;
    END
  END t_out[94]
  PIN t_out[95]
    DIRECTION OUTPUT ;
    USE SIGNAL ;
    PORT
      LAYER M4 ;
        RECT  0 919.68 0.084 919.704 ;
    END
  END t_out[95]
  PIN t_out[96]
    DIRECTION OUTPUT ;
    USE SIGNAL ;
    PORT
      LAYER M4 ;
        RECT  0 919.872 0.084 919.896 ;
    END
  END t_out[96]
  PIN t_out[97]
    DIRECTION OUTPUT ;
    USE SIGNAL ;
    PORT
      LAYER M4 ;
        RECT  0 920.064 0.084 920.088 ;
    END
  END t_out[97]
  PIN t_out[98]
    DIRECTION OUTPUT ;
    USE SIGNAL ;
    PORT
      LAYER M4 ;
        RECT  0 920.256 0.084 920.28 ;
    END
  END t_out[98]
  PIN t_out[99]
    DIRECTION OUTPUT ;
    USE SIGNAL ;
    PORT
      LAYER M4 ;
        RECT  0 920.448 0.084 920.472 ;
    END
  END t_out[99]
  PIN t_out[9]
    DIRECTION OUTPUT ;
    USE SIGNAL ;
    PORT
      LAYER M4 ;
        RECT  0 902.4 0.084 902.424 ;
    END
  END t_out[9]
  PIN tap[0]
    DIRECTION INPUT ;
    USE SIGNAL ;
    PORT
      LAYER M4 ;
        RECT  457.836 561.024 457.92 561.048 ;
    END
  END tap[0]
  PIN tap[100]
    DIRECTION INPUT ;
    USE SIGNAL ;
    PORT
      LAYER M4 ;
        RECT  457.836 581.184 457.92 581.208 ;
    END
  END tap[100]
  PIN tap[101]
    DIRECTION INPUT ;
    USE SIGNAL ;
    PORT
      LAYER M4 ;
        RECT  457.836 581.376 457.92 581.4 ;
    END
  END tap[101]
  PIN tap[102]
    DIRECTION INPUT ;
    USE SIGNAL ;
    PORT
      LAYER M4 ;
        RECT  457.836 581.568 457.92 581.592 ;
    END
  END tap[102]
  PIN tap[103]
    DIRECTION INPUT ;
    USE SIGNAL ;
    PORT
      LAYER M4 ;
        RECT  457.836 581.76 457.92 581.784 ;
    END
  END tap[103]
  PIN tap[104]
    DIRECTION INPUT ;
    USE SIGNAL ;
    PORT
      LAYER M4 ;
        RECT  457.836 581.952 457.92 581.976 ;
    END
  END tap[104]
  PIN tap[105]
    DIRECTION INPUT ;
    USE SIGNAL ;
    PORT
      LAYER M4 ;
        RECT  457.836 582.144 457.92 582.168 ;
    END
  END tap[105]
  PIN tap[106]
    DIRECTION INPUT ;
    USE SIGNAL ;
    PORT
      LAYER M4 ;
        RECT  457.836 582.336 457.92 582.36 ;
    END
  END tap[106]
  PIN tap[107]
    DIRECTION INPUT ;
    USE SIGNAL ;
    PORT
      LAYER M4 ;
        RECT  457.836 582.528 457.92 582.552 ;
    END
  END tap[107]
  PIN tap[108]
    DIRECTION INPUT ;
    USE SIGNAL ;
    PORT
      LAYER M4 ;
        RECT  457.836 582.72 457.92 582.744 ;
    END
  END tap[108]
  PIN tap[109]
    DIRECTION INPUT ;
    USE SIGNAL ;
    PORT
      LAYER M4 ;
        RECT  457.836 582.912 457.92 582.936 ;
    END
  END tap[109]
  PIN tap[10]
    DIRECTION INPUT ;
    USE SIGNAL ;
    PORT
      LAYER M4 ;
        RECT  457.836 562.944 457.92 562.968 ;
    END
  END tap[10]
  PIN tap[110]
    DIRECTION INPUT ;
    USE SIGNAL ;
    PORT
      LAYER M4 ;
        RECT  457.836 583.104 457.92 583.128 ;
    END
  END tap[110]
  PIN tap[111]
    DIRECTION INPUT ;
    USE SIGNAL ;
    PORT
      LAYER M4 ;
        RECT  457.836 583.296 457.92 583.32 ;
    END
  END tap[111]
  PIN tap[112]
    DIRECTION INPUT ;
    USE SIGNAL ;
    PORT
      LAYER M4 ;
        RECT  457.836 583.488 457.92 583.512 ;
    END
  END tap[112]
  PIN tap[113]
    DIRECTION INPUT ;
    USE SIGNAL ;
    PORT
      LAYER M4 ;
        RECT  457.836 583.68 457.92 583.704 ;
    END
  END tap[113]
  PIN tap[114]
    DIRECTION INPUT ;
    USE SIGNAL ;
    PORT
      LAYER M4 ;
        RECT  457.836 583.872 457.92 583.896 ;
    END
  END tap[114]
  PIN tap[115]
    DIRECTION INPUT ;
    USE SIGNAL ;
    PORT
      LAYER M4 ;
        RECT  457.836 584.064 457.92 584.088 ;
    END
  END tap[115]
  PIN tap[116]
    DIRECTION INPUT ;
    USE SIGNAL ;
    PORT
      LAYER M4 ;
        RECT  457.836 584.256 457.92 584.28 ;
    END
  END tap[116]
  PIN tap[117]
    DIRECTION INPUT ;
    USE SIGNAL ;
    PORT
      LAYER M4 ;
        RECT  457.836 584.448 457.92 584.472 ;
    END
  END tap[117]
  PIN tap[118]
    DIRECTION INPUT ;
    USE SIGNAL ;
    PORT
      LAYER M4 ;
        RECT  457.836 584.64 457.92 584.664 ;
    END
  END tap[118]
  PIN tap[119]
    DIRECTION INPUT ;
    USE SIGNAL ;
    PORT
      LAYER M4 ;
        RECT  457.836 584.832 457.92 584.856 ;
    END
  END tap[119]
  PIN tap[11]
    DIRECTION INPUT ;
    USE SIGNAL ;
    PORT
      LAYER M4 ;
        RECT  457.836 563.136 457.92 563.16 ;
    END
  END tap[11]
  PIN tap[120]
    DIRECTION INPUT ;
    USE SIGNAL ;
    PORT
      LAYER M4 ;
        RECT  457.836 585.024 457.92 585.048 ;
    END
  END tap[120]
  PIN tap[121]
    DIRECTION INPUT ;
    USE SIGNAL ;
    PORT
      LAYER M4 ;
        RECT  457.836 585.216 457.92 585.24 ;
    END
  END tap[121]
  PIN tap[122]
    DIRECTION INPUT ;
    USE SIGNAL ;
    PORT
      LAYER M4 ;
        RECT  457.836 585.408 457.92 585.432 ;
    END
  END tap[122]
  PIN tap[123]
    DIRECTION INPUT ;
    USE SIGNAL ;
    PORT
      LAYER M4 ;
        RECT  457.836 585.6 457.92 585.624 ;
    END
  END tap[123]
  PIN tap[124]
    DIRECTION INPUT ;
    USE SIGNAL ;
    PORT
      LAYER M4 ;
        RECT  457.836 585.792 457.92 585.816 ;
    END
  END tap[124]
  PIN tap[125]
    DIRECTION INPUT ;
    USE SIGNAL ;
    PORT
      LAYER M4 ;
        RECT  457.836 585.984 457.92 586.008 ;
    END
  END tap[125]
  PIN tap[126]
    DIRECTION INPUT ;
    USE SIGNAL ;
    PORT
      LAYER M4 ;
        RECT  457.836 586.176 457.92 586.2 ;
    END
  END tap[126]
  PIN tap[127]
    DIRECTION INPUT ;
    USE SIGNAL ;
    PORT
      LAYER M4 ;
        RECT  457.836 586.368 457.92 586.392 ;
    END
  END tap[127]
  PIN tap[128]
    DIRECTION INPUT ;
    USE SIGNAL ;
    PORT
      LAYER M4 ;
        RECT  457.836 586.56 457.92 586.584 ;
    END
  END tap[128]
  PIN tap[129]
    DIRECTION INPUT ;
    USE SIGNAL ;
    PORT
      LAYER M4 ;
        RECT  457.836 586.752 457.92 586.776 ;
    END
  END tap[129]
  PIN tap[12]
    DIRECTION INPUT ;
    USE SIGNAL ;
    PORT
      LAYER M4 ;
        RECT  457.836 563.328 457.92 563.352 ;
    END
  END tap[12]
  PIN tap[130]
    DIRECTION INPUT ;
    USE SIGNAL ;
    PORT
      LAYER M4 ;
        RECT  457.836 586.944 457.92 586.968 ;
    END
  END tap[130]
  PIN tap[131]
    DIRECTION INPUT ;
    USE SIGNAL ;
    PORT
      LAYER M4 ;
        RECT  457.836 587.136 457.92 587.16 ;
    END
  END tap[131]
  PIN tap[132]
    DIRECTION INPUT ;
    USE SIGNAL ;
    PORT
      LAYER M4 ;
        RECT  457.836 587.328 457.92 587.352 ;
    END
  END tap[132]
  PIN tap[133]
    DIRECTION INPUT ;
    USE SIGNAL ;
    PORT
      LAYER M4 ;
        RECT  457.836 587.52 457.92 587.544 ;
    END
  END tap[133]
  PIN tap[134]
    DIRECTION INPUT ;
    USE SIGNAL ;
    PORT
      LAYER M4 ;
        RECT  457.836 587.712 457.92 587.736 ;
    END
  END tap[134]
  PIN tap[135]
    DIRECTION INPUT ;
    USE SIGNAL ;
    PORT
      LAYER M4 ;
        RECT  457.836 587.904 457.92 587.928 ;
    END
  END tap[135]
  PIN tap[136]
    DIRECTION INPUT ;
    USE SIGNAL ;
    PORT
      LAYER M4 ;
        RECT  457.836 588.096 457.92 588.12 ;
    END
  END tap[136]
  PIN tap[137]
    DIRECTION INPUT ;
    USE SIGNAL ;
    PORT
      LAYER M4 ;
        RECT  457.836 588.288 457.92 588.312 ;
    END
  END tap[137]
  PIN tap[138]
    DIRECTION INPUT ;
    USE SIGNAL ;
    PORT
      LAYER M4 ;
        RECT  457.836 588.48 457.92 588.504 ;
    END
  END tap[138]
  PIN tap[139]
    DIRECTION INPUT ;
    USE SIGNAL ;
    PORT
      LAYER M4 ;
        RECT  457.836 588.672 457.92 588.696 ;
    END
  END tap[139]
  PIN tap[13]
    DIRECTION INPUT ;
    USE SIGNAL ;
    PORT
      LAYER M4 ;
        RECT  457.836 563.52 457.92 563.544 ;
    END
  END tap[13]
  PIN tap[140]
    DIRECTION INPUT ;
    USE SIGNAL ;
    PORT
      LAYER M4 ;
        RECT  457.836 588.864 457.92 588.888 ;
    END
  END tap[140]
  PIN tap[141]
    DIRECTION INPUT ;
    USE SIGNAL ;
    PORT
      LAYER M4 ;
        RECT  457.836 589.056 457.92 589.08 ;
    END
  END tap[141]
  PIN tap[142]
    DIRECTION INPUT ;
    USE SIGNAL ;
    PORT
      LAYER M4 ;
        RECT  457.836 589.248 457.92 589.272 ;
    END
  END tap[142]
  PIN tap[143]
    DIRECTION INPUT ;
    USE SIGNAL ;
    PORT
      LAYER M4 ;
        RECT  457.836 589.44 457.92 589.464 ;
    END
  END tap[143]
  PIN tap[144]
    DIRECTION INPUT ;
    USE SIGNAL ;
    PORT
      LAYER M4 ;
        RECT  457.836 589.632 457.92 589.656 ;
    END
  END tap[144]
  PIN tap[145]
    DIRECTION INPUT ;
    USE SIGNAL ;
    PORT
      LAYER M4 ;
        RECT  457.836 589.824 457.92 589.848 ;
    END
  END tap[145]
  PIN tap[146]
    DIRECTION INPUT ;
    USE SIGNAL ;
    PORT
      LAYER M4 ;
        RECT  457.836 590.016 457.92 590.04 ;
    END
  END tap[146]
  PIN tap[147]
    DIRECTION INPUT ;
    USE SIGNAL ;
    PORT
      LAYER M4 ;
        RECT  457.836 590.208 457.92 590.232 ;
    END
  END tap[147]
  PIN tap[148]
    DIRECTION INPUT ;
    USE SIGNAL ;
    PORT
      LAYER M4 ;
        RECT  457.836 590.4 457.92 590.424 ;
    END
  END tap[148]
  PIN tap[149]
    DIRECTION INPUT ;
    USE SIGNAL ;
    PORT
      LAYER M4 ;
        RECT  457.836 590.592 457.92 590.616 ;
    END
  END tap[149]
  PIN tap[14]
    DIRECTION INPUT ;
    USE SIGNAL ;
    PORT
      LAYER M4 ;
        RECT  457.836 563.712 457.92 563.736 ;
    END
  END tap[14]
  PIN tap[150]
    DIRECTION INPUT ;
    USE SIGNAL ;
    PORT
      LAYER M4 ;
        RECT  457.836 590.784 457.92 590.808 ;
    END
  END tap[150]
  PIN tap[151]
    DIRECTION INPUT ;
    USE SIGNAL ;
    PORT
      LAYER M4 ;
        RECT  457.836 590.976 457.92 591 ;
    END
  END tap[151]
  PIN tap[152]
    DIRECTION INPUT ;
    USE SIGNAL ;
    PORT
      LAYER M4 ;
        RECT  457.836 591.168 457.92 591.192 ;
    END
  END tap[152]
  PIN tap[153]
    DIRECTION INPUT ;
    USE SIGNAL ;
    PORT
      LAYER M4 ;
        RECT  457.836 591.36 457.92 591.384 ;
    END
  END tap[153]
  PIN tap[154]
    DIRECTION INPUT ;
    USE SIGNAL ;
    PORT
      LAYER M4 ;
        RECT  457.836 591.552 457.92 591.576 ;
    END
  END tap[154]
  PIN tap[155]
    DIRECTION INPUT ;
    USE SIGNAL ;
    PORT
      LAYER M4 ;
        RECT  457.836 591.744 457.92 591.768 ;
    END
  END tap[155]
  PIN tap[156]
    DIRECTION INPUT ;
    USE SIGNAL ;
    PORT
      LAYER M4 ;
        RECT  457.836 591.936 457.92 591.96 ;
    END
  END tap[156]
  PIN tap[157]
    DIRECTION INPUT ;
    USE SIGNAL ;
    PORT
      LAYER M4 ;
        RECT  457.836 592.128 457.92 592.152 ;
    END
  END tap[157]
  PIN tap[158]
    DIRECTION INPUT ;
    USE SIGNAL ;
    PORT
      LAYER M4 ;
        RECT  457.836 592.32 457.92 592.344 ;
    END
  END tap[158]
  PIN tap[159]
    DIRECTION INPUT ;
    USE SIGNAL ;
    PORT
      LAYER M4 ;
        RECT  457.836 592.512 457.92 592.536 ;
    END
  END tap[159]
  PIN tap[15]
    DIRECTION INPUT ;
    USE SIGNAL ;
    PORT
      LAYER M4 ;
        RECT  457.836 563.904 457.92 563.928 ;
    END
  END tap[15]
  PIN tap[160]
    DIRECTION INPUT ;
    USE SIGNAL ;
    PORT
      LAYER M4 ;
        RECT  457.836 592.704 457.92 592.728 ;
    END
  END tap[160]
  PIN tap[161]
    DIRECTION INPUT ;
    USE SIGNAL ;
    PORT
      LAYER M4 ;
        RECT  457.836 592.896 457.92 592.92 ;
    END
  END tap[161]
  PIN tap[162]
    DIRECTION INPUT ;
    USE SIGNAL ;
    PORT
      LAYER M4 ;
        RECT  457.836 593.088 457.92 593.112 ;
    END
  END tap[162]
  PIN tap[163]
    DIRECTION INPUT ;
    USE SIGNAL ;
    PORT
      LAYER M4 ;
        RECT  457.836 593.28 457.92 593.304 ;
    END
  END tap[163]
  PIN tap[164]
    DIRECTION INPUT ;
    USE SIGNAL ;
    PORT
      LAYER M4 ;
        RECT  457.836 593.472 457.92 593.496 ;
    END
  END tap[164]
  PIN tap[165]
    DIRECTION INPUT ;
    USE SIGNAL ;
    PORT
      LAYER M4 ;
        RECT  457.836 593.664 457.92 593.688 ;
    END
  END tap[165]
  PIN tap[166]
    DIRECTION INPUT ;
    USE SIGNAL ;
    PORT
      LAYER M4 ;
        RECT  457.836 593.856 457.92 593.88 ;
    END
  END tap[166]
  PIN tap[167]
    DIRECTION INPUT ;
    USE SIGNAL ;
    PORT
      LAYER M4 ;
        RECT  457.836 594.048 457.92 594.072 ;
    END
  END tap[167]
  PIN tap[168]
    DIRECTION INPUT ;
    USE SIGNAL ;
    PORT
      LAYER M4 ;
        RECT  457.836 594.24 457.92 594.264 ;
    END
  END tap[168]
  PIN tap[169]
    DIRECTION INPUT ;
    USE SIGNAL ;
    PORT
      LAYER M4 ;
        RECT  457.836 594.432 457.92 594.456 ;
    END
  END tap[169]
  PIN tap[16]
    DIRECTION INPUT ;
    USE SIGNAL ;
    PORT
      LAYER M4 ;
        RECT  457.836 564.096 457.92 564.12 ;
    END
  END tap[16]
  PIN tap[170]
    DIRECTION INPUT ;
    USE SIGNAL ;
    PORT
      LAYER M4 ;
        RECT  457.836 594.624 457.92 594.648 ;
    END
  END tap[170]
  PIN tap[171]
    DIRECTION INPUT ;
    USE SIGNAL ;
    PORT
      LAYER M4 ;
        RECT  457.836 594.816 457.92 594.84 ;
    END
  END tap[171]
  PIN tap[172]
    DIRECTION INPUT ;
    USE SIGNAL ;
    PORT
      LAYER M4 ;
        RECT  457.836 595.008 457.92 595.032 ;
    END
  END tap[172]
  PIN tap[173]
    DIRECTION INPUT ;
    USE SIGNAL ;
    PORT
      LAYER M4 ;
        RECT  457.836 595.2 457.92 595.224 ;
    END
  END tap[173]
  PIN tap[174]
    DIRECTION INPUT ;
    USE SIGNAL ;
    PORT
      LAYER M4 ;
        RECT  457.836 595.392 457.92 595.416 ;
    END
  END tap[174]
  PIN tap[175]
    DIRECTION INPUT ;
    USE SIGNAL ;
    PORT
      LAYER M4 ;
        RECT  457.836 595.584 457.92 595.608 ;
    END
  END tap[175]
  PIN tap[176]
    DIRECTION INPUT ;
    USE SIGNAL ;
    PORT
      LAYER M4 ;
        RECT  457.836 595.776 457.92 595.8 ;
    END
  END tap[176]
  PIN tap[177]
    DIRECTION INPUT ;
    USE SIGNAL ;
    PORT
      LAYER M4 ;
        RECT  457.836 595.968 457.92 595.992 ;
    END
  END tap[177]
  PIN tap[178]
    DIRECTION INPUT ;
    USE SIGNAL ;
    PORT
      LAYER M4 ;
        RECT  457.836 596.16 457.92 596.184 ;
    END
  END tap[178]
  PIN tap[179]
    DIRECTION INPUT ;
    USE SIGNAL ;
    PORT
      LAYER M4 ;
        RECT  457.836 596.352 457.92 596.376 ;
    END
  END tap[179]
  PIN tap[17]
    DIRECTION INPUT ;
    USE SIGNAL ;
    PORT
      LAYER M4 ;
        RECT  457.836 565.248 457.92 565.272 ;
    END
  END tap[17]
  PIN tap[180]
    DIRECTION INPUT ;
    USE SIGNAL ;
    PORT
      LAYER M4 ;
        RECT  457.836 596.544 457.92 596.568 ;
    END
  END tap[180]
  PIN tap[181]
    DIRECTION INPUT ;
    USE SIGNAL ;
    PORT
      LAYER M4 ;
        RECT  457.836 596.736 457.92 596.76 ;
    END
  END tap[181]
  PIN tap[182]
    DIRECTION INPUT ;
    USE SIGNAL ;
    PORT
      LAYER M4 ;
        RECT  457.836 596.928 457.92 596.952 ;
    END
  END tap[182]
  PIN tap[183]
    DIRECTION INPUT ;
    USE SIGNAL ;
    PORT
      LAYER M4 ;
        RECT  457.836 597.12 457.92 597.144 ;
    END
  END tap[183]
  PIN tap[184]
    DIRECTION INPUT ;
    USE SIGNAL ;
    PORT
      LAYER M4 ;
        RECT  457.836 597.312 457.92 597.336 ;
    END
  END tap[184]
  PIN tap[185]
    DIRECTION INPUT ;
    USE SIGNAL ;
    PORT
      LAYER M4 ;
        RECT  457.836 597.504 457.92 597.528 ;
    END
  END tap[185]
  PIN tap[186]
    DIRECTION INPUT ;
    USE SIGNAL ;
    PORT
      LAYER M4 ;
        RECT  457.836 597.696 457.92 597.72 ;
    END
  END tap[186]
  PIN tap[187]
    DIRECTION INPUT ;
    USE SIGNAL ;
    PORT
      LAYER M4 ;
        RECT  457.836 597.888 457.92 597.912 ;
    END
  END tap[187]
  PIN tap[188]
    DIRECTION INPUT ;
    USE SIGNAL ;
    PORT
      LAYER M4 ;
        RECT  457.836 598.08 457.92 598.104 ;
    END
  END tap[188]
  PIN tap[189]
    DIRECTION INPUT ;
    USE SIGNAL ;
    PORT
      LAYER M4 ;
        RECT  457.836 598.272 457.92 598.296 ;
    END
  END tap[189]
  PIN tap[18]
    DIRECTION INPUT ;
    USE SIGNAL ;
    PORT
      LAYER M4 ;
        RECT  457.836 565.44 457.92 565.464 ;
    END
  END tap[18]
  PIN tap[190]
    DIRECTION INPUT ;
    USE SIGNAL ;
    PORT
      LAYER M4 ;
        RECT  457.836 598.464 457.92 598.488 ;
    END
  END tap[190]
  PIN tap[191]
    DIRECTION INPUT ;
    USE SIGNAL ;
    PORT
      LAYER M4 ;
        RECT  457.836 598.656 457.92 598.68 ;
    END
  END tap[191]
  PIN tap[192]
    DIRECTION INPUT ;
    USE SIGNAL ;
    PORT
      LAYER M4 ;
        RECT  457.836 598.848 457.92 598.872 ;
    END
  END tap[192]
  PIN tap[193]
    DIRECTION INPUT ;
    USE SIGNAL ;
    PORT
      LAYER M4 ;
        RECT  457.836 599.04 457.92 599.064 ;
    END
  END tap[193]
  PIN tap[194]
    DIRECTION INPUT ;
    USE SIGNAL ;
    PORT
      LAYER M4 ;
        RECT  457.836 599.232 457.92 599.256 ;
    END
  END tap[194]
  PIN tap[195]
    DIRECTION INPUT ;
    USE SIGNAL ;
    PORT
      LAYER M4 ;
        RECT  457.836 599.424 457.92 599.448 ;
    END
  END tap[195]
  PIN tap[196]
    DIRECTION INPUT ;
    USE SIGNAL ;
    PORT
      LAYER M4 ;
        RECT  457.836 599.616 457.92 599.64 ;
    END
  END tap[196]
  PIN tap[197]
    DIRECTION INPUT ;
    USE SIGNAL ;
    PORT
      LAYER M4 ;
        RECT  457.836 599.808 457.92 599.832 ;
    END
  END tap[197]
  PIN tap[198]
    DIRECTION INPUT ;
    USE SIGNAL ;
    PORT
      LAYER M4 ;
        RECT  457.836 600 457.92 600.024 ;
    END
  END tap[198]
  PIN tap[199]
    DIRECTION INPUT ;
    USE SIGNAL ;
    PORT
      LAYER M4 ;
        RECT  457.836 600.192 457.92 600.216 ;
    END
  END tap[199]
  PIN tap[19]
    DIRECTION INPUT ;
    USE SIGNAL ;
    PORT
      LAYER M4 ;
        RECT  457.836 565.632 457.92 565.656 ;
    END
  END tap[19]
  PIN tap[1]
    DIRECTION INPUT ;
    USE SIGNAL ;
    PORT
      LAYER M4 ;
        RECT  457.836 561.216 457.92 561.24 ;
    END
  END tap[1]
  PIN tap[200]
    DIRECTION INPUT ;
    USE SIGNAL ;
    PORT
      LAYER M4 ;
        RECT  457.836 600.384 457.92 600.408 ;
    END
  END tap[200]
  PIN tap[201]
    DIRECTION INPUT ;
    USE SIGNAL ;
    PORT
      LAYER M4 ;
        RECT  457.836 600.576 457.92 600.6 ;
    END
  END tap[201]
  PIN tap[202]
    DIRECTION INPUT ;
    USE SIGNAL ;
    PORT
      LAYER M4 ;
        RECT  457.836 600.768 457.92 600.792 ;
    END
  END tap[202]
  PIN tap[203]
    DIRECTION INPUT ;
    USE SIGNAL ;
    PORT
      LAYER M4 ;
        RECT  457.836 600.96 457.92 600.984 ;
    END
  END tap[203]
  PIN tap[204]
    DIRECTION INPUT ;
    USE SIGNAL ;
    PORT
      LAYER M4 ;
        RECT  457.836 601.152 457.92 601.176 ;
    END
  END tap[204]
  PIN tap[205]
    DIRECTION INPUT ;
    USE SIGNAL ;
    PORT
      LAYER M4 ;
        RECT  457.836 601.344 457.92 601.368 ;
    END
  END tap[205]
  PIN tap[206]
    DIRECTION INPUT ;
    USE SIGNAL ;
    PORT
      LAYER M4 ;
        RECT  457.836 601.536 457.92 601.56 ;
    END
  END tap[206]
  PIN tap[207]
    DIRECTION INPUT ;
    USE SIGNAL ;
    PORT
      LAYER M4 ;
        RECT  457.836 601.728 457.92 601.752 ;
    END
  END tap[207]
  PIN tap[208]
    DIRECTION INPUT ;
    USE SIGNAL ;
    PORT
      LAYER M4 ;
        RECT  457.836 601.92 457.92 601.944 ;
    END
  END tap[208]
  PIN tap[209]
    DIRECTION INPUT ;
    USE SIGNAL ;
    PORT
      LAYER M4 ;
        RECT  457.836 602.112 457.92 602.136 ;
    END
  END tap[209]
  PIN tap[20]
    DIRECTION INPUT ;
    USE SIGNAL ;
    PORT
      LAYER M4 ;
        RECT  457.836 565.824 457.92 565.848 ;
    END
  END tap[20]
  PIN tap[210]
    DIRECTION INPUT ;
    USE SIGNAL ;
    PORT
      LAYER M4 ;
        RECT  457.836 602.304 457.92 602.328 ;
    END
  END tap[210]
  PIN tap[211]
    DIRECTION INPUT ;
    USE SIGNAL ;
    PORT
      LAYER M4 ;
        RECT  457.836 602.496 457.92 602.52 ;
    END
  END tap[211]
  PIN tap[212]
    DIRECTION INPUT ;
    USE SIGNAL ;
    PORT
      LAYER M4 ;
        RECT  457.836 602.688 457.92 602.712 ;
    END
  END tap[212]
  PIN tap[213]
    DIRECTION INPUT ;
    USE SIGNAL ;
    PORT
      LAYER M4 ;
        RECT  457.836 602.88 457.92 602.904 ;
    END
  END tap[213]
  PIN tap[214]
    DIRECTION INPUT ;
    USE SIGNAL ;
    PORT
      LAYER M4 ;
        RECT  457.836 603.072 457.92 603.096 ;
    END
  END tap[214]
  PIN tap[215]
    DIRECTION INPUT ;
    USE SIGNAL ;
    PORT
      LAYER M4 ;
        RECT  457.836 603.264 457.92 603.288 ;
    END
  END tap[215]
  PIN tap[216]
    DIRECTION INPUT ;
    USE SIGNAL ;
    PORT
      LAYER M4 ;
        RECT  457.836 603.456 457.92 603.48 ;
    END
  END tap[216]
  PIN tap[217]
    DIRECTION INPUT ;
    USE SIGNAL ;
    PORT
      LAYER M4 ;
        RECT  457.836 603.648 457.92 603.672 ;
    END
  END tap[217]
  PIN tap[218]
    DIRECTION INPUT ;
    USE SIGNAL ;
    PORT
      LAYER M4 ;
        RECT  457.836 603.84 457.92 603.864 ;
    END
  END tap[218]
  PIN tap[219]
    DIRECTION INPUT ;
    USE SIGNAL ;
    PORT
      LAYER M4 ;
        RECT  457.836 604.032 457.92 604.056 ;
    END
  END tap[219]
  PIN tap[21]
    DIRECTION INPUT ;
    USE SIGNAL ;
    PORT
      LAYER M4 ;
        RECT  457.836 566.016 457.92 566.04 ;
    END
  END tap[21]
  PIN tap[220]
    DIRECTION INPUT ;
    USE SIGNAL ;
    PORT
      LAYER M4 ;
        RECT  457.836 604.224 457.92 604.248 ;
    END
  END tap[220]
  PIN tap[221]
    DIRECTION INPUT ;
    USE SIGNAL ;
    PORT
      LAYER M4 ;
        RECT  457.836 604.416 457.92 604.44 ;
    END
  END tap[221]
  PIN tap[222]
    DIRECTION INPUT ;
    USE SIGNAL ;
    PORT
      LAYER M4 ;
        RECT  457.836 604.608 457.92 604.632 ;
    END
  END tap[222]
  PIN tap[223]
    DIRECTION INPUT ;
    USE SIGNAL ;
    PORT
      LAYER M4 ;
        RECT  457.836 604.8 457.92 604.824 ;
    END
  END tap[223]
  PIN tap[224]
    DIRECTION INPUT ;
    USE SIGNAL ;
    PORT
      LAYER M4 ;
        RECT  457.836 604.992 457.92 605.016 ;
    END
  END tap[224]
  PIN tap[225]
    DIRECTION INPUT ;
    USE SIGNAL ;
    PORT
      LAYER M4 ;
        RECT  457.836 605.184 457.92 605.208 ;
    END
  END tap[225]
  PIN tap[226]
    DIRECTION INPUT ;
    USE SIGNAL ;
    PORT
      LAYER M4 ;
        RECT  457.836 605.376 457.92 605.4 ;
    END
  END tap[226]
  PIN tap[227]
    DIRECTION INPUT ;
    USE SIGNAL ;
    PORT
      LAYER M4 ;
        RECT  457.836 605.568 457.92 605.592 ;
    END
  END tap[227]
  PIN tap[228]
    DIRECTION INPUT ;
    USE SIGNAL ;
    PORT
      LAYER M4 ;
        RECT  457.836 605.76 457.92 605.784 ;
    END
  END tap[228]
  PIN tap[229]
    DIRECTION INPUT ;
    USE SIGNAL ;
    PORT
      LAYER M4 ;
        RECT  457.836 605.952 457.92 605.976 ;
    END
  END tap[229]
  PIN tap[22]
    DIRECTION INPUT ;
    USE SIGNAL ;
    PORT
      LAYER M4 ;
        RECT  457.836 566.208 457.92 566.232 ;
    END
  END tap[22]
  PIN tap[230]
    DIRECTION INPUT ;
    USE SIGNAL ;
    PORT
      LAYER M4 ;
        RECT  457.836 606.144 457.92 606.168 ;
    END
  END tap[230]
  PIN tap[231]
    DIRECTION INPUT ;
    USE SIGNAL ;
    PORT
      LAYER M4 ;
        RECT  457.836 606.336 457.92 606.36 ;
    END
  END tap[231]
  PIN tap[232]
    DIRECTION INPUT ;
    USE SIGNAL ;
    PORT
      LAYER M4 ;
        RECT  457.836 606.528 457.92 606.552 ;
    END
  END tap[232]
  PIN tap[233]
    DIRECTION INPUT ;
    USE SIGNAL ;
    PORT
      LAYER M4 ;
        RECT  457.836 606.72 457.92 606.744 ;
    END
  END tap[233]
  PIN tap[234]
    DIRECTION INPUT ;
    USE SIGNAL ;
    PORT
      LAYER M4 ;
        RECT  457.836 606.912 457.92 606.936 ;
    END
  END tap[234]
  PIN tap[235]
    DIRECTION INPUT ;
    USE SIGNAL ;
    PORT
      LAYER M4 ;
        RECT  457.836 607.104 457.92 607.128 ;
    END
  END tap[235]
  PIN tap[236]
    DIRECTION INPUT ;
    USE SIGNAL ;
    PORT
      LAYER M4 ;
        RECT  457.836 607.296 457.92 607.32 ;
    END
  END tap[236]
  PIN tap[237]
    DIRECTION INPUT ;
    USE SIGNAL ;
    PORT
      LAYER M4 ;
        RECT  457.836 607.488 457.92 607.512 ;
    END
  END tap[237]
  PIN tap[238]
    DIRECTION INPUT ;
    USE SIGNAL ;
    PORT
      LAYER M4 ;
        RECT  457.836 607.68 457.92 607.704 ;
    END
  END tap[238]
  PIN tap[239]
    DIRECTION INPUT ;
    USE SIGNAL ;
    PORT
      LAYER M4 ;
        RECT  457.836 607.872 457.92 607.896 ;
    END
  END tap[239]
  PIN tap[23]
    DIRECTION INPUT ;
    USE SIGNAL ;
    PORT
      LAYER M4 ;
        RECT  457.836 566.4 457.92 566.424 ;
    END
  END tap[23]
  PIN tap[240]
    DIRECTION INPUT ;
    USE SIGNAL ;
    PORT
      LAYER M4 ;
        RECT  457.836 608.064 457.92 608.088 ;
    END
  END tap[240]
  PIN tap[241]
    DIRECTION INPUT ;
    USE SIGNAL ;
    PORT
      LAYER M4 ;
        RECT  457.836 608.256 457.92 608.28 ;
    END
  END tap[241]
  PIN tap[242]
    DIRECTION INPUT ;
    USE SIGNAL ;
    PORT
      LAYER M4 ;
        RECT  457.836 608.448 457.92 608.472 ;
    END
  END tap[242]
  PIN tap[243]
    DIRECTION INPUT ;
    USE SIGNAL ;
    PORT
      LAYER M4 ;
        RECT  457.836 608.64 457.92 608.664 ;
    END
  END tap[243]
  PIN tap[244]
    DIRECTION INPUT ;
    USE SIGNAL ;
    PORT
      LAYER M4 ;
        RECT  457.836 608.832 457.92 608.856 ;
    END
  END tap[244]
  PIN tap[245]
    DIRECTION INPUT ;
    USE SIGNAL ;
    PORT
      LAYER M4 ;
        RECT  457.836 609.024 457.92 609.048 ;
    END
  END tap[245]
  PIN tap[246]
    DIRECTION INPUT ;
    USE SIGNAL ;
    PORT
      LAYER M4 ;
        RECT  457.836 609.216 457.92 609.24 ;
    END
  END tap[246]
  PIN tap[247]
    DIRECTION INPUT ;
    USE SIGNAL ;
    PORT
      LAYER M4 ;
        RECT  457.836 609.408 457.92 609.432 ;
    END
  END tap[247]
  PIN tap[248]
    DIRECTION INPUT ;
    USE SIGNAL ;
    PORT
      LAYER M4 ;
        RECT  457.836 609.6 457.92 609.624 ;
    END
  END tap[248]
  PIN tap[249]
    DIRECTION INPUT ;
    USE SIGNAL ;
    PORT
      LAYER M4 ;
        RECT  457.836 609.792 457.92 609.816 ;
    END
  END tap[249]
  PIN tap[24]
    DIRECTION INPUT ;
    USE SIGNAL ;
    PORT
      LAYER M4 ;
        RECT  457.836 566.592 457.92 566.616 ;
    END
  END tap[24]
  PIN tap[250]
    DIRECTION INPUT ;
    USE SIGNAL ;
    PORT
      LAYER M4 ;
        RECT  457.836 609.984 457.92 610.008 ;
    END
  END tap[250]
  PIN tap[251]
    DIRECTION INPUT ;
    USE SIGNAL ;
    PORT
      LAYER M4 ;
        RECT  457.836 610.176 457.92 610.2 ;
    END
  END tap[251]
  PIN tap[252]
    DIRECTION INPUT ;
    USE SIGNAL ;
    PORT
      LAYER M4 ;
        RECT  457.836 610.368 457.92 610.392 ;
    END
  END tap[252]
  PIN tap[253]
    DIRECTION INPUT ;
    USE SIGNAL ;
    PORT
      LAYER M4 ;
        RECT  457.836 610.56 457.92 610.584 ;
    END
  END tap[253]
  PIN tap[254]
    DIRECTION INPUT ;
    USE SIGNAL ;
    PORT
      LAYER M4 ;
        RECT  457.836 610.752 457.92 610.776 ;
    END
  END tap[254]
  PIN tap[255]
    DIRECTION INPUT ;
    USE SIGNAL ;
    PORT
      LAYER M4 ;
        RECT  457.836 610.944 457.92 610.968 ;
    END
  END tap[255]
  PIN tap[256]
    DIRECTION INPUT ;
    USE SIGNAL ;
    PORT
      LAYER M4 ;
        RECT  457.836 611.136 457.92 611.16 ;
    END
  END tap[256]
  PIN tap[257]
    DIRECTION INPUT ;
    USE SIGNAL ;
    PORT
      LAYER M4 ;
        RECT  457.836 611.328 457.92 611.352 ;
    END
  END tap[257]
  PIN tap[258]
    DIRECTION INPUT ;
    USE SIGNAL ;
    PORT
      LAYER M4 ;
        RECT  457.836 611.52 457.92 611.544 ;
    END
  END tap[258]
  PIN tap[259]
    DIRECTION INPUT ;
    USE SIGNAL ;
    PORT
      LAYER M4 ;
        RECT  457.836 611.712 457.92 611.736 ;
    END
  END tap[259]
  PIN tap[25]
    DIRECTION INPUT ;
    USE SIGNAL ;
    PORT
      LAYER M4 ;
        RECT  457.836 566.784 457.92 566.808 ;
    END
  END tap[25]
  PIN tap[260]
    DIRECTION INPUT ;
    USE SIGNAL ;
    PORT
      LAYER M4 ;
        RECT  457.836 611.904 457.92 611.928 ;
    END
  END tap[260]
  PIN tap[261]
    DIRECTION INPUT ;
    USE SIGNAL ;
    PORT
      LAYER M4 ;
        RECT  457.836 612.096 457.92 612.12 ;
    END
  END tap[261]
  PIN tap[262]
    DIRECTION INPUT ;
    USE SIGNAL ;
    PORT
      LAYER M4 ;
        RECT  457.836 612.288 457.92 612.312 ;
    END
  END tap[262]
  PIN tap[263]
    DIRECTION INPUT ;
    USE SIGNAL ;
    PORT
      LAYER M4 ;
        RECT  457.836 612.48 457.92 612.504 ;
    END
  END tap[263]
  PIN tap[264]
    DIRECTION INPUT ;
    USE SIGNAL ;
    PORT
      LAYER M4 ;
        RECT  457.836 612.672 457.92 612.696 ;
    END
  END tap[264]
  PIN tap[265]
    DIRECTION INPUT ;
    USE SIGNAL ;
    PORT
      LAYER M4 ;
        RECT  457.836 612.864 457.92 612.888 ;
    END
  END tap[265]
  PIN tap[266]
    DIRECTION INPUT ;
    USE SIGNAL ;
    PORT
      LAYER M4 ;
        RECT  457.836 613.056 457.92 613.08 ;
    END
  END tap[266]
  PIN tap[267]
    DIRECTION INPUT ;
    USE SIGNAL ;
    PORT
      LAYER M4 ;
        RECT  457.836 613.248 457.92 613.272 ;
    END
  END tap[267]
  PIN tap[268]
    DIRECTION INPUT ;
    USE SIGNAL ;
    PORT
      LAYER M4 ;
        RECT  457.836 613.44 457.92 613.464 ;
    END
  END tap[268]
  PIN tap[269]
    DIRECTION INPUT ;
    USE SIGNAL ;
    PORT
      LAYER M4 ;
        RECT  457.836 613.632 457.92 613.656 ;
    END
  END tap[269]
  PIN tap[26]
    DIRECTION INPUT ;
    USE SIGNAL ;
    PORT
      LAYER M4 ;
        RECT  457.836 566.976 457.92 567 ;
    END
  END tap[26]
  PIN tap[270]
    DIRECTION INPUT ;
    USE SIGNAL ;
    PORT
      LAYER M4 ;
        RECT  457.836 613.824 457.92 613.848 ;
    END
  END tap[270]
  PIN tap[271]
    DIRECTION INPUT ;
    USE SIGNAL ;
    PORT
      LAYER M4 ;
        RECT  457.836 614.016 457.92 614.04 ;
    END
  END tap[271]
  PIN tap[272]
    DIRECTION INPUT ;
    USE SIGNAL ;
    PORT
      LAYER M4 ;
        RECT  457.836 614.208 457.92 614.232 ;
    END
  END tap[272]
  PIN tap[273]
    DIRECTION INPUT ;
    USE SIGNAL ;
    PORT
      LAYER M4 ;
        RECT  457.836 614.4 457.92 614.424 ;
    END
  END tap[273]
  PIN tap[274]
    DIRECTION INPUT ;
    USE SIGNAL ;
    PORT
      LAYER M4 ;
        RECT  457.836 614.592 457.92 614.616 ;
    END
  END tap[274]
  PIN tap[275]
    DIRECTION INPUT ;
    USE SIGNAL ;
    PORT
      LAYER M4 ;
        RECT  457.836 614.784 457.92 614.808 ;
    END
  END tap[275]
  PIN tap[276]
    DIRECTION INPUT ;
    USE SIGNAL ;
    PORT
      LAYER M4 ;
        RECT  457.836 614.976 457.92 615 ;
    END
  END tap[276]
  PIN tap[277]
    DIRECTION INPUT ;
    USE SIGNAL ;
    PORT
      LAYER M4 ;
        RECT  457.836 615.168 457.92 615.192 ;
    END
  END tap[277]
  PIN tap[278]
    DIRECTION INPUT ;
    USE SIGNAL ;
    PORT
      LAYER M4 ;
        RECT  457.836 615.36 457.92 615.384 ;
    END
  END tap[278]
  PIN tap[279]
    DIRECTION INPUT ;
    USE SIGNAL ;
    PORT
      LAYER M4 ;
        RECT  457.836 615.552 457.92 615.576 ;
    END
  END tap[279]
  PIN tap[27]
    DIRECTION INPUT ;
    USE SIGNAL ;
    PORT
      LAYER M4 ;
        RECT  457.836 567.168 457.92 567.192 ;
    END
  END tap[27]
  PIN tap[280]
    DIRECTION INPUT ;
    USE SIGNAL ;
    PORT
      LAYER M4 ;
        RECT  457.836 615.744 457.92 615.768 ;
    END
  END tap[280]
  PIN tap[281]
    DIRECTION INPUT ;
    USE SIGNAL ;
    PORT
      LAYER M4 ;
        RECT  457.836 615.936 457.92 615.96 ;
    END
  END tap[281]
  PIN tap[282]
    DIRECTION INPUT ;
    USE SIGNAL ;
    PORT
      LAYER M4 ;
        RECT  457.836 616.128 457.92 616.152 ;
    END
  END tap[282]
  PIN tap[283]
    DIRECTION INPUT ;
    USE SIGNAL ;
    PORT
      LAYER M4 ;
        RECT  457.836 616.32 457.92 616.344 ;
    END
  END tap[283]
  PIN tap[284]
    DIRECTION INPUT ;
    USE SIGNAL ;
    PORT
      LAYER M4 ;
        RECT  457.836 616.512 457.92 616.536 ;
    END
  END tap[284]
  PIN tap[285]
    DIRECTION INPUT ;
    USE SIGNAL ;
    PORT
      LAYER M4 ;
        RECT  457.836 616.704 457.92 616.728 ;
    END
  END tap[285]
  PIN tap[286]
    DIRECTION INPUT ;
    USE SIGNAL ;
    PORT
      LAYER M4 ;
        RECT  457.836 616.896 457.92 616.92 ;
    END
  END tap[286]
  PIN tap[287]
    DIRECTION INPUT ;
    USE SIGNAL ;
    PORT
      LAYER M4 ;
        RECT  457.836 617.088 457.92 617.112 ;
    END
  END tap[287]
  PIN tap[288]
    DIRECTION INPUT ;
    USE SIGNAL ;
    PORT
      LAYER M4 ;
        RECT  457.836 617.28 457.92 617.304 ;
    END
  END tap[288]
  PIN tap[289]
    DIRECTION INPUT ;
    USE SIGNAL ;
    PORT
      LAYER M4 ;
        RECT  457.836 617.472 457.92 617.496 ;
    END
  END tap[289]
  PIN tap[28]
    DIRECTION INPUT ;
    USE SIGNAL ;
    PORT
      LAYER M4 ;
        RECT  457.836 567.36 457.92 567.384 ;
    END
  END tap[28]
  PIN tap[290]
    DIRECTION INPUT ;
    USE SIGNAL ;
    PORT
      LAYER M4 ;
        RECT  457.836 617.664 457.92 617.688 ;
    END
  END tap[290]
  PIN tap[291]
    DIRECTION INPUT ;
    USE SIGNAL ;
    PORT
      LAYER M4 ;
        RECT  457.836 617.856 457.92 617.88 ;
    END
  END tap[291]
  PIN tap[292]
    DIRECTION INPUT ;
    USE SIGNAL ;
    PORT
      LAYER M4 ;
        RECT  457.836 618.048 457.92 618.072 ;
    END
  END tap[292]
  PIN tap[293]
    DIRECTION INPUT ;
    USE SIGNAL ;
    PORT
      LAYER M4 ;
        RECT  457.836 618.24 457.92 618.264 ;
    END
  END tap[293]
  PIN tap[294]
    DIRECTION INPUT ;
    USE SIGNAL ;
    PORT
      LAYER M4 ;
        RECT  457.836 618.432 457.92 618.456 ;
    END
  END tap[294]
  PIN tap[295]
    DIRECTION INPUT ;
    USE SIGNAL ;
    PORT
      LAYER M4 ;
        RECT  457.836 618.624 457.92 618.648 ;
    END
  END tap[295]
  PIN tap[296]
    DIRECTION INPUT ;
    USE SIGNAL ;
    PORT
      LAYER M4 ;
        RECT  457.836 618.816 457.92 618.84 ;
    END
  END tap[296]
  PIN tap[297]
    DIRECTION INPUT ;
    USE SIGNAL ;
    PORT
      LAYER M4 ;
        RECT  457.836 619.008 457.92 619.032 ;
    END
  END tap[297]
  PIN tap[298]
    DIRECTION INPUT ;
    USE SIGNAL ;
    PORT
      LAYER M4 ;
        RECT  457.836 619.2 457.92 619.224 ;
    END
  END tap[298]
  PIN tap[299]
    DIRECTION INPUT ;
    USE SIGNAL ;
    PORT
      LAYER M4 ;
        RECT  457.836 619.392 457.92 619.416 ;
    END
  END tap[299]
  PIN tap[29]
    DIRECTION INPUT ;
    USE SIGNAL ;
    PORT
      LAYER M4 ;
        RECT  457.836 567.552 457.92 567.576 ;
    END
  END tap[29]
  PIN tap[2]
    DIRECTION INPUT ;
    USE SIGNAL ;
    PORT
      LAYER M4 ;
        RECT  457.836 561.408 457.92 561.432 ;
    END
  END tap[2]
  PIN tap[300]
    DIRECTION INPUT ;
    USE SIGNAL ;
    PORT
      LAYER M4 ;
        RECT  457.836 619.584 457.92 619.608 ;
    END
  END tap[300]
  PIN tap[301]
    DIRECTION INPUT ;
    USE SIGNAL ;
    PORT
      LAYER M4 ;
        RECT  457.836 619.776 457.92 619.8 ;
    END
  END tap[301]
  PIN tap[302]
    DIRECTION INPUT ;
    USE SIGNAL ;
    PORT
      LAYER M4 ;
        RECT  457.836 619.968 457.92 619.992 ;
    END
  END tap[302]
  PIN tap[303]
    DIRECTION INPUT ;
    USE SIGNAL ;
    PORT
      LAYER M4 ;
        RECT  457.836 620.16 457.92 620.184 ;
    END
  END tap[303]
  PIN tap[304]
    DIRECTION INPUT ;
    USE SIGNAL ;
    PORT
      LAYER M4 ;
        RECT  457.836 620.352 457.92 620.376 ;
    END
  END tap[304]
  PIN tap[305]
    DIRECTION INPUT ;
    USE SIGNAL ;
    PORT
      LAYER M4 ;
        RECT  457.836 620.544 457.92 620.568 ;
    END
  END tap[305]
  PIN tap[306]
    DIRECTION INPUT ;
    USE SIGNAL ;
    PORT
      LAYER M4 ;
        RECT  457.836 620.736 457.92 620.76 ;
    END
  END tap[306]
  PIN tap[307]
    DIRECTION INPUT ;
    USE SIGNAL ;
    PORT
      LAYER M4 ;
        RECT  457.836 620.928 457.92 620.952 ;
    END
  END tap[307]
  PIN tap[308]
    DIRECTION INPUT ;
    USE SIGNAL ;
    PORT
      LAYER M4 ;
        RECT  457.836 621.12 457.92 621.144 ;
    END
  END tap[308]
  PIN tap[309]
    DIRECTION INPUT ;
    USE SIGNAL ;
    PORT
      LAYER M4 ;
        RECT  457.836 621.312 457.92 621.336 ;
    END
  END tap[309]
  PIN tap[30]
    DIRECTION INPUT ;
    USE SIGNAL ;
    PORT
      LAYER M4 ;
        RECT  457.836 567.744 457.92 567.768 ;
    END
  END tap[30]
  PIN tap[310]
    DIRECTION INPUT ;
    USE SIGNAL ;
    PORT
      LAYER M4 ;
        RECT  457.836 621.504 457.92 621.528 ;
    END
  END tap[310]
  PIN tap[311]
    DIRECTION INPUT ;
    USE SIGNAL ;
    PORT
      LAYER M4 ;
        RECT  457.836 621.696 457.92 621.72 ;
    END
  END tap[311]
  PIN tap[312]
    DIRECTION INPUT ;
    USE SIGNAL ;
    PORT
      LAYER M4 ;
        RECT  457.836 621.888 457.92 621.912 ;
    END
  END tap[312]
  PIN tap[313]
    DIRECTION INPUT ;
    USE SIGNAL ;
    PORT
      LAYER M4 ;
        RECT  457.836 622.08 457.92 622.104 ;
    END
  END tap[313]
  PIN tap[314]
    DIRECTION INPUT ;
    USE SIGNAL ;
    PORT
      LAYER M4 ;
        RECT  457.836 622.272 457.92 622.296 ;
    END
  END tap[314]
  PIN tap[315]
    DIRECTION INPUT ;
    USE SIGNAL ;
    PORT
      LAYER M4 ;
        RECT  457.836 622.464 457.92 622.488 ;
    END
  END tap[315]
  PIN tap[316]
    DIRECTION INPUT ;
    USE SIGNAL ;
    PORT
      LAYER M4 ;
        RECT  457.836 623.616 457.92 623.64 ;
    END
  END tap[316]
  PIN tap[317]
    DIRECTION INPUT ;
    USE SIGNAL ;
    PORT
      LAYER M4 ;
        RECT  457.836 623.808 457.92 623.832 ;
    END
  END tap[317]
  PIN tap[318]
    DIRECTION INPUT ;
    USE SIGNAL ;
    PORT
      LAYER M4 ;
        RECT  457.836 624 457.92 624.024 ;
    END
  END tap[318]
  PIN tap[319]
    DIRECTION INPUT ;
    USE SIGNAL ;
    PORT
      LAYER M4 ;
        RECT  457.836 624.192 457.92 624.216 ;
    END
  END tap[319]
  PIN tap[31]
    DIRECTION INPUT ;
    USE SIGNAL ;
    PORT
      LAYER M4 ;
        RECT  457.836 567.936 457.92 567.96 ;
    END
  END tap[31]
  PIN tap[320]
    DIRECTION INPUT ;
    USE SIGNAL ;
    PORT
      LAYER M4 ;
        RECT  457.836 624.384 457.92 624.408 ;
    END
  END tap[320]
  PIN tap[321]
    DIRECTION INPUT ;
    USE SIGNAL ;
    PORT
      LAYER M4 ;
        RECT  457.836 624.576 457.92 624.6 ;
    END
  END tap[321]
  PIN tap[322]
    DIRECTION INPUT ;
    USE SIGNAL ;
    PORT
      LAYER M4 ;
        RECT  457.836 624.768 457.92 624.792 ;
    END
  END tap[322]
  PIN tap[323]
    DIRECTION INPUT ;
    USE SIGNAL ;
    PORT
      LAYER M4 ;
        RECT  457.836 624.96 457.92 624.984 ;
    END
  END tap[323]
  PIN tap[324]
    DIRECTION INPUT ;
    USE SIGNAL ;
    PORT
      LAYER M4 ;
        RECT  457.836 625.152 457.92 625.176 ;
    END
  END tap[324]
  PIN tap[325]
    DIRECTION INPUT ;
    USE SIGNAL ;
    PORT
      LAYER M4 ;
        RECT  457.836 625.344 457.92 625.368 ;
    END
  END tap[325]
  PIN tap[326]
    DIRECTION INPUT ;
    USE SIGNAL ;
    PORT
      LAYER M4 ;
        RECT  457.836 625.536 457.92 625.56 ;
    END
  END tap[326]
  PIN tap[327]
    DIRECTION INPUT ;
    USE SIGNAL ;
    PORT
      LAYER M4 ;
        RECT  457.836 625.728 457.92 625.752 ;
    END
  END tap[327]
  PIN tap[328]
    DIRECTION INPUT ;
    USE SIGNAL ;
    PORT
      LAYER M4 ;
        RECT  457.836 625.92 457.92 625.944 ;
    END
  END tap[328]
  PIN tap[329]
    DIRECTION INPUT ;
    USE SIGNAL ;
    PORT
      LAYER M4 ;
        RECT  457.836 626.112 457.92 626.136 ;
    END
  END tap[329]
  PIN tap[32]
    DIRECTION INPUT ;
    USE SIGNAL ;
    PORT
      LAYER M4 ;
        RECT  457.836 568.128 457.92 568.152 ;
    END
  END tap[32]
  PIN tap[330]
    DIRECTION INPUT ;
    USE SIGNAL ;
    PORT
      LAYER M4 ;
        RECT  457.836 626.304 457.92 626.328 ;
    END
  END tap[330]
  PIN tap[331]
    DIRECTION INPUT ;
    USE SIGNAL ;
    PORT
      LAYER M4 ;
        RECT  457.836 626.496 457.92 626.52 ;
    END
  END tap[331]
  PIN tap[332]
    DIRECTION INPUT ;
    USE SIGNAL ;
    PORT
      LAYER M4 ;
        RECT  457.836 626.688 457.92 626.712 ;
    END
  END tap[332]
  PIN tap[333]
    DIRECTION INPUT ;
    USE SIGNAL ;
    PORT
      LAYER M4 ;
        RECT  457.836 626.88 457.92 626.904 ;
    END
  END tap[333]
  PIN tap[334]
    DIRECTION INPUT ;
    USE SIGNAL ;
    PORT
      LAYER M4 ;
        RECT  457.836 627.072 457.92 627.096 ;
    END
  END tap[334]
  PIN tap[335]
    DIRECTION INPUT ;
    USE SIGNAL ;
    PORT
      LAYER M4 ;
        RECT  457.836 627.264 457.92 627.288 ;
    END
  END tap[335]
  PIN tap[336]
    DIRECTION INPUT ;
    USE SIGNAL ;
    PORT
      LAYER M4 ;
        RECT  457.836 627.456 457.92 627.48 ;
    END
  END tap[336]
  PIN tap[337]
    DIRECTION INPUT ;
    USE SIGNAL ;
    PORT
      LAYER M4 ;
        RECT  457.836 627.648 457.92 627.672 ;
    END
  END tap[337]
  PIN tap[338]
    DIRECTION INPUT ;
    USE SIGNAL ;
    PORT
      LAYER M4 ;
        RECT  457.836 627.84 457.92 627.864 ;
    END
  END tap[338]
  PIN tap[339]
    DIRECTION INPUT ;
    USE SIGNAL ;
    PORT
      LAYER M4 ;
        RECT  457.836 628.032 457.92 628.056 ;
    END
  END tap[339]
  PIN tap[33]
    DIRECTION INPUT ;
    USE SIGNAL ;
    PORT
      LAYER M4 ;
        RECT  457.836 568.32 457.92 568.344 ;
    END
  END tap[33]
  PIN tap[340]
    DIRECTION INPUT ;
    USE SIGNAL ;
    PORT
      LAYER M4 ;
        RECT  457.836 628.224 457.92 628.248 ;
    END
  END tap[340]
  PIN tap[341]
    DIRECTION INPUT ;
    USE SIGNAL ;
    PORT
      LAYER M4 ;
        RECT  457.836 628.416 457.92 628.44 ;
    END
  END tap[341]
  PIN tap[342]
    DIRECTION INPUT ;
    USE SIGNAL ;
    PORT
      LAYER M4 ;
        RECT  457.836 628.608 457.92 628.632 ;
    END
  END tap[342]
  PIN tap[343]
    DIRECTION INPUT ;
    USE SIGNAL ;
    PORT
      LAYER M4 ;
        RECT  457.836 628.8 457.92 628.824 ;
    END
  END tap[343]
  PIN tap[344]
    DIRECTION INPUT ;
    USE SIGNAL ;
    PORT
      LAYER M4 ;
        RECT  457.836 628.992 457.92 629.016 ;
    END
  END tap[344]
  PIN tap[345]
    DIRECTION INPUT ;
    USE SIGNAL ;
    PORT
      LAYER M4 ;
        RECT  457.836 629.184 457.92 629.208 ;
    END
  END tap[345]
  PIN tap[346]
    DIRECTION INPUT ;
    USE SIGNAL ;
    PORT
      LAYER M4 ;
        RECT  457.836 629.376 457.92 629.4 ;
    END
  END tap[346]
  PIN tap[347]
    DIRECTION INPUT ;
    USE SIGNAL ;
    PORT
      LAYER M4 ;
        RECT  457.836 629.568 457.92 629.592 ;
    END
  END tap[347]
  PIN tap[348]
    DIRECTION INPUT ;
    USE SIGNAL ;
    PORT
      LAYER M4 ;
        RECT  457.836 629.76 457.92 629.784 ;
    END
  END tap[348]
  PIN tap[349]
    DIRECTION INPUT ;
    USE SIGNAL ;
    PORT
      LAYER M4 ;
        RECT  457.836 629.952 457.92 629.976 ;
    END
  END tap[349]
  PIN tap[34]
    DIRECTION INPUT ;
    USE SIGNAL ;
    PORT
      LAYER M4 ;
        RECT  457.836 568.512 457.92 568.536 ;
    END
  END tap[34]
  PIN tap[350]
    DIRECTION INPUT ;
    USE SIGNAL ;
    PORT
      LAYER M4 ;
        RECT  457.836 630.144 457.92 630.168 ;
    END
  END tap[350]
  PIN tap[351]
    DIRECTION INPUT ;
    USE SIGNAL ;
    PORT
      LAYER M4 ;
        RECT  457.836 630.336 457.92 630.36 ;
    END
  END tap[351]
  PIN tap[352]
    DIRECTION INPUT ;
    USE SIGNAL ;
    PORT
      LAYER M4 ;
        RECT  457.836 630.528 457.92 630.552 ;
    END
  END tap[352]
  PIN tap[353]
    DIRECTION INPUT ;
    USE SIGNAL ;
    PORT
      LAYER M4 ;
        RECT  457.836 630.72 457.92 630.744 ;
    END
  END tap[353]
  PIN tap[354]
    DIRECTION INPUT ;
    USE SIGNAL ;
    PORT
      LAYER M4 ;
        RECT  457.836 630.912 457.92 630.936 ;
    END
  END tap[354]
  PIN tap[355]
    DIRECTION INPUT ;
    USE SIGNAL ;
    PORT
      LAYER M4 ;
        RECT  457.836 631.104 457.92 631.128 ;
    END
  END tap[355]
  PIN tap[356]
    DIRECTION INPUT ;
    USE SIGNAL ;
    PORT
      LAYER M4 ;
        RECT  457.836 631.296 457.92 631.32 ;
    END
  END tap[356]
  PIN tap[357]
    DIRECTION INPUT ;
    USE SIGNAL ;
    PORT
      LAYER M4 ;
        RECT  457.836 631.488 457.92 631.512 ;
    END
  END tap[357]
  PIN tap[358]
    DIRECTION INPUT ;
    USE SIGNAL ;
    PORT
      LAYER M4 ;
        RECT  457.836 631.68 457.92 631.704 ;
    END
  END tap[358]
  PIN tap[359]
    DIRECTION INPUT ;
    USE SIGNAL ;
    PORT
      LAYER M4 ;
        RECT  457.836 631.872 457.92 631.896 ;
    END
  END tap[359]
  PIN tap[35]
    DIRECTION INPUT ;
    USE SIGNAL ;
    PORT
      LAYER M4 ;
        RECT  457.836 568.704 457.92 568.728 ;
    END
  END tap[35]
  PIN tap[360]
    DIRECTION INPUT ;
    USE SIGNAL ;
    PORT
      LAYER M4 ;
        RECT  457.836 632.064 457.92 632.088 ;
    END
  END tap[360]
  PIN tap[361]
    DIRECTION INPUT ;
    USE SIGNAL ;
    PORT
      LAYER M4 ;
        RECT  457.836 632.256 457.92 632.28 ;
    END
  END tap[361]
  PIN tap[362]
    DIRECTION INPUT ;
    USE SIGNAL ;
    PORT
      LAYER M4 ;
        RECT  457.836 632.448 457.92 632.472 ;
    END
  END tap[362]
  PIN tap[363]
    DIRECTION INPUT ;
    USE SIGNAL ;
    PORT
      LAYER M4 ;
        RECT  457.836 632.64 457.92 632.664 ;
    END
  END tap[363]
  PIN tap[364]
    DIRECTION INPUT ;
    USE SIGNAL ;
    PORT
      LAYER M4 ;
        RECT  457.836 632.832 457.92 632.856 ;
    END
  END tap[364]
  PIN tap[365]
    DIRECTION INPUT ;
    USE SIGNAL ;
    PORT
      LAYER M4 ;
        RECT  457.836 633.024 457.92 633.048 ;
    END
  END tap[365]
  PIN tap[366]
    DIRECTION INPUT ;
    USE SIGNAL ;
    PORT
      LAYER M4 ;
        RECT  457.836 633.216 457.92 633.24 ;
    END
  END tap[366]
  PIN tap[367]
    DIRECTION INPUT ;
    USE SIGNAL ;
    PORT
      LAYER M4 ;
        RECT  457.836 633.408 457.92 633.432 ;
    END
  END tap[367]
  PIN tap[368]
    DIRECTION INPUT ;
    USE SIGNAL ;
    PORT
      LAYER M4 ;
        RECT  457.836 633.6 457.92 633.624 ;
    END
  END tap[368]
  PIN tap[369]
    DIRECTION INPUT ;
    USE SIGNAL ;
    PORT
      LAYER M4 ;
        RECT  457.836 633.792 457.92 633.816 ;
    END
  END tap[369]
  PIN tap[36]
    DIRECTION INPUT ;
    USE SIGNAL ;
    PORT
      LAYER M4 ;
        RECT  457.836 568.896 457.92 568.92 ;
    END
  END tap[36]
  PIN tap[370]
    DIRECTION INPUT ;
    USE SIGNAL ;
    PORT
      LAYER M4 ;
        RECT  457.836 633.984 457.92 634.008 ;
    END
  END tap[370]
  PIN tap[371]
    DIRECTION INPUT ;
    USE SIGNAL ;
    PORT
      LAYER M4 ;
        RECT  457.836 634.176 457.92 634.2 ;
    END
  END tap[371]
  PIN tap[372]
    DIRECTION INPUT ;
    USE SIGNAL ;
    PORT
      LAYER M4 ;
        RECT  457.836 634.368 457.92 634.392 ;
    END
  END tap[372]
  PIN tap[373]
    DIRECTION INPUT ;
    USE SIGNAL ;
    PORT
      LAYER M4 ;
        RECT  457.836 634.56 457.92 634.584 ;
    END
  END tap[373]
  PIN tap[374]
    DIRECTION INPUT ;
    USE SIGNAL ;
    PORT
      LAYER M4 ;
        RECT  457.836 634.752 457.92 634.776 ;
    END
  END tap[374]
  PIN tap[375]
    DIRECTION INPUT ;
    USE SIGNAL ;
    PORT
      LAYER M4 ;
        RECT  457.836 634.944 457.92 634.968 ;
    END
  END tap[375]
  PIN tap[376]
    DIRECTION INPUT ;
    USE SIGNAL ;
    PORT
      LAYER M4 ;
        RECT  457.836 635.136 457.92 635.16 ;
    END
  END tap[376]
  PIN tap[377]
    DIRECTION INPUT ;
    USE SIGNAL ;
    PORT
      LAYER M4 ;
        RECT  457.836 635.328 457.92 635.352 ;
    END
  END tap[377]
  PIN tap[378]
    DIRECTION INPUT ;
    USE SIGNAL ;
    PORT
      LAYER M4 ;
        RECT  457.836 635.52 457.92 635.544 ;
    END
  END tap[378]
  PIN tap[379]
    DIRECTION INPUT ;
    USE SIGNAL ;
    PORT
      LAYER M4 ;
        RECT  457.836 635.712 457.92 635.736 ;
    END
  END tap[379]
  PIN tap[37]
    DIRECTION INPUT ;
    USE SIGNAL ;
    PORT
      LAYER M4 ;
        RECT  457.836 569.088 457.92 569.112 ;
    END
  END tap[37]
  PIN tap[380]
    DIRECTION INPUT ;
    USE SIGNAL ;
    PORT
      LAYER M4 ;
        RECT  457.836 635.904 457.92 635.928 ;
    END
  END tap[380]
  PIN tap[381]
    DIRECTION INPUT ;
    USE SIGNAL ;
    PORT
      LAYER M4 ;
        RECT  457.836 636.096 457.92 636.12 ;
    END
  END tap[381]
  PIN tap[382]
    DIRECTION INPUT ;
    USE SIGNAL ;
    PORT
      LAYER M4 ;
        RECT  457.836 636.288 457.92 636.312 ;
    END
  END tap[382]
  PIN tap[383]
    DIRECTION INPUT ;
    USE SIGNAL ;
    PORT
      LAYER M4 ;
        RECT  457.836 636.48 457.92 636.504 ;
    END
  END tap[383]
  PIN tap[384]
    DIRECTION INPUT ;
    USE SIGNAL ;
    PORT
      LAYER M4 ;
        RECT  457.836 636.672 457.92 636.696 ;
    END
  END tap[384]
  PIN tap[385]
    DIRECTION INPUT ;
    USE SIGNAL ;
    PORT
      LAYER M4 ;
        RECT  457.836 636.864 457.92 636.888 ;
    END
  END tap[385]
  PIN tap[386]
    DIRECTION INPUT ;
    USE SIGNAL ;
    PORT
      LAYER M4 ;
        RECT  457.836 637.056 457.92 637.08 ;
    END
  END tap[386]
  PIN tap[387]
    DIRECTION INPUT ;
    USE SIGNAL ;
    PORT
      LAYER M4 ;
        RECT  457.836 637.248 457.92 637.272 ;
    END
  END tap[387]
  PIN tap[388]
    DIRECTION INPUT ;
    USE SIGNAL ;
    PORT
      LAYER M4 ;
        RECT  457.836 637.44 457.92 637.464 ;
    END
  END tap[388]
  PIN tap[389]
    DIRECTION INPUT ;
    USE SIGNAL ;
    PORT
      LAYER M4 ;
        RECT  457.836 637.632 457.92 637.656 ;
    END
  END tap[389]
  PIN tap[38]
    DIRECTION INPUT ;
    USE SIGNAL ;
    PORT
      LAYER M4 ;
        RECT  457.836 569.28 457.92 569.304 ;
    END
  END tap[38]
  PIN tap[390]
    DIRECTION INPUT ;
    USE SIGNAL ;
    PORT
      LAYER M4 ;
        RECT  457.836 637.824 457.92 637.848 ;
    END
  END tap[390]
  PIN tap[391]
    DIRECTION INPUT ;
    USE SIGNAL ;
    PORT
      LAYER M4 ;
        RECT  457.836 638.016 457.92 638.04 ;
    END
  END tap[391]
  PIN tap[392]
    DIRECTION INPUT ;
    USE SIGNAL ;
    PORT
      LAYER M4 ;
        RECT  457.836 638.208 457.92 638.232 ;
    END
  END tap[392]
  PIN tap[393]
    DIRECTION INPUT ;
    USE SIGNAL ;
    PORT
      LAYER M4 ;
        RECT  457.836 638.4 457.92 638.424 ;
    END
  END tap[393]
  PIN tap[394]
    DIRECTION INPUT ;
    USE SIGNAL ;
    PORT
      LAYER M4 ;
        RECT  457.836 638.592 457.92 638.616 ;
    END
  END tap[394]
  PIN tap[395]
    DIRECTION INPUT ;
    USE SIGNAL ;
    PORT
      LAYER M4 ;
        RECT  457.836 638.784 457.92 638.808 ;
    END
  END tap[395]
  PIN tap[396]
    DIRECTION INPUT ;
    USE SIGNAL ;
    PORT
      LAYER M4 ;
        RECT  457.836 638.976 457.92 639 ;
    END
  END tap[396]
  PIN tap[397]
    DIRECTION INPUT ;
    USE SIGNAL ;
    PORT
      LAYER M4 ;
        RECT  457.836 639.168 457.92 639.192 ;
    END
  END tap[397]
  PIN tap[398]
    DIRECTION INPUT ;
    USE SIGNAL ;
    PORT
      LAYER M4 ;
        RECT  457.836 639.36 457.92 639.384 ;
    END
  END tap[398]
  PIN tap[399]
    DIRECTION INPUT ;
    USE SIGNAL ;
    PORT
      LAYER M4 ;
        RECT  457.836 639.552 457.92 639.576 ;
    END
  END tap[399]
  PIN tap[39]
    DIRECTION INPUT ;
    USE SIGNAL ;
    PORT
      LAYER M4 ;
        RECT  457.836 569.472 457.92 569.496 ;
    END
  END tap[39]
  PIN tap[3]
    DIRECTION INPUT ;
    USE SIGNAL ;
    PORT
      LAYER M4 ;
        RECT  457.836 561.6 457.92 561.624 ;
    END
  END tap[3]
  PIN tap[400]
    DIRECTION INPUT ;
    USE SIGNAL ;
    PORT
      LAYER M4 ;
        RECT  457.836 639.744 457.92 639.768 ;
    END
  END tap[400]
  PIN tap[401]
    DIRECTION INPUT ;
    USE SIGNAL ;
    PORT
      LAYER M4 ;
        RECT  457.836 639.936 457.92 639.96 ;
    END
  END tap[401]
  PIN tap[402]
    DIRECTION INPUT ;
    USE SIGNAL ;
    PORT
      LAYER M4 ;
        RECT  457.836 640.128 457.92 640.152 ;
    END
  END tap[402]
  PIN tap[403]
    DIRECTION INPUT ;
    USE SIGNAL ;
    PORT
      LAYER M4 ;
        RECT  457.836 640.32 457.92 640.344 ;
    END
  END tap[403]
  PIN tap[404]
    DIRECTION INPUT ;
    USE SIGNAL ;
    PORT
      LAYER M4 ;
        RECT  457.836 640.512 457.92 640.536 ;
    END
  END tap[404]
  PIN tap[405]
    DIRECTION INPUT ;
    USE SIGNAL ;
    PORT
      LAYER M4 ;
        RECT  457.836 640.704 457.92 640.728 ;
    END
  END tap[405]
  PIN tap[406]
    DIRECTION INPUT ;
    USE SIGNAL ;
    PORT
      LAYER M4 ;
        RECT  457.836 640.896 457.92 640.92 ;
    END
  END tap[406]
  PIN tap[407]
    DIRECTION INPUT ;
    USE SIGNAL ;
    PORT
      LAYER M4 ;
        RECT  457.836 641.088 457.92 641.112 ;
    END
  END tap[407]
  PIN tap[408]
    DIRECTION INPUT ;
    USE SIGNAL ;
    PORT
      LAYER M4 ;
        RECT  457.836 641.28 457.92 641.304 ;
    END
  END tap[408]
  PIN tap[409]
    DIRECTION INPUT ;
    USE SIGNAL ;
    PORT
      LAYER M4 ;
        RECT  457.836 641.472 457.92 641.496 ;
    END
  END tap[409]
  PIN tap[40]
    DIRECTION INPUT ;
    USE SIGNAL ;
    PORT
      LAYER M4 ;
        RECT  457.836 569.664 457.92 569.688 ;
    END
  END tap[40]
  PIN tap[410]
    DIRECTION INPUT ;
    USE SIGNAL ;
    PORT
      LAYER M4 ;
        RECT  457.836 641.664 457.92 641.688 ;
    END
  END tap[410]
  PIN tap[411]
    DIRECTION INPUT ;
    USE SIGNAL ;
    PORT
      LAYER M4 ;
        RECT  457.836 641.856 457.92 641.88 ;
    END
  END tap[411]
  PIN tap[412]
    DIRECTION INPUT ;
    USE SIGNAL ;
    PORT
      LAYER M4 ;
        RECT  457.836 642.048 457.92 642.072 ;
    END
  END tap[412]
  PIN tap[413]
    DIRECTION INPUT ;
    USE SIGNAL ;
    PORT
      LAYER M4 ;
        RECT  457.836 642.24 457.92 642.264 ;
    END
  END tap[413]
  PIN tap[414]
    DIRECTION INPUT ;
    USE SIGNAL ;
    PORT
      LAYER M4 ;
        RECT  457.836 642.432 457.92 642.456 ;
    END
  END tap[414]
  PIN tap[415]
    DIRECTION INPUT ;
    USE SIGNAL ;
    PORT
      LAYER M4 ;
        RECT  457.836 642.624 457.92 642.648 ;
    END
  END tap[415]
  PIN tap[416]
    DIRECTION INPUT ;
    USE SIGNAL ;
    PORT
      LAYER M4 ;
        RECT  457.836 642.816 457.92 642.84 ;
    END
  END tap[416]
  PIN tap[417]
    DIRECTION INPUT ;
    USE SIGNAL ;
    PORT
      LAYER M4 ;
        RECT  457.836 643.008 457.92 643.032 ;
    END
  END tap[417]
  PIN tap[418]
    DIRECTION INPUT ;
    USE SIGNAL ;
    PORT
      LAYER M4 ;
        RECT  457.836 643.2 457.92 643.224 ;
    END
  END tap[418]
  PIN tap[419]
    DIRECTION INPUT ;
    USE SIGNAL ;
    PORT
      LAYER M4 ;
        RECT  457.836 643.392 457.92 643.416 ;
    END
  END tap[419]
  PIN tap[41]
    DIRECTION INPUT ;
    USE SIGNAL ;
    PORT
      LAYER M4 ;
        RECT  457.836 569.856 457.92 569.88 ;
    END
  END tap[41]
  PIN tap[420]
    DIRECTION INPUT ;
    USE SIGNAL ;
    PORT
      LAYER M4 ;
        RECT  457.836 643.584 457.92 643.608 ;
    END
  END tap[420]
  PIN tap[421]
    DIRECTION INPUT ;
    USE SIGNAL ;
    PORT
      LAYER M4 ;
        RECT  457.836 643.776 457.92 643.8 ;
    END
  END tap[421]
  PIN tap[422]
    DIRECTION INPUT ;
    USE SIGNAL ;
    PORT
      LAYER M4 ;
        RECT  457.836 643.968 457.92 643.992 ;
    END
  END tap[422]
  PIN tap[423]
    DIRECTION INPUT ;
    USE SIGNAL ;
    PORT
      LAYER M4 ;
        RECT  457.836 644.16 457.92 644.184 ;
    END
  END tap[423]
  PIN tap[424]
    DIRECTION INPUT ;
    USE SIGNAL ;
    PORT
      LAYER M4 ;
        RECT  457.836 644.352 457.92 644.376 ;
    END
  END tap[424]
  PIN tap[425]
    DIRECTION INPUT ;
    USE SIGNAL ;
    PORT
      LAYER M4 ;
        RECT  457.836 644.544 457.92 644.568 ;
    END
  END tap[425]
  PIN tap[426]
    DIRECTION INPUT ;
    USE SIGNAL ;
    PORT
      LAYER M4 ;
        RECT  457.836 644.736 457.92 644.76 ;
    END
  END tap[426]
  PIN tap[427]
    DIRECTION INPUT ;
    USE SIGNAL ;
    PORT
      LAYER M4 ;
        RECT  457.836 644.928 457.92 644.952 ;
    END
  END tap[427]
  PIN tap[428]
    DIRECTION INPUT ;
    USE SIGNAL ;
    PORT
      LAYER M4 ;
        RECT  457.836 645.12 457.92 645.144 ;
    END
  END tap[428]
  PIN tap[429]
    DIRECTION INPUT ;
    USE SIGNAL ;
    PORT
      LAYER M4 ;
        RECT  457.836 645.312 457.92 645.336 ;
    END
  END tap[429]
  PIN tap[42]
    DIRECTION INPUT ;
    USE SIGNAL ;
    PORT
      LAYER M4 ;
        RECT  457.836 570.048 457.92 570.072 ;
    END
  END tap[42]
  PIN tap[430]
    DIRECTION INPUT ;
    USE SIGNAL ;
    PORT
      LAYER M4 ;
        RECT  457.836 645.504 457.92 645.528 ;
    END
  END tap[430]
  PIN tap[431]
    DIRECTION INPUT ;
    USE SIGNAL ;
    PORT
      LAYER M4 ;
        RECT  457.836 645.696 457.92 645.72 ;
    END
  END tap[431]
  PIN tap[432]
    DIRECTION INPUT ;
    USE SIGNAL ;
    PORT
      LAYER M4 ;
        RECT  457.836 645.888 457.92 645.912 ;
    END
  END tap[432]
  PIN tap[433]
    DIRECTION INPUT ;
    USE SIGNAL ;
    PORT
      LAYER M4 ;
        RECT  457.836 646.08 457.92 646.104 ;
    END
  END tap[433]
  PIN tap[434]
    DIRECTION INPUT ;
    USE SIGNAL ;
    PORT
      LAYER M4 ;
        RECT  457.836 646.272 457.92 646.296 ;
    END
  END tap[434]
  PIN tap[435]
    DIRECTION INPUT ;
    USE SIGNAL ;
    PORT
      LAYER M4 ;
        RECT  457.836 646.464 457.92 646.488 ;
    END
  END tap[435]
  PIN tap[436]
    DIRECTION INPUT ;
    USE SIGNAL ;
    PORT
      LAYER M4 ;
        RECT  457.836 646.656 457.92 646.68 ;
    END
  END tap[436]
  PIN tap[437]
    DIRECTION INPUT ;
    USE SIGNAL ;
    PORT
      LAYER M4 ;
        RECT  457.836 646.848 457.92 646.872 ;
    END
  END tap[437]
  PIN tap[438]
    DIRECTION INPUT ;
    USE SIGNAL ;
    PORT
      LAYER M4 ;
        RECT  457.836 647.04 457.92 647.064 ;
    END
  END tap[438]
  PIN tap[439]
    DIRECTION INPUT ;
    USE SIGNAL ;
    PORT
      LAYER M4 ;
        RECT  457.836 647.232 457.92 647.256 ;
    END
  END tap[439]
  PIN tap[43]
    DIRECTION INPUT ;
    USE SIGNAL ;
    PORT
      LAYER M4 ;
        RECT  457.836 570.24 457.92 570.264 ;
    END
  END tap[43]
  PIN tap[440]
    DIRECTION INPUT ;
    USE SIGNAL ;
    PORT
      LAYER M4 ;
        RECT  457.836 647.424 457.92 647.448 ;
    END
  END tap[440]
  PIN tap[441]
    DIRECTION INPUT ;
    USE SIGNAL ;
    PORT
      LAYER M4 ;
        RECT  457.836 647.616 457.92 647.64 ;
    END
  END tap[441]
  PIN tap[442]
    DIRECTION INPUT ;
    USE SIGNAL ;
    PORT
      LAYER M4 ;
        RECT  457.836 647.808 457.92 647.832 ;
    END
  END tap[442]
  PIN tap[443]
    DIRECTION INPUT ;
    USE SIGNAL ;
    PORT
      LAYER M4 ;
        RECT  457.836 648 457.92 648.024 ;
    END
  END tap[443]
  PIN tap[444]
    DIRECTION INPUT ;
    USE SIGNAL ;
    PORT
      LAYER M4 ;
        RECT  457.836 648.192 457.92 648.216 ;
    END
  END tap[444]
  PIN tap[445]
    DIRECTION INPUT ;
    USE SIGNAL ;
    PORT
      LAYER M4 ;
        RECT  457.836 648.384 457.92 648.408 ;
    END
  END tap[445]
  PIN tap[446]
    DIRECTION INPUT ;
    USE SIGNAL ;
    PORT
      LAYER M4 ;
        RECT  457.836 648.576 457.92 648.6 ;
    END
  END tap[446]
  PIN tap[447]
    DIRECTION INPUT ;
    USE SIGNAL ;
    PORT
      LAYER M4 ;
        RECT  457.836 648.768 457.92 648.792 ;
    END
  END tap[447]
  PIN tap[448]
    DIRECTION INPUT ;
    USE SIGNAL ;
    PORT
      LAYER M4 ;
        RECT  457.836 648.96 457.92 648.984 ;
    END
  END tap[448]
  PIN tap[449]
    DIRECTION INPUT ;
    USE SIGNAL ;
    PORT
      LAYER M4 ;
        RECT  457.836 649.152 457.92 649.176 ;
    END
  END tap[449]
  PIN tap[44]
    DIRECTION INPUT ;
    USE SIGNAL ;
    PORT
      LAYER M4 ;
        RECT  457.836 570.432 457.92 570.456 ;
    END
  END tap[44]
  PIN tap[450]
    DIRECTION INPUT ;
    USE SIGNAL ;
    PORT
      LAYER M4 ;
        RECT  457.836 649.344 457.92 649.368 ;
    END
  END tap[450]
  PIN tap[451]
    DIRECTION INPUT ;
    USE SIGNAL ;
    PORT
      LAYER M4 ;
        RECT  457.836 649.536 457.92 649.56 ;
    END
  END tap[451]
  PIN tap[452]
    DIRECTION INPUT ;
    USE SIGNAL ;
    PORT
      LAYER M4 ;
        RECT  457.836 649.728 457.92 649.752 ;
    END
  END tap[452]
  PIN tap[453]
    DIRECTION INPUT ;
    USE SIGNAL ;
    PORT
      LAYER M4 ;
        RECT  457.836 649.92 457.92 649.944 ;
    END
  END tap[453]
  PIN tap[454]
    DIRECTION INPUT ;
    USE SIGNAL ;
    PORT
      LAYER M4 ;
        RECT  457.836 650.112 457.92 650.136 ;
    END
  END tap[454]
  PIN tap[455]
    DIRECTION INPUT ;
    USE SIGNAL ;
    PORT
      LAYER M4 ;
        RECT  457.836 650.304 457.92 650.328 ;
    END
  END tap[455]
  PIN tap[456]
    DIRECTION INPUT ;
    USE SIGNAL ;
    PORT
      LAYER M4 ;
        RECT  457.836 650.496 457.92 650.52 ;
    END
  END tap[456]
  PIN tap[457]
    DIRECTION INPUT ;
    USE SIGNAL ;
    PORT
      LAYER M4 ;
        RECT  457.836 650.688 457.92 650.712 ;
    END
  END tap[457]
  PIN tap[458]
    DIRECTION INPUT ;
    USE SIGNAL ;
    PORT
      LAYER M4 ;
        RECT  457.836 650.88 457.92 650.904 ;
    END
  END tap[458]
  PIN tap[459]
    DIRECTION INPUT ;
    USE SIGNAL ;
    PORT
      LAYER M4 ;
        RECT  457.836 651.072 457.92 651.096 ;
    END
  END tap[459]
  PIN tap[45]
    DIRECTION INPUT ;
    USE SIGNAL ;
    PORT
      LAYER M4 ;
        RECT  457.836 570.624 457.92 570.648 ;
    END
  END tap[45]
  PIN tap[460]
    DIRECTION INPUT ;
    USE SIGNAL ;
    PORT
      LAYER M4 ;
        RECT  457.836 651.264 457.92 651.288 ;
    END
  END tap[460]
  PIN tap[461]
    DIRECTION INPUT ;
    USE SIGNAL ;
    PORT
      LAYER M4 ;
        RECT  457.836 651.456 457.92 651.48 ;
    END
  END tap[461]
  PIN tap[462]
    DIRECTION INPUT ;
    USE SIGNAL ;
    PORT
      LAYER M4 ;
        RECT  457.836 651.648 457.92 651.672 ;
    END
  END tap[462]
  PIN tap[463]
    DIRECTION INPUT ;
    USE SIGNAL ;
    PORT
      LAYER M4 ;
        RECT  457.836 651.84 457.92 651.864 ;
    END
  END tap[463]
  PIN tap[464]
    DIRECTION INPUT ;
    USE SIGNAL ;
    PORT
      LAYER M4 ;
        RECT  457.836 652.032 457.92 652.056 ;
    END
  END tap[464]
  PIN tap[465]
    DIRECTION INPUT ;
    USE SIGNAL ;
    PORT
      LAYER M4 ;
        RECT  457.836 652.224 457.92 652.248 ;
    END
  END tap[465]
  PIN tap[466]
    DIRECTION INPUT ;
    USE SIGNAL ;
    PORT
      LAYER M4 ;
        RECT  457.836 652.416 457.92 652.44 ;
    END
  END tap[466]
  PIN tap[467]
    DIRECTION INPUT ;
    USE SIGNAL ;
    PORT
      LAYER M4 ;
        RECT  457.836 652.608 457.92 652.632 ;
    END
  END tap[467]
  PIN tap[468]
    DIRECTION INPUT ;
    USE SIGNAL ;
    PORT
      LAYER M4 ;
        RECT  457.836 652.8 457.92 652.824 ;
    END
  END tap[468]
  PIN tap[469]
    DIRECTION INPUT ;
    USE SIGNAL ;
    PORT
      LAYER M4 ;
        RECT  457.836 652.992 457.92 653.016 ;
    END
  END tap[469]
  PIN tap[46]
    DIRECTION INPUT ;
    USE SIGNAL ;
    PORT
      LAYER M4 ;
        RECT  457.836 570.816 457.92 570.84 ;
    END
  END tap[46]
  PIN tap[470]
    DIRECTION INPUT ;
    USE SIGNAL ;
    PORT
      LAYER M4 ;
        RECT  457.836 653.184 457.92 653.208 ;
    END
  END tap[470]
  PIN tap[471]
    DIRECTION INPUT ;
    USE SIGNAL ;
    PORT
      LAYER M4 ;
        RECT  457.836 653.376 457.92 653.4 ;
    END
  END tap[471]
  PIN tap[472]
    DIRECTION INPUT ;
    USE SIGNAL ;
    PORT
      LAYER M4 ;
        RECT  457.836 653.568 457.92 653.592 ;
    END
  END tap[472]
  PIN tap[473]
    DIRECTION INPUT ;
    USE SIGNAL ;
    PORT
      LAYER M4 ;
        RECT  457.836 653.76 457.92 653.784 ;
    END
  END tap[473]
  PIN tap[474]
    DIRECTION INPUT ;
    USE SIGNAL ;
    PORT
      LAYER M4 ;
        RECT  457.836 653.952 457.92 653.976 ;
    END
  END tap[474]
  PIN tap[475]
    DIRECTION INPUT ;
    USE SIGNAL ;
    PORT
      LAYER M4 ;
        RECT  457.836 654.144 457.92 654.168 ;
    END
  END tap[475]
  PIN tap[476]
    DIRECTION INPUT ;
    USE SIGNAL ;
    PORT
      LAYER M4 ;
        RECT  457.836 654.336 457.92 654.36 ;
    END
  END tap[476]
  PIN tap[477]
    DIRECTION INPUT ;
    USE SIGNAL ;
    PORT
      LAYER M4 ;
        RECT  457.836 654.528 457.92 654.552 ;
    END
  END tap[477]
  PIN tap[478]
    DIRECTION INPUT ;
    USE SIGNAL ;
    PORT
      LAYER M4 ;
        RECT  457.836 654.72 457.92 654.744 ;
    END
  END tap[478]
  PIN tap[479]
    DIRECTION INPUT ;
    USE SIGNAL ;
    PORT
      LAYER M4 ;
        RECT  457.836 654.912 457.92 654.936 ;
    END
  END tap[479]
  PIN tap[47]
    DIRECTION INPUT ;
    USE SIGNAL ;
    PORT
      LAYER M4 ;
        RECT  457.836 571.008 457.92 571.032 ;
    END
  END tap[47]
  PIN tap[480]
    DIRECTION INPUT ;
    USE SIGNAL ;
    PORT
      LAYER M4 ;
        RECT  457.836 655.104 457.92 655.128 ;
    END
  END tap[480]
  PIN tap[481]
    DIRECTION INPUT ;
    USE SIGNAL ;
    PORT
      LAYER M4 ;
        RECT  457.836 655.296 457.92 655.32 ;
    END
  END tap[481]
  PIN tap[482]
    DIRECTION INPUT ;
    USE SIGNAL ;
    PORT
      LAYER M4 ;
        RECT  457.836 655.488 457.92 655.512 ;
    END
  END tap[482]
  PIN tap[483]
    DIRECTION INPUT ;
    USE SIGNAL ;
    PORT
      LAYER M4 ;
        RECT  457.836 655.68 457.92 655.704 ;
    END
  END tap[483]
  PIN tap[484]
    DIRECTION INPUT ;
    USE SIGNAL ;
    PORT
      LAYER M4 ;
        RECT  457.836 655.872 457.92 655.896 ;
    END
  END tap[484]
  PIN tap[485]
    DIRECTION INPUT ;
    USE SIGNAL ;
    PORT
      LAYER M4 ;
        RECT  457.836 656.064 457.92 656.088 ;
    END
  END tap[485]
  PIN tap[486]
    DIRECTION INPUT ;
    USE SIGNAL ;
    PORT
      LAYER M4 ;
        RECT  457.836 656.256 457.92 656.28 ;
    END
  END tap[486]
  PIN tap[487]
    DIRECTION INPUT ;
    USE SIGNAL ;
    PORT
      LAYER M4 ;
        RECT  457.836 656.448 457.92 656.472 ;
    END
  END tap[487]
  PIN tap[488]
    DIRECTION INPUT ;
    USE SIGNAL ;
    PORT
      LAYER M4 ;
        RECT  457.836 656.64 457.92 656.664 ;
    END
  END tap[488]
  PIN tap[489]
    DIRECTION INPUT ;
    USE SIGNAL ;
    PORT
      LAYER M4 ;
        RECT  457.836 656.832 457.92 656.856 ;
    END
  END tap[489]
  PIN tap[48]
    DIRECTION INPUT ;
    USE SIGNAL ;
    PORT
      LAYER M4 ;
        RECT  457.836 571.2 457.92 571.224 ;
    END
  END tap[48]
  PIN tap[490]
    DIRECTION INPUT ;
    USE SIGNAL ;
    PORT
      LAYER M4 ;
        RECT  457.836 657.024 457.92 657.048 ;
    END
  END tap[490]
  PIN tap[491]
    DIRECTION INPUT ;
    USE SIGNAL ;
    PORT
      LAYER M4 ;
        RECT  457.836 657.216 457.92 657.24 ;
    END
  END tap[491]
  PIN tap[492]
    DIRECTION INPUT ;
    USE SIGNAL ;
    PORT
      LAYER M4 ;
        RECT  457.836 657.408 457.92 657.432 ;
    END
  END tap[492]
  PIN tap[493]
    DIRECTION INPUT ;
    USE SIGNAL ;
    PORT
      LAYER M4 ;
        RECT  457.836 657.6 457.92 657.624 ;
    END
  END tap[493]
  PIN tap[494]
    DIRECTION INPUT ;
    USE SIGNAL ;
    PORT
      LAYER M4 ;
        RECT  457.836 657.792 457.92 657.816 ;
    END
  END tap[494]
  PIN tap[495]
    DIRECTION INPUT ;
    USE SIGNAL ;
    PORT
      LAYER M4 ;
        RECT  457.836 657.984 457.92 658.008 ;
    END
  END tap[495]
  PIN tap[496]
    DIRECTION INPUT ;
    USE SIGNAL ;
    PORT
      LAYER M4 ;
        RECT  457.836 658.176 457.92 658.2 ;
    END
  END tap[496]
  PIN tap[497]
    DIRECTION INPUT ;
    USE SIGNAL ;
    PORT
      LAYER M4 ;
        RECT  457.836 658.368 457.92 658.392 ;
    END
  END tap[497]
  PIN tap[498]
    DIRECTION INPUT ;
    USE SIGNAL ;
    PORT
      LAYER M4 ;
        RECT  457.836 658.56 457.92 658.584 ;
    END
  END tap[498]
  PIN tap[499]
    DIRECTION INPUT ;
    USE SIGNAL ;
    PORT
      LAYER M4 ;
        RECT  457.836 658.752 457.92 658.776 ;
    END
  END tap[499]
  PIN tap[49]
    DIRECTION INPUT ;
    USE SIGNAL ;
    PORT
      LAYER M4 ;
        RECT  457.836 571.392 457.92 571.416 ;
    END
  END tap[49]
  PIN tap[4]
    DIRECTION INPUT ;
    USE SIGNAL ;
    PORT
      LAYER M4 ;
        RECT  457.836 561.792 457.92 561.816 ;
    END
  END tap[4]
  PIN tap[500]
    DIRECTION INPUT ;
    USE SIGNAL ;
    PORT
      LAYER M4 ;
        RECT  457.836 658.944 457.92 658.968 ;
    END
  END tap[500]
  PIN tap[501]
    DIRECTION INPUT ;
    USE SIGNAL ;
    PORT
      LAYER M4 ;
        RECT  457.836 659.136 457.92 659.16 ;
    END
  END tap[501]
  PIN tap[502]
    DIRECTION INPUT ;
    USE SIGNAL ;
    PORT
      LAYER M4 ;
        RECT  457.836 659.328 457.92 659.352 ;
    END
  END tap[502]
  PIN tap[503]
    DIRECTION INPUT ;
    USE SIGNAL ;
    PORT
      LAYER M4 ;
        RECT  457.836 659.52 457.92 659.544 ;
    END
  END tap[503]
  PIN tap[504]
    DIRECTION INPUT ;
    USE SIGNAL ;
    PORT
      LAYER M4 ;
        RECT  457.836 659.712 457.92 659.736 ;
    END
  END tap[504]
  PIN tap[505]
    DIRECTION INPUT ;
    USE SIGNAL ;
    PORT
      LAYER M4 ;
        RECT  457.836 659.904 457.92 659.928 ;
    END
  END tap[505]
  PIN tap[506]
    DIRECTION INPUT ;
    USE SIGNAL ;
    PORT
      LAYER M4 ;
        RECT  457.836 660.096 457.92 660.12 ;
    END
  END tap[506]
  PIN tap[507]
    DIRECTION INPUT ;
    USE SIGNAL ;
    PORT
      LAYER M4 ;
        RECT  457.836 660.288 457.92 660.312 ;
    END
  END tap[507]
  PIN tap[50]
    DIRECTION INPUT ;
    USE SIGNAL ;
    PORT
      LAYER M4 ;
        RECT  457.836 571.584 457.92 571.608 ;
    END
  END tap[50]
  PIN tap[51]
    DIRECTION INPUT ;
    USE SIGNAL ;
    PORT
      LAYER M4 ;
        RECT  457.836 571.776 457.92 571.8 ;
    END
  END tap[51]
  PIN tap[52]
    DIRECTION INPUT ;
    USE SIGNAL ;
    PORT
      LAYER M4 ;
        RECT  457.836 571.968 457.92 571.992 ;
    END
  END tap[52]
  PIN tap[53]
    DIRECTION INPUT ;
    USE SIGNAL ;
    PORT
      LAYER M4 ;
        RECT  457.836 572.16 457.92 572.184 ;
    END
  END tap[53]
  PIN tap[54]
    DIRECTION INPUT ;
    USE SIGNAL ;
    PORT
      LAYER M4 ;
        RECT  457.836 572.352 457.92 572.376 ;
    END
  END tap[54]
  PIN tap[55]
    DIRECTION INPUT ;
    USE SIGNAL ;
    PORT
      LAYER M4 ;
        RECT  457.836 572.544 457.92 572.568 ;
    END
  END tap[55]
  PIN tap[56]
    DIRECTION INPUT ;
    USE SIGNAL ;
    PORT
      LAYER M4 ;
        RECT  457.836 572.736 457.92 572.76 ;
    END
  END tap[56]
  PIN tap[57]
    DIRECTION INPUT ;
    USE SIGNAL ;
    PORT
      LAYER M4 ;
        RECT  457.836 572.928 457.92 572.952 ;
    END
  END tap[57]
  PIN tap[58]
    DIRECTION INPUT ;
    USE SIGNAL ;
    PORT
      LAYER M4 ;
        RECT  457.836 573.12 457.92 573.144 ;
    END
  END tap[58]
  PIN tap[59]
    DIRECTION INPUT ;
    USE SIGNAL ;
    PORT
      LAYER M4 ;
        RECT  457.836 573.312 457.92 573.336 ;
    END
  END tap[59]
  PIN tap[5]
    DIRECTION INPUT ;
    USE SIGNAL ;
    PORT
      LAYER M4 ;
        RECT  457.836 561.984 457.92 562.008 ;
    END
  END tap[5]
  PIN tap[60]
    DIRECTION INPUT ;
    USE SIGNAL ;
    PORT
      LAYER M4 ;
        RECT  457.836 573.504 457.92 573.528 ;
    END
  END tap[60]
  PIN tap[61]
    DIRECTION INPUT ;
    USE SIGNAL ;
    PORT
      LAYER M4 ;
        RECT  457.836 573.696 457.92 573.72 ;
    END
  END tap[61]
  PIN tap[62]
    DIRECTION INPUT ;
    USE SIGNAL ;
    PORT
      LAYER M4 ;
        RECT  457.836 573.888 457.92 573.912 ;
    END
  END tap[62]
  PIN tap[63]
    DIRECTION INPUT ;
    USE SIGNAL ;
    PORT
      LAYER M4 ;
        RECT  457.836 574.08 457.92 574.104 ;
    END
  END tap[63]
  PIN tap[64]
    DIRECTION INPUT ;
    USE SIGNAL ;
    PORT
      LAYER M4 ;
        RECT  457.836 574.272 457.92 574.296 ;
    END
  END tap[64]
  PIN tap[65]
    DIRECTION INPUT ;
    USE SIGNAL ;
    PORT
      LAYER M4 ;
        RECT  457.836 574.464 457.92 574.488 ;
    END
  END tap[65]
  PIN tap[66]
    DIRECTION INPUT ;
    USE SIGNAL ;
    PORT
      LAYER M4 ;
        RECT  457.836 574.656 457.92 574.68 ;
    END
  END tap[66]
  PIN tap[67]
    DIRECTION INPUT ;
    USE SIGNAL ;
    PORT
      LAYER M4 ;
        RECT  457.836 574.848 457.92 574.872 ;
    END
  END tap[67]
  PIN tap[68]
    DIRECTION INPUT ;
    USE SIGNAL ;
    PORT
      LAYER M4 ;
        RECT  457.836 575.04 457.92 575.064 ;
    END
  END tap[68]
  PIN tap[69]
    DIRECTION INPUT ;
    USE SIGNAL ;
    PORT
      LAYER M4 ;
        RECT  457.836 575.232 457.92 575.256 ;
    END
  END tap[69]
  PIN tap[6]
    DIRECTION INPUT ;
    USE SIGNAL ;
    PORT
      LAYER M4 ;
        RECT  457.836 562.176 457.92 562.2 ;
    END
  END tap[6]
  PIN tap[70]
    DIRECTION INPUT ;
    USE SIGNAL ;
    PORT
      LAYER M4 ;
        RECT  457.836 575.424 457.92 575.448 ;
    END
  END tap[70]
  PIN tap[71]
    DIRECTION INPUT ;
    USE SIGNAL ;
    PORT
      LAYER M4 ;
        RECT  457.836 575.616 457.92 575.64 ;
    END
  END tap[71]
  PIN tap[72]
    DIRECTION INPUT ;
    USE SIGNAL ;
    PORT
      LAYER M4 ;
        RECT  457.836 575.808 457.92 575.832 ;
    END
  END tap[72]
  PIN tap[73]
    DIRECTION INPUT ;
    USE SIGNAL ;
    PORT
      LAYER M4 ;
        RECT  457.836 576 457.92 576.024 ;
    END
  END tap[73]
  PIN tap[74]
    DIRECTION INPUT ;
    USE SIGNAL ;
    PORT
      LAYER M4 ;
        RECT  457.836 576.192 457.92 576.216 ;
    END
  END tap[74]
  PIN tap[75]
    DIRECTION INPUT ;
    USE SIGNAL ;
    PORT
      LAYER M4 ;
        RECT  457.836 576.384 457.92 576.408 ;
    END
  END tap[75]
  PIN tap[76]
    DIRECTION INPUT ;
    USE SIGNAL ;
    PORT
      LAYER M4 ;
        RECT  457.836 576.576 457.92 576.6 ;
    END
  END tap[76]
  PIN tap[77]
    DIRECTION INPUT ;
    USE SIGNAL ;
    PORT
      LAYER M4 ;
        RECT  457.836 576.768 457.92 576.792 ;
    END
  END tap[77]
  PIN tap[78]
    DIRECTION INPUT ;
    USE SIGNAL ;
    PORT
      LAYER M4 ;
        RECT  457.836 576.96 457.92 576.984 ;
    END
  END tap[78]
  PIN tap[79]
    DIRECTION INPUT ;
    USE SIGNAL ;
    PORT
      LAYER M4 ;
        RECT  457.836 577.152 457.92 577.176 ;
    END
  END tap[79]
  PIN tap[7]
    DIRECTION INPUT ;
    USE SIGNAL ;
    PORT
      LAYER M4 ;
        RECT  457.836 562.368 457.92 562.392 ;
    END
  END tap[7]
  PIN tap[80]
    DIRECTION INPUT ;
    USE SIGNAL ;
    PORT
      LAYER M4 ;
        RECT  457.836 577.344 457.92 577.368 ;
    END
  END tap[80]
  PIN tap[81]
    DIRECTION INPUT ;
    USE SIGNAL ;
    PORT
      LAYER M4 ;
        RECT  457.836 577.536 457.92 577.56 ;
    END
  END tap[81]
  PIN tap[82]
    DIRECTION INPUT ;
    USE SIGNAL ;
    PORT
      LAYER M4 ;
        RECT  457.836 577.728 457.92 577.752 ;
    END
  END tap[82]
  PIN tap[83]
    DIRECTION INPUT ;
    USE SIGNAL ;
    PORT
      LAYER M4 ;
        RECT  457.836 577.92 457.92 577.944 ;
    END
  END tap[83]
  PIN tap[84]
    DIRECTION INPUT ;
    USE SIGNAL ;
    PORT
      LAYER M4 ;
        RECT  457.836 578.112 457.92 578.136 ;
    END
  END tap[84]
  PIN tap[85]
    DIRECTION INPUT ;
    USE SIGNAL ;
    PORT
      LAYER M4 ;
        RECT  457.836 578.304 457.92 578.328 ;
    END
  END tap[85]
  PIN tap[86]
    DIRECTION INPUT ;
    USE SIGNAL ;
    PORT
      LAYER M4 ;
        RECT  457.836 578.496 457.92 578.52 ;
    END
  END tap[86]
  PIN tap[87]
    DIRECTION INPUT ;
    USE SIGNAL ;
    PORT
      LAYER M4 ;
        RECT  457.836 578.688 457.92 578.712 ;
    END
  END tap[87]
  PIN tap[88]
    DIRECTION INPUT ;
    USE SIGNAL ;
    PORT
      LAYER M4 ;
        RECT  457.836 578.88 457.92 578.904 ;
    END
  END tap[88]
  PIN tap[89]
    DIRECTION INPUT ;
    USE SIGNAL ;
    PORT
      LAYER M4 ;
        RECT  457.836 579.072 457.92 579.096 ;
    END
  END tap[89]
  PIN tap[8]
    DIRECTION INPUT ;
    USE SIGNAL ;
    PORT
      LAYER M4 ;
        RECT  457.836 562.56 457.92 562.584 ;
    END
  END tap[8]
  PIN tap[90]
    DIRECTION INPUT ;
    USE SIGNAL ;
    PORT
      LAYER M4 ;
        RECT  457.836 579.264 457.92 579.288 ;
    END
  END tap[90]
  PIN tap[91]
    DIRECTION INPUT ;
    USE SIGNAL ;
    PORT
      LAYER M4 ;
        RECT  457.836 579.456 457.92 579.48 ;
    END
  END tap[91]
  PIN tap[92]
    DIRECTION INPUT ;
    USE SIGNAL ;
    PORT
      LAYER M4 ;
        RECT  457.836 579.648 457.92 579.672 ;
    END
  END tap[92]
  PIN tap[93]
    DIRECTION INPUT ;
    USE SIGNAL ;
    PORT
      LAYER M4 ;
        RECT  457.836 579.84 457.92 579.864 ;
    END
  END tap[93]
  PIN tap[94]
    DIRECTION INPUT ;
    USE SIGNAL ;
    PORT
      LAYER M4 ;
        RECT  457.836 580.032 457.92 580.056 ;
    END
  END tap[94]
  PIN tap[95]
    DIRECTION INPUT ;
    USE SIGNAL ;
    PORT
      LAYER M4 ;
        RECT  457.836 580.224 457.92 580.248 ;
    END
  END tap[95]
  PIN tap[96]
    DIRECTION INPUT ;
    USE SIGNAL ;
    PORT
      LAYER M4 ;
        RECT  457.836 580.416 457.92 580.44 ;
    END
  END tap[96]
  PIN tap[97]
    DIRECTION INPUT ;
    USE SIGNAL ;
    PORT
      LAYER M4 ;
        RECT  457.836 580.608 457.92 580.632 ;
    END
  END tap[97]
  PIN tap[98]
    DIRECTION INPUT ;
    USE SIGNAL ;
    PORT
      LAYER M4 ;
        RECT  457.836 580.8 457.92 580.824 ;
    END
  END tap[98]
  PIN tap[99]
    DIRECTION INPUT ;
    USE SIGNAL ;
    PORT
      LAYER M4 ;
        RECT  457.836 580.992 457.92 581.016 ;
    END
  END tap[99]
  PIN tap[9]
    DIRECTION INPUT ;
    USE SIGNAL ;
    PORT
      LAYER M4 ;
        RECT  457.836 562.752 457.92 562.776 ;
    END
  END tap[9]
  PIN tie_hi
    DIRECTION OUTPUT ;
    USE SIGNAL ;
    PORT
      LAYER M4 ;
        RECT  457.836 672 457.92 672.024 ;
    END
  END tie_hi
  PIN tie_lo
    DIRECTION OUTPUT ;
    USE SIGNAL ;
    PORT
      LAYER M4 ;
        RECT  457.836 674.016 457.92 674.04 ;
    END
  END tie_lo
  PIN tile_id[0]
    DIRECTION INPUT ;
    USE SIGNAL ;
    PORT
      LAYER M4 ;
        RECT  457.836 664.992 457.92 665.016 ;
    END
  END tile_id[0]
  PIN tile_id[10]
    DIRECTION INPUT ;
    USE SIGNAL ;
    PORT
      LAYER M4 ;
        RECT  457.836 666.912 457.92 666.936 ;
    END
  END tile_id[10]
  PIN tile_id[11]
    DIRECTION INPUT ;
    USE SIGNAL ;
    PORT
      LAYER M4 ;
        RECT  457.836 667.104 457.92 667.128 ;
    END
  END tile_id[11]
  PIN tile_id[12]
    DIRECTION INPUT ;
    USE SIGNAL ;
    PORT
      LAYER M4 ;
        RECT  457.836 667.296 457.92 667.32 ;
    END
  END tile_id[12]
  PIN tile_id[13]
    DIRECTION INPUT ;
    USE SIGNAL ;
    PORT
      LAYER M4 ;
        RECT  457.836 667.488 457.92 667.512 ;
    END
  END tile_id[13]
  PIN tile_id[14]
    DIRECTION INPUT ;
    USE SIGNAL ;
    PORT
      LAYER M4 ;
        RECT  457.836 668.64 457.92 668.664 ;
    END
  END tile_id[14]
  PIN tile_id[15]
    DIRECTION INPUT ;
    USE SIGNAL ;
    PORT
      LAYER M4 ;
        RECT  457.836 668.832 457.92 668.856 ;
    END
  END tile_id[15]
  PIN tile_id[1]
    DIRECTION INPUT ;
    USE SIGNAL ;
    PORT
      LAYER M4 ;
        RECT  457.836 665.184 457.92 665.208 ;
    END
  END tile_id[1]
  PIN tile_id[2]
    DIRECTION INPUT ;
    USE SIGNAL ;
    PORT
      LAYER M4 ;
        RECT  457.836 665.376 457.92 665.4 ;
    END
  END tile_id[2]
  PIN tile_id[3]
    DIRECTION INPUT ;
    USE SIGNAL ;
    PORT
      LAYER M4 ;
        RECT  457.836 665.568 457.92 665.592 ;
    END
  END tile_id[3]
  PIN tile_id[4]
    DIRECTION INPUT ;
    USE SIGNAL ;
    PORT
      LAYER M4 ;
        RECT  457.836 665.76 457.92 665.784 ;
    END
  END tile_id[4]
  PIN tile_id[5]
    DIRECTION INPUT ;
    USE SIGNAL ;
    PORT
      LAYER M4 ;
        RECT  457.836 665.952 457.92 665.976 ;
    END
  END tile_id[5]
  PIN tile_id[6]
    DIRECTION INPUT ;
    USE SIGNAL ;
    PORT
      LAYER M4 ;
        RECT  457.836 666.144 457.92 666.168 ;
    END
  END tile_id[6]
  PIN tile_id[7]
    DIRECTION INPUT ;
    USE SIGNAL ;
    PORT
      LAYER M4 ;
        RECT  457.836 666.336 457.92 666.36 ;
    END
  END tile_id[7]
  PIN tile_id[8]
    DIRECTION INPUT ;
    USE SIGNAL ;
    PORT
      LAYER M4 ;
        RECT  457.836 666.528 457.92 666.552 ;
    END
  END tile_id[8]
  PIN tile_id[9]
    DIRECTION INPUT ;
    USE SIGNAL ;
    PORT
      LAYER M4 ;
        RECT  457.836 666.72 457.92 666.744 ;
    END
  END tile_id[9]
  PIN VSS
    DIRECTION INOUT ;
    USE GROUND ;
    PORT
      LAYER M5 ;
        RECT  451.284 4.297 451.404 1153.463 ;
        RECT  446.964 4.297 447.084 1153.463 ;
        RECT  442.644 4.297 442.764 1153.463 ;
        RECT  438.324 650.815 438.444 1153.463 ;
        RECT  438.324 520.639 438.444 542.003 ;
        RECT  438.324 390.463 438.444 411.827 ;
        RECT  438.324 260.287 438.444 281.651 ;
        RECT  438.324 130.111 438.444 151.475 ;
        RECT  438.324 4.297 438.444 21.299 ;
        RECT  434.004 650.815 434.124 1153.463 ;
        RECT  434.004 520.639 434.124 542.003 ;
        RECT  434.004 390.463 434.124 411.827 ;
        RECT  434.004 260.287 434.124 281.651 ;
        RECT  434.004 130.111 434.124 151.475 ;
        RECT  434.004 4.297 434.124 21.299 ;
        RECT  429.684 650.815 429.804 1153.463 ;
        RECT  429.684 520.639 429.804 542.003 ;
        RECT  429.684 390.463 429.804 411.827 ;
        RECT  429.684 260.287 429.804 281.651 ;
        RECT  429.684 130.111 429.804 151.475 ;
        RECT  429.684 4.297 429.804 21.299 ;
        RECT  425.364 1137.416 425.484 1153.463 ;
        RECT  425.364 976.904 425.484 997.169 ;
        RECT  425.364 816.392 425.484 836.657 ;
        RECT  425.364 650.815 425.484 676.145 ;
        RECT  425.364 520.639 425.484 542.003 ;
        RECT  425.364 390.463 425.484 411.827 ;
        RECT  425.364 260.287 425.484 281.651 ;
        RECT  425.364 130.111 425.484 151.475 ;
        RECT  425.364 4.297 425.484 21.299 ;
        RECT  421.044 1137.416 421.164 1153.463 ;
        RECT  421.044 976.904 421.164 997.097 ;
        RECT  421.044 816.392 421.164 836.585 ;
        RECT  421.044 650.815 421.164 676.073 ;
        RECT  421.044 520.639 421.164 542.003 ;
        RECT  421.044 390.463 421.164 411.827 ;
        RECT  421.044 260.287 421.164 281.651 ;
        RECT  421.044 130.111 421.164 151.475 ;
        RECT  421.044 4.297 421.164 21.299 ;
        RECT  416.724 1137.416 416.844 1153.463 ;
        RECT  416.724 976.904 416.844 997.097 ;
        RECT  416.724 816.392 416.844 836.585 ;
        RECT  416.724 650.815 416.844 676.073 ;
        RECT  416.724 520.639 416.844 542.003 ;
        RECT  416.724 390.463 416.844 411.827 ;
        RECT  416.724 260.287 416.844 281.651 ;
        RECT  416.724 130.111 416.844 151.475 ;
        RECT  416.724 4.297 416.844 21.299 ;
        RECT  412.404 1137.416 412.524 1153.463 ;
        RECT  412.404 976.904 412.524 997.097 ;
        RECT  412.404 816.392 412.524 836.585 ;
        RECT  412.404 650.815 412.524 676.073 ;
        RECT  412.404 520.639 412.524 542.003 ;
        RECT  412.404 390.463 412.524 411.827 ;
        RECT  412.404 260.287 412.524 281.651 ;
        RECT  412.404 130.111 412.524 151.475 ;
        RECT  412.404 4.297 412.524 21.299 ;
        RECT  408.084 1137.416 408.204 1153.463 ;
        RECT  408.084 976.904 408.204 997.097 ;
        RECT  408.084 816.392 408.204 836.585 ;
        RECT  408.084 650.815 408.204 676.073 ;
        RECT  408.084 520.639 408.204 542.003 ;
        RECT  408.084 390.463 408.204 411.827 ;
        RECT  408.084 260.287 408.204 281.651 ;
        RECT  408.084 130.111 408.204 151.475 ;
        RECT  408.084 4.297 408.204 21.299 ;
        RECT  403.764 1137.416 403.884 1153.463 ;
        RECT  403.764 976.904 403.884 997.097 ;
        RECT  403.764 816.392 403.884 836.585 ;
        RECT  403.764 650.815 403.884 676.073 ;
        RECT  403.764 520.639 403.884 542.003 ;
        RECT  403.764 390.463 403.884 411.827 ;
        RECT  403.764 260.287 403.884 281.651 ;
        RECT  403.764 130.111 403.884 151.475 ;
        RECT  403.764 4.297 403.884 21.299 ;
        RECT  399.444 1137.416 399.564 1153.463 ;
        RECT  399.444 976.904 399.564 997.097 ;
        RECT  399.444 816.392 399.564 836.585 ;
        RECT  399.444 650.815 399.564 676.073 ;
        RECT  399.444 520.639 399.564 542.003 ;
        RECT  399.444 390.463 399.564 411.827 ;
        RECT  399.444 260.287 399.564 281.651 ;
        RECT  399.444 130.111 399.564 151.475 ;
        RECT  399.444 4.297 399.564 21.299 ;
        RECT  395.124 1137.416 395.244 1153.463 ;
        RECT  395.124 976.904 395.244 997.097 ;
        RECT  395.124 816.392 395.244 836.585 ;
        RECT  395.124 650.815 395.244 676.073 ;
        RECT  395.124 520.639 395.244 542.003 ;
        RECT  395.124 390.463 395.244 411.827 ;
        RECT  395.124 260.287 395.244 281.651 ;
        RECT  395.124 130.111 395.244 151.475 ;
        RECT  395.124 4.297 395.244 21.299 ;
        RECT  390.804 1137.416 390.924 1153.463 ;
        RECT  390.804 976.904 390.924 997.097 ;
        RECT  390.804 816.392 390.924 836.585 ;
        RECT  390.804 650.815 390.924 676.073 ;
        RECT  390.804 520.639 390.924 542.003 ;
        RECT  390.804 390.463 390.924 411.827 ;
        RECT  390.804 260.287 390.924 281.651 ;
        RECT  390.804 130.111 390.924 151.475 ;
        RECT  390.804 4.297 390.924 21.299 ;
        RECT  386.484 1137.416 386.604 1153.463 ;
        RECT  386.484 976.904 386.604 997.097 ;
        RECT  386.484 816.392 386.604 836.585 ;
        RECT  386.484 650.815 386.604 676.073 ;
        RECT  386.484 520.639 386.604 542.003 ;
        RECT  386.484 390.463 386.604 411.827 ;
        RECT  386.484 260.287 386.604 281.651 ;
        RECT  386.484 130.111 386.604 151.475 ;
        RECT  386.484 4.297 386.604 21.299 ;
        RECT  382.164 1137.416 382.284 1153.463 ;
        RECT  382.164 976.904 382.284 997.097 ;
        RECT  382.164 816.392 382.284 836.585 ;
        RECT  382.164 650.815 382.284 676.073 ;
        RECT  382.164 520.639 382.284 542.003 ;
        RECT  382.164 390.463 382.284 411.827 ;
        RECT  382.164 260.287 382.284 281.651 ;
        RECT  382.164 130.111 382.284 151.475 ;
        RECT  382.164 4.297 382.284 21.299 ;
        RECT  377.844 1137.416 377.964 1153.463 ;
        RECT  377.844 976.904 377.964 997.097 ;
        RECT  377.844 816.392 377.964 836.585 ;
        RECT  377.844 650.815 377.964 676.073 ;
        RECT  377.844 520.639 377.964 542.003 ;
        RECT  377.844 390.463 377.964 411.827 ;
        RECT  377.844 260.287 377.964 281.651 ;
        RECT  377.844 130.111 377.964 151.475 ;
        RECT  377.844 4.297 377.964 21.299 ;
        RECT  373.524 1137.416 373.644 1153.463 ;
        RECT  373.524 976.904 373.644 997.097 ;
        RECT  373.524 816.392 373.644 836.585 ;
        RECT  373.524 650.815 373.644 676.073 ;
        RECT  373.524 520.639 373.644 542.003 ;
        RECT  373.524 390.463 373.644 411.827 ;
        RECT  373.524 260.287 373.644 281.651 ;
        RECT  373.524 130.111 373.644 151.475 ;
        RECT  373.524 4.297 373.644 21.299 ;
        RECT  369.204 1137.416 369.324 1153.463 ;
        RECT  369.204 976.904 369.324 997.097 ;
        RECT  369.204 816.392 369.324 836.585 ;
        RECT  369.204 650.815 369.324 676.073 ;
        RECT  369.204 520.639 369.324 542.003 ;
        RECT  369.204 390.463 369.324 411.827 ;
        RECT  369.204 260.287 369.324 281.651 ;
        RECT  369.204 130.111 369.324 151.475 ;
        RECT  369.204 4.297 369.324 21.299 ;
        RECT  364.884 1137.416 365.004 1153.463 ;
        RECT  364.884 976.904 365.004 997.097 ;
        RECT  364.884 816.392 365.004 836.585 ;
        RECT  364.884 650.815 365.004 676.073 ;
        RECT  364.884 520.639 365.004 542.003 ;
        RECT  364.884 390.463 365.004 411.827 ;
        RECT  364.884 260.287 365.004 281.651 ;
        RECT  364.884 130.111 365.004 151.475 ;
        RECT  364.884 4.297 365.004 21.299 ;
        RECT  360.564 1137.416 360.684 1153.463 ;
        RECT  360.564 976.904 360.684 997.097 ;
        RECT  360.564 816.392 360.684 836.585 ;
        RECT  360.564 650.815 360.684 676.073 ;
        RECT  360.564 520.639 360.684 542.003 ;
        RECT  360.564 390.463 360.684 411.827 ;
        RECT  360.564 260.287 360.684 281.651 ;
        RECT  360.564 130.111 360.684 151.475 ;
        RECT  360.564 4.297 360.684 21.299 ;
        RECT  356.244 1137.416 356.364 1153.463 ;
        RECT  356.244 976.904 356.364 997.097 ;
        RECT  356.244 816.392 356.364 836.585 ;
        RECT  356.244 650.815 356.364 676.073 ;
        RECT  356.244 520.639 356.364 542.003 ;
        RECT  356.244 390.463 356.364 411.827 ;
        RECT  356.244 260.287 356.364 281.651 ;
        RECT  356.244 130.111 356.364 151.475 ;
        RECT  356.244 4.297 356.364 21.299 ;
        RECT  351.924 1137.416 352.044 1153.463 ;
        RECT  351.924 976.904 352.044 997.097 ;
        RECT  351.924 816.392 352.044 836.585 ;
        RECT  351.924 650.815 352.044 676.073 ;
        RECT  351.924 520.639 352.044 542.003 ;
        RECT  351.924 390.463 352.044 411.827 ;
        RECT  351.924 260.287 352.044 281.651 ;
        RECT  351.924 130.111 352.044 151.475 ;
        RECT  351.924 4.297 352.044 21.299 ;
        RECT  347.604 1137.416 347.724 1153.463 ;
        RECT  347.604 976.904 347.724 997.097 ;
        RECT  347.604 816.392 347.724 836.585 ;
        RECT  347.604 650.815 347.724 676.073 ;
        RECT  347.604 520.639 347.724 542.003 ;
        RECT  347.604 390.463 347.724 411.827 ;
        RECT  347.604 260.287 347.724 281.651 ;
        RECT  347.604 130.111 347.724 151.475 ;
        RECT  347.604 4.297 347.724 21.299 ;
        RECT  343.284 1137.416 343.404 1153.463 ;
        RECT  343.284 976.904 343.404 997.097 ;
        RECT  343.284 816.392 343.404 836.585 ;
        RECT  343.284 650.815 343.404 676.073 ;
        RECT  343.284 520.639 343.404 542.003 ;
        RECT  343.284 390.463 343.404 411.827 ;
        RECT  343.284 260.287 343.404 281.651 ;
        RECT  343.284 130.111 343.404 151.475 ;
        RECT  343.284 4.297 343.404 21.299 ;
        RECT  338.964 1137.416 339.084 1153.463 ;
        RECT  338.964 976.904 339.084 997.097 ;
        RECT  338.964 816.392 339.084 836.585 ;
        RECT  338.964 650.815 339.084 676.073 ;
        RECT  338.964 520.639 339.084 542.003 ;
        RECT  338.964 390.463 339.084 411.827 ;
        RECT  338.964 260.287 339.084 281.651 ;
        RECT  338.964 130.111 339.084 151.475 ;
        RECT  338.964 4.297 339.084 21.299 ;
        RECT  334.644 1137.416 334.764 1153.463 ;
        RECT  334.644 976.904 334.764 997.097 ;
        RECT  334.644 816.392 334.764 836.585 ;
        RECT  334.644 650.815 334.764 676.073 ;
        RECT  334.644 520.639 334.764 542.003 ;
        RECT  334.644 390.463 334.764 411.827 ;
        RECT  334.644 260.287 334.764 281.651 ;
        RECT  334.644 130.111 334.764 151.475 ;
        RECT  334.644 4.297 334.764 21.299 ;
        RECT  330.324 1137.416 330.444 1153.463 ;
        RECT  330.324 976.904 330.444 997.097 ;
        RECT  330.324 816.392 330.444 836.585 ;
        RECT  330.324 650.815 330.444 676.073 ;
        RECT  330.324 520.639 330.444 542.003 ;
        RECT  330.324 390.463 330.444 411.827 ;
        RECT  330.324 260.287 330.444 281.651 ;
        RECT  330.324 130.111 330.444 151.475 ;
        RECT  330.324 4.297 330.444 21.299 ;
        RECT  326.004 1137.416 326.124 1153.463 ;
        RECT  326.004 976.904 326.124 997.097 ;
        RECT  326.004 816.392 326.124 836.585 ;
        RECT  326.004 650.815 326.124 676.073 ;
        RECT  326.004 520.639 326.124 542.003 ;
        RECT  326.004 390.463 326.124 411.827 ;
        RECT  326.004 260.287 326.124 281.651 ;
        RECT  326.004 130.111 326.124 151.475 ;
        RECT  326.004 4.297 326.124 21.299 ;
        RECT  321.684 1137.416 321.804 1153.463 ;
        RECT  321.684 976.904 321.804 997.097 ;
        RECT  321.684 816.392 321.804 836.585 ;
        RECT  321.684 650.815 321.804 676.073 ;
        RECT  321.684 520.639 321.804 542.003 ;
        RECT  321.684 390.463 321.804 411.827 ;
        RECT  321.684 260.287 321.804 281.651 ;
        RECT  321.684 130.111 321.804 151.475 ;
        RECT  321.684 4.297 321.804 21.299 ;
        RECT  317.364 1137.416 317.484 1153.463 ;
        RECT  317.364 976.904 317.484 997.097 ;
        RECT  317.364 816.392 317.484 836.585 ;
        RECT  317.364 650.815 317.484 676.073 ;
        RECT  317.364 520.639 317.484 542.003 ;
        RECT  317.364 390.463 317.484 411.827 ;
        RECT  317.364 260.287 317.484 281.651 ;
        RECT  317.364 130.111 317.484 151.475 ;
        RECT  317.364 4.297 317.484 21.299 ;
        RECT  313.044 650.815 313.164 1153.463 ;
        RECT  313.044 520.639 313.164 542.003 ;
        RECT  313.044 390.463 313.164 411.827 ;
        RECT  313.044 260.287 313.164 281.651 ;
        RECT  313.044 130.111 313.164 151.475 ;
        RECT  313.044 4.297 313.164 21.299 ;
        RECT  308.724 650.815 308.844 1153.463 ;
        RECT  308.724 520.639 308.844 542.003 ;
        RECT  308.724 390.463 308.844 411.827 ;
        RECT  308.724 260.287 308.844 281.651 ;
        RECT  308.724 130.111 308.844 151.475 ;
        RECT  308.724 4.297 308.844 21.299 ;
        RECT  304.404 1137.416 304.524 1153.463 ;
        RECT  304.404 976.904 304.524 997.169 ;
        RECT  304.404 650.815 304.524 836.657 ;
        RECT  304.404 520.639 304.524 542.003 ;
        RECT  304.404 390.463 304.524 411.827 ;
        RECT  304.404 260.287 304.524 281.651 ;
        RECT  304.404 130.111 304.524 151.475 ;
        RECT  304.404 4.297 304.524 21.299 ;
        RECT  300.084 1137.416 300.204 1153.463 ;
        RECT  300.084 976.904 300.204 997.097 ;
        RECT  300.084 650.815 300.204 836.585 ;
        RECT  300.084 520.639 300.204 542.003 ;
        RECT  300.084 390.463 300.204 411.827 ;
        RECT  300.084 260.287 300.204 281.651 ;
        RECT  300.084 130.111 300.204 151.475 ;
        RECT  300.084 4.297 300.204 21.299 ;
        RECT  295.764 1137.416 295.884 1153.463 ;
        RECT  295.764 976.904 295.884 997.097 ;
        RECT  295.764 650.815 295.884 836.585 ;
        RECT  295.764 520.639 295.884 542.003 ;
        RECT  295.764 390.463 295.884 411.827 ;
        RECT  295.764 260.287 295.884 281.651 ;
        RECT  295.764 130.111 295.884 151.475 ;
        RECT  295.764 4.297 295.884 21.299 ;
        RECT  291.444 1137.416 291.564 1153.463 ;
        RECT  291.444 976.904 291.564 997.097 ;
        RECT  291.444 650.815 291.564 836.585 ;
        RECT  291.444 520.639 291.564 542.003 ;
        RECT  291.444 390.463 291.564 411.827 ;
        RECT  291.444 260.287 291.564 281.651 ;
        RECT  291.444 130.111 291.564 151.475 ;
        RECT  291.444 4.297 291.564 21.299 ;
        RECT  287.124 1137.416 287.244 1153.463 ;
        RECT  287.124 976.904 287.244 997.097 ;
        RECT  287.124 650.815 287.244 836.585 ;
        RECT  287.124 520.639 287.244 542.003 ;
        RECT  287.124 390.463 287.244 411.827 ;
        RECT  287.124 260.287 287.244 281.651 ;
        RECT  287.124 130.111 287.244 151.475 ;
        RECT  287.124 4.297 287.244 21.299 ;
        RECT  282.804 1137.416 282.924 1153.463 ;
        RECT  282.804 976.904 282.924 997.097 ;
        RECT  282.804 650.815 282.924 836.585 ;
        RECT  282.804 520.639 282.924 542.003 ;
        RECT  282.804 390.463 282.924 411.827 ;
        RECT  282.804 260.287 282.924 281.651 ;
        RECT  282.804 130.111 282.924 151.475 ;
        RECT  282.804 4.297 282.924 21.299 ;
        RECT  278.484 1137.416 278.604 1153.463 ;
        RECT  278.484 976.904 278.604 997.097 ;
        RECT  278.484 650.815 278.604 836.585 ;
        RECT  278.484 520.639 278.604 542.003 ;
        RECT  278.484 390.463 278.604 411.827 ;
        RECT  278.484 260.287 278.604 281.651 ;
        RECT  278.484 130.111 278.604 151.475 ;
        RECT  278.484 4.297 278.604 21.299 ;
        RECT  274.164 1137.416 274.284 1153.463 ;
        RECT  274.164 976.904 274.284 997.097 ;
        RECT  274.164 650.815 274.284 836.585 ;
        RECT  274.164 520.639 274.284 542.003 ;
        RECT  274.164 390.463 274.284 411.827 ;
        RECT  274.164 260.287 274.284 281.651 ;
        RECT  274.164 130.111 274.284 151.475 ;
        RECT  274.164 4.297 274.284 21.299 ;
        RECT  269.844 1137.416 269.964 1153.463 ;
        RECT  269.844 976.904 269.964 997.097 ;
        RECT  269.844 650.815 269.964 836.585 ;
        RECT  269.844 520.639 269.964 542.003 ;
        RECT  269.844 390.463 269.964 411.827 ;
        RECT  269.844 260.287 269.964 281.651 ;
        RECT  269.844 130.111 269.964 151.475 ;
        RECT  269.844 4.297 269.964 21.299 ;
        RECT  265.524 1137.416 265.644 1153.463 ;
        RECT  265.524 976.904 265.644 997.097 ;
        RECT  265.524 4.297 265.644 836.585 ;
        RECT  261.204 1137.416 261.324 1153.463 ;
        RECT  261.204 976.904 261.324 997.097 ;
        RECT  261.204 4.297 261.324 836.585 ;
        RECT  256.884 1137.416 257.004 1153.463 ;
        RECT  256.884 976.904 257.004 997.097 ;
        RECT  256.884 4.297 257.004 836.585 ;
        RECT  252.564 1137.416 252.684 1153.463 ;
        RECT  252.564 976.904 252.684 997.097 ;
        RECT  252.564 4.297 252.684 836.585 ;
        RECT  248.244 1137.416 248.364 1153.463 ;
        RECT  248.244 976.904 248.364 997.097 ;
        RECT  248.244 4.297 248.364 836.585 ;
        RECT  243.924 1137.416 244.044 1153.463 ;
        RECT  243.924 976.904 244.044 997.097 ;
        RECT  243.924 4.297 244.044 836.585 ;
        RECT  239.604 1137.416 239.724 1153.463 ;
        RECT  239.604 976.904 239.724 997.097 ;
        RECT  239.604 4.297 239.724 836.585 ;
        RECT  235.284 1137.416 235.404 1153.463 ;
        RECT  235.284 976.904 235.404 997.097 ;
        RECT  235.284 4.297 235.404 836.585 ;
        RECT  230.964 1137.416 231.084 1153.463 ;
        RECT  230.964 976.904 231.084 997.097 ;
        RECT  230.964 4.297 231.084 836.585 ;
        RECT  226.644 1137.416 226.764 1153.463 ;
        RECT  226.644 976.904 226.764 997.097 ;
        RECT  226.644 4.297 226.764 836.585 ;
        RECT  222.324 1137.416 222.444 1153.463 ;
        RECT  222.324 976.904 222.444 997.097 ;
        RECT  222.324 4.297 222.444 836.585 ;
        RECT  218.004 1137.416 218.124 1153.463 ;
        RECT  218.004 976.904 218.124 997.097 ;
        RECT  218.004 4.297 218.124 836.585 ;
        RECT  213.684 1137.416 213.804 1153.463 ;
        RECT  213.684 976.904 213.804 997.097 ;
        RECT  213.684 4.297 213.804 836.585 ;
        RECT  209.364 1137.416 209.484 1153.463 ;
        RECT  209.364 976.904 209.484 997.097 ;
        RECT  209.364 4.297 209.484 836.585 ;
        RECT  205.044 1137.416 205.164 1153.463 ;
        RECT  205.044 976.904 205.164 997.097 ;
        RECT  205.044 4.297 205.164 836.585 ;
        RECT  200.724 1137.416 200.844 1153.463 ;
        RECT  200.724 976.904 200.844 997.097 ;
        RECT  200.724 4.297 200.844 836.585 ;
        RECT  196.404 1137.416 196.524 1153.463 ;
        RECT  196.404 976.904 196.524 997.097 ;
        RECT  196.404 650.815 196.524 836.585 ;
        RECT  196.404 520.639 196.524 542.003 ;
        RECT  196.404 390.463 196.524 411.827 ;
        RECT  196.404 260.287 196.524 281.651 ;
        RECT  196.404 130.111 196.524 151.475 ;
        RECT  196.404 4.297 196.524 21.299 ;
        RECT  192.084 1137.416 192.204 1153.463 ;
        RECT  192.084 976.904 192.204 997.169 ;
        RECT  192.084 650.815 192.204 836.657 ;
        RECT  192.084 520.639 192.204 542.003 ;
        RECT  192.084 390.463 192.204 411.827 ;
        RECT  192.084 260.287 192.204 281.651 ;
        RECT  192.084 130.111 192.204 151.475 ;
        RECT  192.084 4.297 192.204 21.299 ;
        RECT  187.764 650.815 187.884 1153.463 ;
        RECT  187.764 520.639 187.884 542.003 ;
        RECT  187.764 390.463 187.884 411.827 ;
        RECT  187.764 260.287 187.884 281.651 ;
        RECT  187.764 130.111 187.884 151.475 ;
        RECT  187.764 4.297 187.884 21.299 ;
        RECT  183.444 650.815 183.564 1153.463 ;
        RECT  183.444 520.639 183.564 542.003 ;
        RECT  183.444 390.463 183.564 411.827 ;
        RECT  183.444 260.287 183.564 281.651 ;
        RECT  183.444 130.111 183.564 151.475 ;
        RECT  183.444 4.297 183.564 21.299 ;
        RECT  179.124 650.815 179.244 1153.463 ;
        RECT  179.124 520.639 179.244 542.003 ;
        RECT  179.124 390.463 179.244 411.827 ;
        RECT  179.124 260.287 179.244 281.651 ;
        RECT  179.124 130.111 179.244 151.475 ;
        RECT  179.124 4.297 179.244 21.299 ;
        RECT  174.804 650.815 174.924 1153.463 ;
        RECT  174.804 520.639 174.924 542.003 ;
        RECT  174.804 390.463 174.924 411.827 ;
        RECT  174.804 260.287 174.924 281.651 ;
        RECT  174.804 130.111 174.924 151.475 ;
        RECT  174.804 4.297 174.924 21.299 ;
        RECT  170.484 650.815 170.604 1153.463 ;
        RECT  170.484 520.639 170.604 542.003 ;
        RECT  170.484 390.463 170.604 411.827 ;
        RECT  170.484 260.287 170.604 281.651 ;
        RECT  170.484 130.111 170.604 151.475 ;
        RECT  170.484 4.297 170.604 21.299 ;
        RECT  166.164 650.815 166.284 1153.463 ;
        RECT  166.164 520.639 166.284 542.003 ;
        RECT  166.164 390.463 166.284 411.827 ;
        RECT  166.164 260.287 166.284 281.651 ;
        RECT  166.164 130.111 166.284 151.475 ;
        RECT  166.164 4.297 166.284 21.299 ;
        RECT  161.844 650.815 161.964 1153.463 ;
        RECT  161.844 520.639 161.964 542.003 ;
        RECT  161.844 390.463 161.964 411.827 ;
        RECT  161.844 260.287 161.964 281.651 ;
        RECT  161.844 130.111 161.964 151.475 ;
        RECT  161.844 4.297 161.964 21.299 ;
        RECT  157.524 650.815 157.644 1153.463 ;
        RECT  157.524 520.639 157.644 542.003 ;
        RECT  157.524 390.463 157.644 411.827 ;
        RECT  157.524 260.287 157.644 281.651 ;
        RECT  157.524 130.111 157.644 151.475 ;
        RECT  157.524 4.297 157.644 21.299 ;
        RECT  153.204 650.815 153.324 1153.463 ;
        RECT  153.204 520.639 153.324 542.003 ;
        RECT  153.204 390.463 153.324 411.827 ;
        RECT  153.204 260.287 153.324 281.651 ;
        RECT  153.204 130.111 153.324 151.475 ;
        RECT  153.204 4.297 153.324 21.299 ;
        RECT  148.884 650.815 149.004 1153.463 ;
        RECT  148.884 520.639 149.004 542.003 ;
        RECT  148.884 390.463 149.004 411.827 ;
        RECT  148.884 260.287 149.004 281.651 ;
        RECT  148.884 130.111 149.004 151.475 ;
        RECT  148.884 4.297 149.004 21.299 ;
        RECT  144.564 650.815 144.684 1153.463 ;
        RECT  144.564 520.639 144.684 542.003 ;
        RECT  144.564 390.463 144.684 411.827 ;
        RECT  144.564 260.287 144.684 281.651 ;
        RECT  144.564 130.111 144.684 151.475 ;
        RECT  144.564 4.297 144.684 21.299 ;
        RECT  140.244 650.815 140.364 1153.463 ;
        RECT  140.244 520.639 140.364 542.003 ;
        RECT  140.244 390.463 140.364 411.827 ;
        RECT  140.244 260.287 140.364 281.651 ;
        RECT  140.244 130.111 140.364 151.475 ;
        RECT  140.244 4.297 140.364 21.299 ;
        RECT  135.924 1137.416 136.044 1153.463 ;
        RECT  135.924 976.904 136.044 997.169 ;
        RECT  135.924 816.392 136.044 836.657 ;
        RECT  135.924 650.815 136.044 676.145 ;
        RECT  135.924 520.639 136.044 542.003 ;
        RECT  135.924 390.463 136.044 411.827 ;
        RECT  135.924 260.287 136.044 281.651 ;
        RECT  135.924 130.111 136.044 151.475 ;
        RECT  135.924 4.297 136.044 21.299 ;
        RECT  131.604 1137.416 131.724 1153.463 ;
        RECT  131.604 976.904 131.724 997.097 ;
        RECT  131.604 816.392 131.724 836.585 ;
        RECT  131.604 650.815 131.724 676.073 ;
        RECT  131.604 520.639 131.724 542.003 ;
        RECT  131.604 390.463 131.724 411.827 ;
        RECT  131.604 260.287 131.724 281.651 ;
        RECT  131.604 130.111 131.724 151.475 ;
        RECT  131.604 4.297 131.724 21.299 ;
        RECT  127.284 1137.416 127.404 1153.463 ;
        RECT  127.284 976.904 127.404 997.097 ;
        RECT  127.284 816.392 127.404 836.585 ;
        RECT  127.284 650.815 127.404 676.073 ;
        RECT  127.284 520.639 127.404 542.003 ;
        RECT  127.284 390.463 127.404 411.827 ;
        RECT  127.284 260.287 127.404 281.651 ;
        RECT  127.284 130.111 127.404 151.475 ;
        RECT  127.284 4.297 127.404 21.299 ;
        RECT  122.964 1137.416 123.084 1153.463 ;
        RECT  122.964 976.904 123.084 997.097 ;
        RECT  122.964 816.392 123.084 836.585 ;
        RECT  122.964 650.815 123.084 676.073 ;
        RECT  122.964 520.639 123.084 542.003 ;
        RECT  122.964 390.463 123.084 411.827 ;
        RECT  122.964 260.287 123.084 281.651 ;
        RECT  122.964 130.111 123.084 151.475 ;
        RECT  122.964 4.297 123.084 21.299 ;
        RECT  118.644 1137.416 118.764 1153.463 ;
        RECT  118.644 976.904 118.764 997.097 ;
        RECT  118.644 816.392 118.764 836.585 ;
        RECT  118.644 650.815 118.764 676.073 ;
        RECT  118.644 520.639 118.764 542.003 ;
        RECT  118.644 390.463 118.764 411.827 ;
        RECT  118.644 260.287 118.764 281.651 ;
        RECT  118.644 130.111 118.764 151.475 ;
        RECT  118.644 4.297 118.764 21.299 ;
        RECT  114.324 1137.416 114.444 1153.463 ;
        RECT  114.324 976.904 114.444 997.097 ;
        RECT  114.324 816.392 114.444 836.585 ;
        RECT  114.324 650.815 114.444 676.073 ;
        RECT  114.324 520.639 114.444 542.003 ;
        RECT  114.324 390.463 114.444 411.827 ;
        RECT  114.324 260.287 114.444 281.651 ;
        RECT  114.324 130.111 114.444 151.475 ;
        RECT  114.324 4.297 114.444 21.299 ;
        RECT  110.004 1137.416 110.124 1153.463 ;
        RECT  110.004 976.904 110.124 997.097 ;
        RECT  110.004 816.392 110.124 836.585 ;
        RECT  110.004 650.815 110.124 676.073 ;
        RECT  110.004 520.639 110.124 542.003 ;
        RECT  110.004 390.463 110.124 411.827 ;
        RECT  110.004 260.287 110.124 281.651 ;
        RECT  110.004 130.111 110.124 151.475 ;
        RECT  110.004 4.297 110.124 21.299 ;
        RECT  105.684 1137.416 105.804 1153.463 ;
        RECT  105.684 976.904 105.804 997.097 ;
        RECT  105.684 816.392 105.804 836.585 ;
        RECT  105.684 650.815 105.804 676.073 ;
        RECT  105.684 520.639 105.804 542.003 ;
        RECT  105.684 390.463 105.804 411.827 ;
        RECT  105.684 260.287 105.804 281.651 ;
        RECT  105.684 130.111 105.804 151.475 ;
        RECT  105.684 4.297 105.804 21.299 ;
        RECT  101.364 1137.416 101.484 1153.463 ;
        RECT  101.364 976.904 101.484 997.097 ;
        RECT  101.364 816.392 101.484 836.585 ;
        RECT  101.364 650.815 101.484 676.073 ;
        RECT  101.364 520.639 101.484 542.003 ;
        RECT  101.364 390.463 101.484 411.827 ;
        RECT  101.364 260.287 101.484 281.651 ;
        RECT  101.364 130.111 101.484 151.475 ;
        RECT  101.364 4.297 101.484 21.299 ;
        RECT  97.044 1137.416 97.164 1153.463 ;
        RECT  97.044 976.904 97.164 997.097 ;
        RECT  97.044 816.392 97.164 836.585 ;
        RECT  97.044 650.815 97.164 676.073 ;
        RECT  97.044 520.639 97.164 542.003 ;
        RECT  97.044 390.463 97.164 411.827 ;
        RECT  97.044 260.287 97.164 281.651 ;
        RECT  97.044 130.111 97.164 151.475 ;
        RECT  97.044 4.297 97.164 21.299 ;
        RECT  92.724 1137.416 92.844 1153.463 ;
        RECT  92.724 976.904 92.844 997.097 ;
        RECT  92.724 816.392 92.844 836.585 ;
        RECT  92.724 650.815 92.844 676.073 ;
        RECT  92.724 520.639 92.844 542.003 ;
        RECT  92.724 390.463 92.844 411.827 ;
        RECT  92.724 260.287 92.844 281.651 ;
        RECT  92.724 130.111 92.844 151.475 ;
        RECT  92.724 4.297 92.844 21.299 ;
        RECT  88.404 1137.416 88.524 1153.463 ;
        RECT  88.404 976.904 88.524 997.097 ;
        RECT  88.404 816.392 88.524 836.585 ;
        RECT  88.404 650.815 88.524 676.073 ;
        RECT  88.404 520.639 88.524 542.003 ;
        RECT  88.404 390.463 88.524 411.827 ;
        RECT  88.404 260.287 88.524 281.651 ;
        RECT  88.404 130.111 88.524 151.475 ;
        RECT  88.404 4.297 88.524 21.299 ;
        RECT  84.084 1137.416 84.204 1153.463 ;
        RECT  84.084 976.904 84.204 997.097 ;
        RECT  84.084 816.392 84.204 836.585 ;
        RECT  84.084 650.815 84.204 676.073 ;
        RECT  84.084 520.639 84.204 542.003 ;
        RECT  84.084 390.463 84.204 411.827 ;
        RECT  84.084 260.287 84.204 281.651 ;
        RECT  84.084 130.111 84.204 151.475 ;
        RECT  84.084 4.297 84.204 21.299 ;
        RECT  79.764 1137.416 79.884 1153.463 ;
        RECT  79.764 976.904 79.884 997.097 ;
        RECT  79.764 816.392 79.884 836.585 ;
        RECT  79.764 650.815 79.884 676.073 ;
        RECT  79.764 520.639 79.884 542.003 ;
        RECT  79.764 390.463 79.884 411.827 ;
        RECT  79.764 260.287 79.884 281.651 ;
        RECT  79.764 130.111 79.884 151.475 ;
        RECT  79.764 4.297 79.884 21.299 ;
        RECT  75.444 1137.416 75.564 1153.463 ;
        RECT  75.444 976.904 75.564 997.097 ;
        RECT  75.444 816.392 75.564 836.585 ;
        RECT  75.444 650.815 75.564 676.073 ;
        RECT  75.444 520.639 75.564 542.003 ;
        RECT  75.444 390.463 75.564 411.827 ;
        RECT  75.444 260.287 75.564 281.651 ;
        RECT  75.444 130.111 75.564 151.475 ;
        RECT  75.444 4.297 75.564 21.299 ;
        RECT  71.124 1137.416 71.244 1153.463 ;
        RECT  71.124 976.904 71.244 997.097 ;
        RECT  71.124 816.392 71.244 836.585 ;
        RECT  71.124 650.815 71.244 676.073 ;
        RECT  71.124 520.639 71.244 542.003 ;
        RECT  71.124 390.463 71.244 411.827 ;
        RECT  71.124 260.287 71.244 281.651 ;
        RECT  71.124 130.111 71.244 151.475 ;
        RECT  71.124 4.297 71.244 21.299 ;
        RECT  66.804 1137.416 66.924 1153.463 ;
        RECT  66.804 976.904 66.924 997.097 ;
        RECT  66.804 816.392 66.924 836.585 ;
        RECT  66.804 650.815 66.924 676.073 ;
        RECT  66.804 520.639 66.924 542.003 ;
        RECT  66.804 390.463 66.924 411.827 ;
        RECT  66.804 260.287 66.924 281.651 ;
        RECT  66.804 130.111 66.924 151.475 ;
        RECT  66.804 4.297 66.924 21.299 ;
        RECT  62.484 1137.416 62.604 1153.463 ;
        RECT  62.484 976.904 62.604 997.097 ;
        RECT  62.484 816.392 62.604 836.585 ;
        RECT  62.484 650.815 62.604 676.073 ;
        RECT  62.484 520.639 62.604 542.003 ;
        RECT  62.484 390.463 62.604 411.827 ;
        RECT  62.484 260.287 62.604 281.651 ;
        RECT  62.484 130.111 62.604 151.475 ;
        RECT  62.484 4.297 62.604 21.299 ;
        RECT  58.164 1137.416 58.284 1153.463 ;
        RECT  58.164 976.904 58.284 997.097 ;
        RECT  58.164 816.392 58.284 836.585 ;
        RECT  58.164 650.815 58.284 676.073 ;
        RECT  58.164 520.639 58.284 542.003 ;
        RECT  58.164 390.463 58.284 411.827 ;
        RECT  58.164 260.287 58.284 281.651 ;
        RECT  58.164 130.111 58.284 151.475 ;
        RECT  58.164 4.297 58.284 21.299 ;
        RECT  53.844 1137.416 53.964 1153.463 ;
        RECT  53.844 976.904 53.964 997.097 ;
        RECT  53.844 816.392 53.964 836.585 ;
        RECT  53.844 650.815 53.964 676.073 ;
        RECT  53.844 520.639 53.964 542.003 ;
        RECT  53.844 390.463 53.964 411.827 ;
        RECT  53.844 260.287 53.964 281.651 ;
        RECT  53.844 130.111 53.964 151.475 ;
        RECT  53.844 4.297 53.964 21.299 ;
        RECT  49.524 1137.416 49.644 1153.463 ;
        RECT  49.524 976.904 49.644 997.097 ;
        RECT  49.524 816.392 49.644 836.585 ;
        RECT  49.524 650.815 49.644 676.073 ;
        RECT  49.524 520.639 49.644 542.003 ;
        RECT  49.524 390.463 49.644 411.827 ;
        RECT  49.524 260.287 49.644 281.651 ;
        RECT  49.524 130.111 49.644 151.475 ;
        RECT  49.524 4.297 49.644 21.299 ;
        RECT  45.204 1137.416 45.324 1153.463 ;
        RECT  45.204 976.904 45.324 997.097 ;
        RECT  45.204 816.392 45.324 836.585 ;
        RECT  45.204 650.815 45.324 676.073 ;
        RECT  45.204 520.639 45.324 542.003 ;
        RECT  45.204 390.463 45.324 411.827 ;
        RECT  45.204 260.287 45.324 281.651 ;
        RECT  45.204 130.111 45.324 151.475 ;
        RECT  45.204 4.297 45.324 21.299 ;
        RECT  40.884 1137.416 41.004 1153.463 ;
        RECT  40.884 976.904 41.004 997.097 ;
        RECT  40.884 816.392 41.004 836.585 ;
        RECT  40.884 650.815 41.004 676.073 ;
        RECT  40.884 520.639 41.004 542.003 ;
        RECT  40.884 390.463 41.004 411.827 ;
        RECT  40.884 260.287 41.004 281.651 ;
        RECT  40.884 130.111 41.004 151.475 ;
        RECT  40.884 4.297 41.004 21.299 ;
        RECT  36.564 1137.416 36.684 1153.463 ;
        RECT  36.564 976.904 36.684 997.097 ;
        RECT  36.564 816.392 36.684 836.585 ;
        RECT  36.564 650.815 36.684 676.073 ;
        RECT  36.564 520.639 36.684 542.003 ;
        RECT  36.564 390.463 36.684 411.827 ;
        RECT  36.564 260.287 36.684 281.651 ;
        RECT  36.564 130.111 36.684 151.475 ;
        RECT  36.564 4.297 36.684 21.299 ;
        RECT  32.244 1137.416 32.364 1153.463 ;
        RECT  32.244 976.904 32.364 997.097 ;
        RECT  32.244 816.392 32.364 836.585 ;
        RECT  32.244 650.815 32.364 676.073 ;
        RECT  32.244 520.639 32.364 542.003 ;
        RECT  32.244 390.463 32.364 411.827 ;
        RECT  32.244 260.287 32.364 281.651 ;
        RECT  32.244 130.111 32.364 151.475 ;
        RECT  32.244 4.297 32.364 21.299 ;
        RECT  27.924 1137.416 28.044 1153.463 ;
        RECT  27.924 976.904 28.044 997.097 ;
        RECT  27.924 816.392 28.044 836.585 ;
        RECT  27.924 650.815 28.044 676.073 ;
        RECT  27.924 520.639 28.044 542.003 ;
        RECT  27.924 390.463 28.044 411.827 ;
        RECT  27.924 260.287 28.044 281.651 ;
        RECT  27.924 130.111 28.044 151.475 ;
        RECT  27.924 4.297 28.044 21.299 ;
        RECT  23.604 4.297 23.724 1153.463 ;
        RECT  19.284 4.297 19.404 1153.463 ;
        RECT  14.964 4.297 15.084 1153.463 ;
        RECT  10.644 4.297 10.764 1153.463 ;
        RECT  6.324 4.297 6.444 1153.463 ;
    END
  END VSS
  PIN VDD
    DIRECTION INOUT ;
    USE POWER ;
    PORT
      LAYER M5 ;
        RECT  451.476 4.311 451.596 1153.449 ;
        RECT  447.156 4.311 447.276 1153.449 ;
        RECT  442.836 4.311 442.956 1153.449 ;
        RECT  438.516 650.815 438.636 1153.449 ;
        RECT  438.516 520.639 438.636 542.003 ;
        RECT  438.516 390.463 438.636 411.827 ;
        RECT  438.516 260.287 438.636 281.651 ;
        RECT  438.516 130.111 438.636 151.475 ;
        RECT  438.516 4.311 438.636 21.299 ;
        RECT  434.196 650.815 434.316 1153.449 ;
        RECT  434.196 520.639 434.316 542.003 ;
        RECT  434.196 390.463 434.316 411.827 ;
        RECT  434.196 260.287 434.316 281.651 ;
        RECT  434.196 130.111 434.316 151.475 ;
        RECT  434.196 4.311 434.316 21.299 ;
        RECT  429.876 650.815 429.996 1153.449 ;
        RECT  429.876 520.639 429.996 542.003 ;
        RECT  429.876 390.463 429.996 411.827 ;
        RECT  429.876 260.287 429.996 281.651 ;
        RECT  429.876 130.111 429.996 151.475 ;
        RECT  429.876 4.311 429.996 21.299 ;
        RECT  425.556 1137.416 425.676 1153.449 ;
        RECT  425.556 976.904 425.676 997.169 ;
        RECT  425.556 816.392 425.676 836.657 ;
        RECT  425.556 650.815 425.676 676.145 ;
        RECT  425.556 520.639 425.676 542.003 ;
        RECT  425.556 390.463 425.676 411.827 ;
        RECT  425.556 260.287 425.676 281.651 ;
        RECT  425.556 130.111 425.676 151.475 ;
        RECT  425.556 4.311 425.676 21.299 ;
        RECT  421.236 1137.416 421.356 1153.449 ;
        RECT  421.236 976.904 421.356 997.097 ;
        RECT  421.236 816.392 421.356 836.585 ;
        RECT  421.236 650.815 421.356 676.073 ;
        RECT  421.236 520.639 421.356 542.003 ;
        RECT  421.236 390.463 421.356 411.827 ;
        RECT  421.236 260.287 421.356 281.651 ;
        RECT  421.236 130.111 421.356 151.475 ;
        RECT  421.236 4.311 421.356 21.299 ;
        RECT  416.916 1137.416 417.036 1153.449 ;
        RECT  416.916 976.904 417.036 997.097 ;
        RECT  416.916 816.392 417.036 836.585 ;
        RECT  416.916 650.815 417.036 676.073 ;
        RECT  416.916 520.639 417.036 542.003 ;
        RECT  416.916 390.463 417.036 411.827 ;
        RECT  416.916 260.287 417.036 281.651 ;
        RECT  416.916 130.111 417.036 151.475 ;
        RECT  416.916 4.311 417.036 21.299 ;
        RECT  412.596 1137.416 412.716 1153.449 ;
        RECT  412.596 976.904 412.716 997.097 ;
        RECT  412.596 816.392 412.716 836.585 ;
        RECT  412.596 650.815 412.716 676.073 ;
        RECT  412.596 520.639 412.716 542.003 ;
        RECT  412.596 390.463 412.716 411.827 ;
        RECT  412.596 260.287 412.716 281.651 ;
        RECT  412.596 130.111 412.716 151.475 ;
        RECT  412.596 4.311 412.716 21.299 ;
        RECT  408.276 1137.416 408.396 1153.449 ;
        RECT  408.276 976.904 408.396 997.097 ;
        RECT  408.276 816.392 408.396 836.585 ;
        RECT  408.276 650.815 408.396 676.073 ;
        RECT  408.276 520.639 408.396 542.003 ;
        RECT  408.276 390.463 408.396 411.827 ;
        RECT  408.276 260.287 408.396 281.651 ;
        RECT  408.276 130.111 408.396 151.475 ;
        RECT  408.276 4.311 408.396 21.299 ;
        RECT  403.956 1137.416 404.076 1153.449 ;
        RECT  403.956 976.904 404.076 997.097 ;
        RECT  403.956 816.392 404.076 836.585 ;
        RECT  403.956 650.815 404.076 676.073 ;
        RECT  403.956 520.639 404.076 542.003 ;
        RECT  403.956 390.463 404.076 411.827 ;
        RECT  403.956 260.287 404.076 281.651 ;
        RECT  403.956 130.111 404.076 151.475 ;
        RECT  403.956 4.311 404.076 21.299 ;
        RECT  399.636 1137.416 399.756 1153.449 ;
        RECT  399.636 976.904 399.756 997.097 ;
        RECT  399.636 816.392 399.756 836.585 ;
        RECT  399.636 650.815 399.756 676.073 ;
        RECT  399.636 520.639 399.756 542.003 ;
        RECT  399.636 390.463 399.756 411.827 ;
        RECT  399.636 260.287 399.756 281.651 ;
        RECT  399.636 130.111 399.756 151.475 ;
        RECT  399.636 4.311 399.756 21.299 ;
        RECT  395.316 1137.416 395.436 1153.449 ;
        RECT  395.316 976.904 395.436 997.097 ;
        RECT  395.316 816.392 395.436 836.585 ;
        RECT  395.316 650.815 395.436 676.073 ;
        RECT  395.316 520.639 395.436 542.003 ;
        RECT  395.316 390.463 395.436 411.827 ;
        RECT  395.316 260.287 395.436 281.651 ;
        RECT  395.316 130.111 395.436 151.475 ;
        RECT  395.316 4.311 395.436 21.299 ;
        RECT  390.996 1137.416 391.116 1153.449 ;
        RECT  390.996 976.904 391.116 997.097 ;
        RECT  390.996 816.392 391.116 836.585 ;
        RECT  390.996 650.815 391.116 676.073 ;
        RECT  390.996 520.639 391.116 542.003 ;
        RECT  390.996 390.463 391.116 411.827 ;
        RECT  390.996 260.287 391.116 281.651 ;
        RECT  390.996 130.111 391.116 151.475 ;
        RECT  390.996 4.311 391.116 21.299 ;
        RECT  386.676 1137.416 386.796 1153.449 ;
        RECT  386.676 976.904 386.796 997.097 ;
        RECT  386.676 816.392 386.796 836.585 ;
        RECT  386.676 650.815 386.796 676.073 ;
        RECT  386.676 520.639 386.796 542.003 ;
        RECT  386.676 390.463 386.796 411.827 ;
        RECT  386.676 260.287 386.796 281.651 ;
        RECT  386.676 130.111 386.796 151.475 ;
        RECT  386.676 4.311 386.796 21.299 ;
        RECT  382.356 1137.416 382.476 1153.449 ;
        RECT  382.356 976.904 382.476 997.097 ;
        RECT  382.356 816.392 382.476 836.585 ;
        RECT  382.356 650.815 382.476 676.073 ;
        RECT  382.356 520.639 382.476 542.003 ;
        RECT  382.356 390.463 382.476 411.827 ;
        RECT  382.356 260.287 382.476 281.651 ;
        RECT  382.356 130.111 382.476 151.475 ;
        RECT  382.356 4.311 382.476 21.299 ;
        RECT  378.036 1137.416 378.156 1153.449 ;
        RECT  378.036 976.904 378.156 997.097 ;
        RECT  378.036 816.392 378.156 836.585 ;
        RECT  378.036 650.815 378.156 676.073 ;
        RECT  378.036 520.639 378.156 542.003 ;
        RECT  378.036 390.463 378.156 411.827 ;
        RECT  378.036 260.287 378.156 281.651 ;
        RECT  378.036 130.111 378.156 151.475 ;
        RECT  378.036 4.311 378.156 21.299 ;
        RECT  373.716 1137.416 373.836 1153.449 ;
        RECT  373.716 976.904 373.836 997.097 ;
        RECT  373.716 816.392 373.836 836.585 ;
        RECT  373.716 650.815 373.836 676.073 ;
        RECT  373.716 520.639 373.836 542.003 ;
        RECT  373.716 390.463 373.836 411.827 ;
        RECT  373.716 260.287 373.836 281.651 ;
        RECT  373.716 130.111 373.836 151.475 ;
        RECT  373.716 4.311 373.836 21.299 ;
        RECT  369.396 1137.416 369.516 1153.449 ;
        RECT  369.396 976.904 369.516 997.097 ;
        RECT  369.396 816.392 369.516 836.585 ;
        RECT  369.396 650.815 369.516 676.073 ;
        RECT  369.396 520.639 369.516 542.003 ;
        RECT  369.396 390.463 369.516 411.827 ;
        RECT  369.396 260.287 369.516 281.651 ;
        RECT  369.396 130.111 369.516 151.475 ;
        RECT  369.396 4.311 369.516 21.299 ;
        RECT  365.076 1137.416 365.196 1153.449 ;
        RECT  365.076 976.904 365.196 997.097 ;
        RECT  365.076 816.392 365.196 836.585 ;
        RECT  365.076 650.815 365.196 676.073 ;
        RECT  365.076 520.639 365.196 542.003 ;
        RECT  365.076 390.463 365.196 411.827 ;
        RECT  365.076 260.287 365.196 281.651 ;
        RECT  365.076 130.111 365.196 151.475 ;
        RECT  365.076 4.311 365.196 21.299 ;
        RECT  360.756 1137.416 360.876 1153.449 ;
        RECT  360.756 976.904 360.876 997.097 ;
        RECT  360.756 816.392 360.876 836.585 ;
        RECT  360.756 650.815 360.876 676.073 ;
        RECT  360.756 520.639 360.876 542.003 ;
        RECT  360.756 390.463 360.876 411.827 ;
        RECT  360.756 260.287 360.876 281.651 ;
        RECT  360.756 130.111 360.876 151.475 ;
        RECT  360.756 4.311 360.876 21.299 ;
        RECT  356.436 1137.416 356.556 1153.449 ;
        RECT  356.436 976.904 356.556 997.097 ;
        RECT  356.436 816.392 356.556 836.585 ;
        RECT  356.436 650.815 356.556 676.073 ;
        RECT  356.436 520.639 356.556 542.003 ;
        RECT  356.436 390.463 356.556 411.827 ;
        RECT  356.436 260.287 356.556 281.651 ;
        RECT  356.436 130.111 356.556 151.475 ;
        RECT  356.436 4.311 356.556 21.299 ;
        RECT  352.116 1137.416 352.236 1153.449 ;
        RECT  352.116 976.904 352.236 997.097 ;
        RECT  352.116 816.392 352.236 836.585 ;
        RECT  352.116 650.815 352.236 676.073 ;
        RECT  352.116 520.639 352.236 542.003 ;
        RECT  352.116 390.463 352.236 411.827 ;
        RECT  352.116 260.287 352.236 281.651 ;
        RECT  352.116 130.111 352.236 151.475 ;
        RECT  352.116 4.311 352.236 21.299 ;
        RECT  347.796 1137.416 347.916 1153.449 ;
        RECT  347.796 976.904 347.916 997.097 ;
        RECT  347.796 816.392 347.916 836.585 ;
        RECT  347.796 650.815 347.916 676.073 ;
        RECT  347.796 520.639 347.916 542.003 ;
        RECT  347.796 390.463 347.916 411.827 ;
        RECT  347.796 260.287 347.916 281.651 ;
        RECT  347.796 130.111 347.916 151.475 ;
        RECT  347.796 4.311 347.916 21.299 ;
        RECT  343.476 1137.416 343.596 1153.449 ;
        RECT  343.476 976.904 343.596 997.097 ;
        RECT  343.476 816.392 343.596 836.585 ;
        RECT  343.476 650.815 343.596 676.073 ;
        RECT  343.476 520.639 343.596 542.003 ;
        RECT  343.476 390.463 343.596 411.827 ;
        RECT  343.476 260.287 343.596 281.651 ;
        RECT  343.476 130.111 343.596 151.475 ;
        RECT  343.476 4.311 343.596 21.299 ;
        RECT  339.156 1137.416 339.276 1153.449 ;
        RECT  339.156 976.904 339.276 997.097 ;
        RECT  339.156 816.392 339.276 836.585 ;
        RECT  339.156 650.815 339.276 676.073 ;
        RECT  339.156 520.639 339.276 542.003 ;
        RECT  339.156 390.463 339.276 411.827 ;
        RECT  339.156 260.287 339.276 281.651 ;
        RECT  339.156 130.111 339.276 151.475 ;
        RECT  339.156 4.311 339.276 21.299 ;
        RECT  334.836 1137.416 334.956 1153.449 ;
        RECT  334.836 976.904 334.956 997.097 ;
        RECT  334.836 816.392 334.956 836.585 ;
        RECT  334.836 650.815 334.956 676.073 ;
        RECT  334.836 520.639 334.956 542.003 ;
        RECT  334.836 390.463 334.956 411.827 ;
        RECT  334.836 260.287 334.956 281.651 ;
        RECT  334.836 130.111 334.956 151.475 ;
        RECT  334.836 4.311 334.956 21.299 ;
        RECT  330.516 1137.416 330.636 1153.449 ;
        RECT  330.516 976.904 330.636 997.097 ;
        RECT  330.516 816.392 330.636 836.585 ;
        RECT  330.516 650.815 330.636 676.073 ;
        RECT  330.516 520.639 330.636 542.003 ;
        RECT  330.516 390.463 330.636 411.827 ;
        RECT  330.516 260.287 330.636 281.651 ;
        RECT  330.516 130.111 330.636 151.475 ;
        RECT  330.516 4.311 330.636 21.299 ;
        RECT  326.196 1137.416 326.316 1153.449 ;
        RECT  326.196 976.904 326.316 997.097 ;
        RECT  326.196 816.392 326.316 836.585 ;
        RECT  326.196 650.815 326.316 676.073 ;
        RECT  326.196 520.639 326.316 542.003 ;
        RECT  326.196 390.463 326.316 411.827 ;
        RECT  326.196 260.287 326.316 281.651 ;
        RECT  326.196 130.111 326.316 151.475 ;
        RECT  326.196 4.311 326.316 21.299 ;
        RECT  321.876 1137.416 321.996 1153.449 ;
        RECT  321.876 976.904 321.996 997.097 ;
        RECT  321.876 816.392 321.996 836.585 ;
        RECT  321.876 650.815 321.996 676.073 ;
        RECT  321.876 520.639 321.996 542.003 ;
        RECT  321.876 390.463 321.996 411.827 ;
        RECT  321.876 260.287 321.996 281.651 ;
        RECT  321.876 130.111 321.996 151.475 ;
        RECT  321.876 4.311 321.996 21.299 ;
        RECT  317.556 1137.416 317.676 1153.449 ;
        RECT  317.556 976.904 317.676 997.097 ;
        RECT  317.556 816.392 317.676 836.585 ;
        RECT  317.556 650.815 317.676 676.073 ;
        RECT  317.556 520.639 317.676 542.003 ;
        RECT  317.556 390.463 317.676 411.827 ;
        RECT  317.556 260.287 317.676 281.651 ;
        RECT  317.556 130.111 317.676 151.475 ;
        RECT  317.556 4.311 317.676 21.299 ;
        RECT  313.236 1137.416 313.356 1153.449 ;
        RECT  313.236 976.904 313.356 997.169 ;
        RECT  313.236 816.392 313.356 836.657 ;
        RECT  313.236 650.815 313.356 676.145 ;
        RECT  313.236 520.639 313.356 542.003 ;
        RECT  313.236 390.463 313.356 411.827 ;
        RECT  313.236 260.287 313.356 281.651 ;
        RECT  313.236 130.111 313.356 151.475 ;
        RECT  313.236 4.311 313.356 21.299 ;
        RECT  308.916 650.815 309.036 1153.449 ;
        RECT  308.916 520.639 309.036 542.003 ;
        RECT  308.916 390.463 309.036 411.827 ;
        RECT  308.916 260.287 309.036 281.651 ;
        RECT  308.916 130.111 309.036 151.475 ;
        RECT  308.916 4.311 309.036 21.299 ;
        RECT  304.596 650.815 304.716 1153.449 ;
        RECT  304.596 520.639 304.716 542.003 ;
        RECT  304.596 390.463 304.716 411.827 ;
        RECT  304.596 260.287 304.716 281.651 ;
        RECT  304.596 130.111 304.716 151.475 ;
        RECT  304.596 4.311 304.716 21.299 ;
        RECT  300.276 1137.416 300.396 1153.449 ;
        RECT  300.276 976.904 300.396 997.097 ;
        RECT  300.276 650.815 300.396 836.585 ;
        RECT  300.276 520.639 300.396 542.003 ;
        RECT  300.276 390.463 300.396 411.827 ;
        RECT  300.276 260.287 300.396 281.651 ;
        RECT  300.276 130.111 300.396 151.475 ;
        RECT  300.276 4.311 300.396 21.299 ;
        RECT  295.956 1137.416 296.076 1153.449 ;
        RECT  295.956 976.904 296.076 997.097 ;
        RECT  295.956 650.815 296.076 836.585 ;
        RECT  295.956 520.639 296.076 542.003 ;
        RECT  295.956 390.463 296.076 411.827 ;
        RECT  295.956 260.287 296.076 281.651 ;
        RECT  295.956 130.111 296.076 151.475 ;
        RECT  295.956 4.311 296.076 21.299 ;
        RECT  291.636 1137.416 291.756 1153.449 ;
        RECT  291.636 976.904 291.756 997.097 ;
        RECT  291.636 650.815 291.756 836.585 ;
        RECT  291.636 520.639 291.756 542.003 ;
        RECT  291.636 390.463 291.756 411.827 ;
        RECT  291.636 260.287 291.756 281.651 ;
        RECT  291.636 130.111 291.756 151.475 ;
        RECT  291.636 4.311 291.756 21.299 ;
        RECT  287.316 1137.416 287.436 1153.449 ;
        RECT  287.316 976.904 287.436 997.097 ;
        RECT  287.316 650.815 287.436 836.585 ;
        RECT  287.316 520.639 287.436 542.003 ;
        RECT  287.316 390.463 287.436 411.827 ;
        RECT  287.316 260.287 287.436 281.651 ;
        RECT  287.316 130.111 287.436 151.475 ;
        RECT  287.316 4.311 287.436 21.299 ;
        RECT  282.996 1137.416 283.116 1153.449 ;
        RECT  282.996 976.904 283.116 997.097 ;
        RECT  282.996 650.815 283.116 836.585 ;
        RECT  282.996 520.639 283.116 542.003 ;
        RECT  282.996 390.463 283.116 411.827 ;
        RECT  282.996 260.287 283.116 281.651 ;
        RECT  282.996 130.111 283.116 151.475 ;
        RECT  282.996 4.311 283.116 21.299 ;
        RECT  278.676 1137.416 278.796 1153.449 ;
        RECT  278.676 976.904 278.796 997.097 ;
        RECT  278.676 650.815 278.796 836.585 ;
        RECT  278.676 520.639 278.796 542.003 ;
        RECT  278.676 390.463 278.796 411.827 ;
        RECT  278.676 260.287 278.796 281.651 ;
        RECT  278.676 130.111 278.796 151.475 ;
        RECT  278.676 4.311 278.796 21.299 ;
        RECT  274.356 1137.416 274.476 1153.449 ;
        RECT  274.356 976.904 274.476 997.097 ;
        RECT  274.356 650.815 274.476 836.585 ;
        RECT  274.356 520.639 274.476 542.003 ;
        RECT  274.356 390.463 274.476 411.827 ;
        RECT  274.356 260.287 274.476 281.651 ;
        RECT  274.356 130.111 274.476 151.475 ;
        RECT  274.356 4.311 274.476 21.299 ;
        RECT  270.036 1137.416 270.156 1153.449 ;
        RECT  270.036 976.904 270.156 997.097 ;
        RECT  270.036 650.815 270.156 836.585 ;
        RECT  270.036 520.639 270.156 542.003 ;
        RECT  270.036 390.463 270.156 411.827 ;
        RECT  270.036 260.287 270.156 281.651 ;
        RECT  270.036 130.111 270.156 151.475 ;
        RECT  270.036 4.311 270.156 21.299 ;
        RECT  265.716 1137.416 265.836 1153.449 ;
        RECT  265.716 976.904 265.836 997.097 ;
        RECT  265.716 4.311 265.836 836.585 ;
        RECT  261.396 1137.416 261.516 1153.449 ;
        RECT  261.396 976.904 261.516 997.097 ;
        RECT  261.396 4.311 261.516 836.585 ;
        RECT  257.076 1137.416 257.196 1153.449 ;
        RECT  257.076 976.904 257.196 997.097 ;
        RECT  257.076 4.311 257.196 836.585 ;
        RECT  252.756 1137.416 252.876 1153.449 ;
        RECT  252.756 976.904 252.876 997.097 ;
        RECT  252.756 4.311 252.876 836.585 ;
        RECT  248.436 1137.416 248.556 1153.449 ;
        RECT  248.436 976.904 248.556 997.097 ;
        RECT  248.436 4.311 248.556 836.585 ;
        RECT  244.116 1137.416 244.236 1153.449 ;
        RECT  244.116 976.904 244.236 997.097 ;
        RECT  244.116 4.311 244.236 836.585 ;
        RECT  239.796 1137.416 239.916 1153.449 ;
        RECT  239.796 976.904 239.916 997.097 ;
        RECT  239.796 4.311 239.916 836.585 ;
        RECT  235.476 1137.416 235.596 1153.449 ;
        RECT  235.476 976.904 235.596 997.097 ;
        RECT  235.476 4.311 235.596 836.585 ;
        RECT  231.156 1137.416 231.276 1153.449 ;
        RECT  231.156 976.904 231.276 997.097 ;
        RECT  231.156 4.311 231.276 836.585 ;
        RECT  226.836 1137.416 226.956 1153.449 ;
        RECT  226.836 976.904 226.956 997.097 ;
        RECT  226.836 4.311 226.956 836.585 ;
        RECT  222.516 1137.416 222.636 1153.449 ;
        RECT  222.516 976.904 222.636 997.097 ;
        RECT  222.516 4.311 222.636 836.585 ;
        RECT  218.196 1137.416 218.316 1153.449 ;
        RECT  218.196 976.904 218.316 997.097 ;
        RECT  218.196 4.311 218.316 836.585 ;
        RECT  213.876 1137.416 213.996 1153.449 ;
        RECT  213.876 976.904 213.996 997.097 ;
        RECT  213.876 4.311 213.996 836.585 ;
        RECT  209.556 1137.416 209.676 1153.449 ;
        RECT  209.556 976.904 209.676 997.097 ;
        RECT  209.556 4.311 209.676 836.585 ;
        RECT  205.236 1137.416 205.356 1153.449 ;
        RECT  205.236 976.904 205.356 997.097 ;
        RECT  205.236 4.311 205.356 836.585 ;
        RECT  200.916 1137.416 201.036 1153.449 ;
        RECT  200.916 976.904 201.036 997.097 ;
        RECT  200.916 4.311 201.036 836.585 ;
        RECT  196.596 1137.416 196.716 1153.449 ;
        RECT  196.596 976.904 196.716 997.097 ;
        RECT  196.596 650.815 196.716 836.585 ;
        RECT  196.596 520.639 196.716 542.003 ;
        RECT  196.596 390.463 196.716 411.827 ;
        RECT  196.596 260.287 196.716 281.651 ;
        RECT  196.596 130.111 196.716 151.475 ;
        RECT  196.596 4.311 196.716 21.299 ;
        RECT  192.276 1137.416 192.396 1153.449 ;
        RECT  192.276 976.904 192.396 997.169 ;
        RECT  192.276 650.815 192.396 836.657 ;
        RECT  192.276 520.639 192.396 542.003 ;
        RECT  192.276 390.463 192.396 411.827 ;
        RECT  192.276 260.287 192.396 281.651 ;
        RECT  192.276 130.111 192.396 151.475 ;
        RECT  192.276 4.311 192.396 21.299 ;
        RECT  187.956 650.815 188.076 1153.449 ;
        RECT  187.956 520.639 188.076 542.003 ;
        RECT  187.956 390.463 188.076 411.827 ;
        RECT  187.956 260.287 188.076 281.651 ;
        RECT  187.956 130.111 188.076 151.475 ;
        RECT  187.956 4.311 188.076 21.299 ;
        RECT  183.636 650.815 183.756 1153.449 ;
        RECT  183.636 520.639 183.756 542.003 ;
        RECT  183.636 390.463 183.756 411.827 ;
        RECT  183.636 260.287 183.756 281.651 ;
        RECT  183.636 130.111 183.756 151.475 ;
        RECT  183.636 4.311 183.756 21.299 ;
        RECT  179.316 650.815 179.436 1153.449 ;
        RECT  179.316 520.639 179.436 542.003 ;
        RECT  179.316 390.463 179.436 411.827 ;
        RECT  179.316 260.287 179.436 281.651 ;
        RECT  179.316 130.111 179.436 151.475 ;
        RECT  179.316 4.311 179.436 21.299 ;
        RECT  174.996 650.815 175.116 1153.449 ;
        RECT  174.996 520.639 175.116 542.003 ;
        RECT  174.996 390.463 175.116 411.827 ;
        RECT  174.996 260.287 175.116 281.651 ;
        RECT  174.996 130.111 175.116 151.475 ;
        RECT  174.996 4.311 175.116 21.299 ;
        RECT  170.676 650.815 170.796 1153.449 ;
        RECT  170.676 520.639 170.796 542.003 ;
        RECT  170.676 390.463 170.796 411.827 ;
        RECT  170.676 260.287 170.796 281.651 ;
        RECT  170.676 130.111 170.796 151.475 ;
        RECT  170.676 4.311 170.796 21.299 ;
        RECT  166.356 650.815 166.476 1153.449 ;
        RECT  166.356 520.639 166.476 542.003 ;
        RECT  166.356 390.463 166.476 411.827 ;
        RECT  166.356 260.287 166.476 281.651 ;
        RECT  166.356 130.111 166.476 151.475 ;
        RECT  166.356 4.311 166.476 21.299 ;
        RECT  162.036 650.815 162.156 1153.449 ;
        RECT  162.036 520.639 162.156 542.003 ;
        RECT  162.036 390.463 162.156 411.827 ;
        RECT  162.036 260.287 162.156 281.651 ;
        RECT  162.036 130.111 162.156 151.475 ;
        RECT  162.036 4.311 162.156 21.299 ;
        RECT  157.716 650.815 157.836 1153.449 ;
        RECT  157.716 520.639 157.836 542.003 ;
        RECT  157.716 390.463 157.836 411.827 ;
        RECT  157.716 260.287 157.836 281.651 ;
        RECT  157.716 130.111 157.836 151.475 ;
        RECT  157.716 4.311 157.836 21.299 ;
        RECT  153.396 650.815 153.516 1153.449 ;
        RECT  153.396 520.639 153.516 542.003 ;
        RECT  153.396 390.463 153.516 411.827 ;
        RECT  153.396 260.287 153.516 281.651 ;
        RECT  153.396 130.111 153.516 151.475 ;
        RECT  153.396 4.311 153.516 21.299 ;
        RECT  149.076 650.815 149.196 1153.449 ;
        RECT  149.076 520.639 149.196 542.003 ;
        RECT  149.076 390.463 149.196 411.827 ;
        RECT  149.076 260.287 149.196 281.651 ;
        RECT  149.076 130.111 149.196 151.475 ;
        RECT  149.076 4.311 149.196 21.299 ;
        RECT  144.756 650.815 144.876 1153.449 ;
        RECT  144.756 520.639 144.876 542.003 ;
        RECT  144.756 390.463 144.876 411.827 ;
        RECT  144.756 260.287 144.876 281.651 ;
        RECT  144.756 130.111 144.876 151.475 ;
        RECT  144.756 4.311 144.876 21.299 ;
        RECT  140.436 650.815 140.556 1153.449 ;
        RECT  140.436 520.639 140.556 542.003 ;
        RECT  140.436 390.463 140.556 411.827 ;
        RECT  140.436 260.287 140.556 281.651 ;
        RECT  140.436 130.111 140.556 151.475 ;
        RECT  140.436 4.311 140.556 21.299 ;
        RECT  136.116 1137.416 136.236 1153.449 ;
        RECT  136.116 976.904 136.236 997.169 ;
        RECT  136.116 816.392 136.236 836.657 ;
        RECT  136.116 650.815 136.236 676.145 ;
        RECT  136.116 520.639 136.236 542.003 ;
        RECT  136.116 390.463 136.236 411.827 ;
        RECT  136.116 260.287 136.236 281.651 ;
        RECT  136.116 130.111 136.236 151.475 ;
        RECT  136.116 4.311 136.236 21.299 ;
        RECT  131.796 1137.416 131.916 1153.449 ;
        RECT  131.796 976.904 131.916 997.097 ;
        RECT  131.796 816.392 131.916 836.585 ;
        RECT  131.796 650.815 131.916 676.073 ;
        RECT  131.796 520.639 131.916 542.003 ;
        RECT  131.796 390.463 131.916 411.827 ;
        RECT  131.796 260.287 131.916 281.651 ;
        RECT  131.796 130.111 131.916 151.475 ;
        RECT  131.796 4.311 131.916 21.299 ;
        RECT  127.476 1137.416 127.596 1153.449 ;
        RECT  127.476 976.904 127.596 997.097 ;
        RECT  127.476 816.392 127.596 836.585 ;
        RECT  127.476 650.815 127.596 676.073 ;
        RECT  127.476 520.639 127.596 542.003 ;
        RECT  127.476 390.463 127.596 411.827 ;
        RECT  127.476 260.287 127.596 281.651 ;
        RECT  127.476 130.111 127.596 151.475 ;
        RECT  127.476 4.311 127.596 21.299 ;
        RECT  123.156 1137.416 123.276 1153.449 ;
        RECT  123.156 976.904 123.276 997.097 ;
        RECT  123.156 816.392 123.276 836.585 ;
        RECT  123.156 650.815 123.276 676.073 ;
        RECT  123.156 520.639 123.276 542.003 ;
        RECT  123.156 390.463 123.276 411.827 ;
        RECT  123.156 260.287 123.276 281.651 ;
        RECT  123.156 130.111 123.276 151.475 ;
        RECT  123.156 4.311 123.276 21.299 ;
        RECT  118.836 1137.416 118.956 1153.449 ;
        RECT  118.836 976.904 118.956 997.097 ;
        RECT  118.836 816.392 118.956 836.585 ;
        RECT  118.836 650.815 118.956 676.073 ;
        RECT  118.836 520.639 118.956 542.003 ;
        RECT  118.836 390.463 118.956 411.827 ;
        RECT  118.836 260.287 118.956 281.651 ;
        RECT  118.836 130.111 118.956 151.475 ;
        RECT  118.836 4.311 118.956 21.299 ;
        RECT  114.516 1137.416 114.636 1153.449 ;
        RECT  114.516 976.904 114.636 997.097 ;
        RECT  114.516 816.392 114.636 836.585 ;
        RECT  114.516 650.815 114.636 676.073 ;
        RECT  114.516 520.639 114.636 542.003 ;
        RECT  114.516 390.463 114.636 411.827 ;
        RECT  114.516 260.287 114.636 281.651 ;
        RECT  114.516 130.111 114.636 151.475 ;
        RECT  114.516 4.311 114.636 21.299 ;
        RECT  110.196 1137.416 110.316 1153.449 ;
        RECT  110.196 976.904 110.316 997.097 ;
        RECT  110.196 816.392 110.316 836.585 ;
        RECT  110.196 650.815 110.316 676.073 ;
        RECT  110.196 520.639 110.316 542.003 ;
        RECT  110.196 390.463 110.316 411.827 ;
        RECT  110.196 260.287 110.316 281.651 ;
        RECT  110.196 130.111 110.316 151.475 ;
        RECT  110.196 4.311 110.316 21.299 ;
        RECT  105.876 1137.416 105.996 1153.449 ;
        RECT  105.876 976.904 105.996 997.097 ;
        RECT  105.876 816.392 105.996 836.585 ;
        RECT  105.876 650.815 105.996 676.073 ;
        RECT  105.876 520.639 105.996 542.003 ;
        RECT  105.876 390.463 105.996 411.827 ;
        RECT  105.876 260.287 105.996 281.651 ;
        RECT  105.876 130.111 105.996 151.475 ;
        RECT  105.876 4.311 105.996 21.299 ;
        RECT  101.556 1137.416 101.676 1153.449 ;
        RECT  101.556 976.904 101.676 997.097 ;
        RECT  101.556 816.392 101.676 836.585 ;
        RECT  101.556 650.815 101.676 676.073 ;
        RECT  101.556 520.639 101.676 542.003 ;
        RECT  101.556 390.463 101.676 411.827 ;
        RECT  101.556 260.287 101.676 281.651 ;
        RECT  101.556 130.111 101.676 151.475 ;
        RECT  101.556 4.311 101.676 21.299 ;
        RECT  97.236 1137.416 97.356 1153.449 ;
        RECT  97.236 976.904 97.356 997.097 ;
        RECT  97.236 816.392 97.356 836.585 ;
        RECT  97.236 650.815 97.356 676.073 ;
        RECT  97.236 520.639 97.356 542.003 ;
        RECT  97.236 390.463 97.356 411.827 ;
        RECT  97.236 260.287 97.356 281.651 ;
        RECT  97.236 130.111 97.356 151.475 ;
        RECT  97.236 4.311 97.356 21.299 ;
        RECT  92.916 1137.416 93.036 1153.449 ;
        RECT  92.916 976.904 93.036 997.097 ;
        RECT  92.916 816.392 93.036 836.585 ;
        RECT  92.916 650.815 93.036 676.073 ;
        RECT  92.916 520.639 93.036 542.003 ;
        RECT  92.916 390.463 93.036 411.827 ;
        RECT  92.916 260.287 93.036 281.651 ;
        RECT  92.916 130.111 93.036 151.475 ;
        RECT  92.916 4.311 93.036 21.299 ;
        RECT  88.596 1137.416 88.716 1153.449 ;
        RECT  88.596 976.904 88.716 997.097 ;
        RECT  88.596 816.392 88.716 836.585 ;
        RECT  88.596 650.815 88.716 676.073 ;
        RECT  88.596 520.639 88.716 542.003 ;
        RECT  88.596 390.463 88.716 411.827 ;
        RECT  88.596 260.287 88.716 281.651 ;
        RECT  88.596 130.111 88.716 151.475 ;
        RECT  88.596 4.311 88.716 21.299 ;
        RECT  84.276 1137.416 84.396 1153.449 ;
        RECT  84.276 976.904 84.396 997.097 ;
        RECT  84.276 816.392 84.396 836.585 ;
        RECT  84.276 650.815 84.396 676.073 ;
        RECT  84.276 520.639 84.396 542.003 ;
        RECT  84.276 390.463 84.396 411.827 ;
        RECT  84.276 260.287 84.396 281.651 ;
        RECT  84.276 130.111 84.396 151.475 ;
        RECT  84.276 4.311 84.396 21.299 ;
        RECT  79.956 1137.416 80.076 1153.449 ;
        RECT  79.956 976.904 80.076 997.097 ;
        RECT  79.956 816.392 80.076 836.585 ;
        RECT  79.956 650.815 80.076 676.073 ;
        RECT  79.956 520.639 80.076 542.003 ;
        RECT  79.956 390.463 80.076 411.827 ;
        RECT  79.956 260.287 80.076 281.651 ;
        RECT  79.956 130.111 80.076 151.475 ;
        RECT  79.956 4.311 80.076 21.299 ;
        RECT  75.636 1137.416 75.756 1153.449 ;
        RECT  75.636 976.904 75.756 997.097 ;
        RECT  75.636 816.392 75.756 836.585 ;
        RECT  75.636 650.815 75.756 676.073 ;
        RECT  75.636 520.639 75.756 542.003 ;
        RECT  75.636 390.463 75.756 411.827 ;
        RECT  75.636 260.287 75.756 281.651 ;
        RECT  75.636 130.111 75.756 151.475 ;
        RECT  75.636 4.311 75.756 21.299 ;
        RECT  71.316 1137.416 71.436 1153.449 ;
        RECT  71.316 976.904 71.436 997.097 ;
        RECT  71.316 816.392 71.436 836.585 ;
        RECT  71.316 650.815 71.436 676.073 ;
        RECT  71.316 520.639 71.436 542.003 ;
        RECT  71.316 390.463 71.436 411.827 ;
        RECT  71.316 260.287 71.436 281.651 ;
        RECT  71.316 130.111 71.436 151.475 ;
        RECT  71.316 4.311 71.436 21.299 ;
        RECT  66.996 1137.416 67.116 1153.449 ;
        RECT  66.996 976.904 67.116 997.097 ;
        RECT  66.996 816.392 67.116 836.585 ;
        RECT  66.996 650.815 67.116 676.073 ;
        RECT  66.996 520.639 67.116 542.003 ;
        RECT  66.996 390.463 67.116 411.827 ;
        RECT  66.996 260.287 67.116 281.651 ;
        RECT  66.996 130.111 67.116 151.475 ;
        RECT  66.996 4.311 67.116 21.299 ;
        RECT  62.676 1137.416 62.796 1153.449 ;
        RECT  62.676 976.904 62.796 997.097 ;
        RECT  62.676 816.392 62.796 836.585 ;
        RECT  62.676 650.815 62.796 676.073 ;
        RECT  62.676 520.639 62.796 542.003 ;
        RECT  62.676 390.463 62.796 411.827 ;
        RECT  62.676 260.287 62.796 281.651 ;
        RECT  62.676 130.111 62.796 151.475 ;
        RECT  62.676 4.311 62.796 21.299 ;
        RECT  58.356 1137.416 58.476 1153.449 ;
        RECT  58.356 976.904 58.476 997.097 ;
        RECT  58.356 816.392 58.476 836.585 ;
        RECT  58.356 650.815 58.476 676.073 ;
        RECT  58.356 520.639 58.476 542.003 ;
        RECT  58.356 390.463 58.476 411.827 ;
        RECT  58.356 260.287 58.476 281.651 ;
        RECT  58.356 130.111 58.476 151.475 ;
        RECT  58.356 4.311 58.476 21.299 ;
        RECT  54.036 1137.416 54.156 1153.449 ;
        RECT  54.036 976.904 54.156 997.097 ;
        RECT  54.036 816.392 54.156 836.585 ;
        RECT  54.036 650.815 54.156 676.073 ;
        RECT  54.036 520.639 54.156 542.003 ;
        RECT  54.036 390.463 54.156 411.827 ;
        RECT  54.036 260.287 54.156 281.651 ;
        RECT  54.036 130.111 54.156 151.475 ;
        RECT  54.036 4.311 54.156 21.299 ;
        RECT  49.716 1137.416 49.836 1153.449 ;
        RECT  49.716 976.904 49.836 997.097 ;
        RECT  49.716 816.392 49.836 836.585 ;
        RECT  49.716 650.815 49.836 676.073 ;
        RECT  49.716 520.639 49.836 542.003 ;
        RECT  49.716 390.463 49.836 411.827 ;
        RECT  49.716 260.287 49.836 281.651 ;
        RECT  49.716 130.111 49.836 151.475 ;
        RECT  49.716 4.311 49.836 21.299 ;
        RECT  45.396 1137.416 45.516 1153.449 ;
        RECT  45.396 976.904 45.516 997.097 ;
        RECT  45.396 816.392 45.516 836.585 ;
        RECT  45.396 650.815 45.516 676.073 ;
        RECT  45.396 520.639 45.516 542.003 ;
        RECT  45.396 390.463 45.516 411.827 ;
        RECT  45.396 260.287 45.516 281.651 ;
        RECT  45.396 130.111 45.516 151.475 ;
        RECT  45.396 4.311 45.516 21.299 ;
        RECT  41.076 1137.416 41.196 1153.449 ;
        RECT  41.076 976.904 41.196 997.097 ;
        RECT  41.076 816.392 41.196 836.585 ;
        RECT  41.076 650.815 41.196 676.073 ;
        RECT  41.076 520.639 41.196 542.003 ;
        RECT  41.076 390.463 41.196 411.827 ;
        RECT  41.076 260.287 41.196 281.651 ;
        RECT  41.076 130.111 41.196 151.475 ;
        RECT  41.076 4.311 41.196 21.299 ;
        RECT  36.756 1137.416 36.876 1153.449 ;
        RECT  36.756 976.904 36.876 997.097 ;
        RECT  36.756 816.392 36.876 836.585 ;
        RECT  36.756 650.815 36.876 676.073 ;
        RECT  36.756 520.639 36.876 542.003 ;
        RECT  36.756 390.463 36.876 411.827 ;
        RECT  36.756 260.287 36.876 281.651 ;
        RECT  36.756 130.111 36.876 151.475 ;
        RECT  36.756 4.311 36.876 21.299 ;
        RECT  32.436 1137.416 32.556 1153.449 ;
        RECT  32.436 976.904 32.556 997.097 ;
        RECT  32.436 816.392 32.556 836.585 ;
        RECT  32.436 650.815 32.556 676.073 ;
        RECT  32.436 520.639 32.556 542.003 ;
        RECT  32.436 390.463 32.556 411.827 ;
        RECT  32.436 260.287 32.556 281.651 ;
        RECT  32.436 130.111 32.556 151.475 ;
        RECT  32.436 4.311 32.556 21.299 ;
        RECT  28.116 1137.416 28.236 1153.449 ;
        RECT  28.116 976.904 28.236 997.097 ;
        RECT  28.116 816.392 28.236 836.585 ;
        RECT  28.116 650.815 28.236 676.073 ;
        RECT  28.116 520.639 28.236 542.003 ;
        RECT  28.116 390.463 28.236 411.827 ;
        RECT  28.116 260.287 28.236 281.651 ;
        RECT  28.116 130.111 28.236 151.475 ;
        RECT  28.116 4.311 28.236 21.299 ;
        RECT  23.796 1137.416 23.916 1153.449 ;
        RECT  23.796 976.904 23.916 997.169 ;
        RECT  23.796 816.392 23.916 836.657 ;
        RECT  23.796 4.311 23.916 676.145 ;
        RECT  19.476 4.311 19.596 1153.449 ;
        RECT  15.156 4.311 15.276 1153.449 ;
        RECT  10.836 4.311 10.956 1153.449 ;
        RECT  6.516 4.311 6.636 1153.449 ;
    END
  END VDD
  OBS
    LAYER RVTN ;
     RECT  0 4.297 457.92 1153.463 ;
    LAYER RVTP ;
     RECT  0 4.297 457.92 1153.463 ;
    LAYER M1 ;
     RECT  0 4.297 457.92 1153.463 ;
    LAYER M2 ;
     RECT  0 4.297 457.92 1153.463 ;
    LAYER M3 ;
     RECT  0 4.297 457.92 1153.463 ;
    LAYER M4 ;
     RECT  0 4.297 457.92 1153.463 ;
    LAYER M5 ;
     RECT  0 4.297 457.92 1153.463 ;
    LAYER M6 ;
     RECT  0 4.297 457.92 1153.463 ;
    LAYER M7 ;
     RECT  0 4.297 457.92 1153.463 ;
  END
END qfd_tile_nl_a0c
END LIBRARY
